VERSION 5.8 ; 
BUSBITCHARS "[]" ; 
DIVIDERCHAR "/" ; 
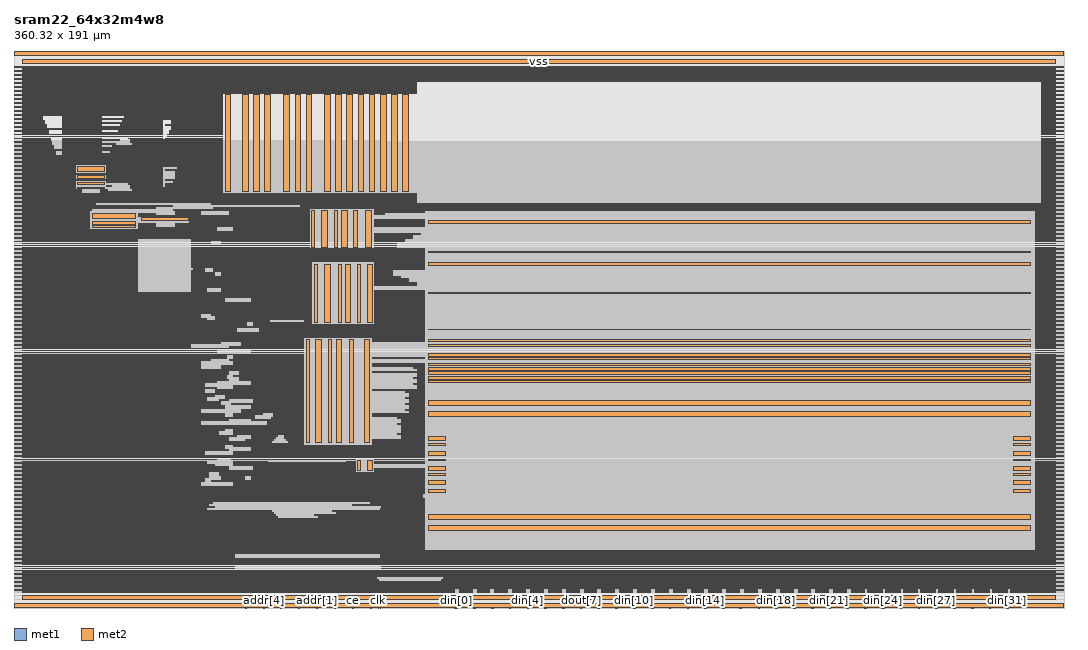
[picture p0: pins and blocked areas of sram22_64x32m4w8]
MACRO sram22_64x32m4w8
    CLASS BLOCK  ;
    FOREIGN sram22_64x32m4w8   ;
    SIZE 360.320 BY 191.000 ;
    SYMMETRY X Y R90 ;
    PIN dout[0] 
        DIRECTION OUTPUT ; 
        ANTENNADIFFAREA 0.448000 LAYER met2 ;
        ANTENNAPARTIALMETALAREA 0.950300 LAYER met1 ;
        ANTENNAPARTIALMETALAREA 7.107200 LAYER met2 ;
        PORT 
            LAYER met1 ;
                RECT 152.070 0.000 152.210 0.140 ;
        END 
    END dout[0] 
    PIN dout[1] 
        DIRECTION OUTPUT ; 
        ANTENNADIFFAREA 0.448000 LAYER met2 ;
        ANTENNAPARTIALMETALAREA 0.950300 LAYER met1 ;
        ANTENNAPARTIALMETALAREA 7.107200 LAYER met2 ;
        PORT 
            LAYER met1 ;
                RECT 158.170 0.000 158.310 0.140 ;
        END 
    END dout[1] 
    PIN dout[2] 
        DIRECTION OUTPUT ; 
        ANTENNADIFFAREA 0.448000 LAYER met2 ;
        ANTENNAPARTIALMETALAREA 0.950300 LAYER met1 ;
        ANTENNAPARTIALMETALAREA 7.107200 LAYER met2 ;
        PORT 
            LAYER met1 ;
                RECT 164.270 0.000 164.410 0.140 ;
        END 
    END dout[2] 
    PIN dout[3] 
        DIRECTION OUTPUT ; 
        ANTENNADIFFAREA 0.448000 LAYER met2 ;
        ANTENNAPARTIALMETALAREA 0.950300 LAYER met1 ;
        ANTENNAPARTIALMETALAREA 7.107200 LAYER met2 ;
        PORT 
            LAYER met1 ;
                RECT 170.370 0.000 170.510 0.140 ;
        END 
    END dout[3] 
    PIN dout[4] 
        DIRECTION OUTPUT ; 
        ANTENNADIFFAREA 0.448000 LAYER met2 ;
        ANTENNAPARTIALMETALAREA 0.950300 LAYER met1 ;
        ANTENNAPARTIALMETALAREA 7.107200 LAYER met2 ;
        PORT 
            LAYER met1 ;
                RECT 176.470 0.000 176.610 0.140 ;
        END 
    END dout[4] 
    PIN dout[5] 
        DIRECTION OUTPUT ; 
        ANTENNADIFFAREA 0.448000 LAYER met2 ;
        ANTENNAPARTIALMETALAREA 0.950300 LAYER met1 ;
        ANTENNAPARTIALMETALAREA 7.107200 LAYER met2 ;
        PORT 
            LAYER met1 ;
                RECT 182.570 0.000 182.710 0.140 ;
        END 
    END dout[5] 
    PIN dout[6] 
        DIRECTION OUTPUT ; 
        ANTENNADIFFAREA 0.448000 LAYER met2 ;
        ANTENNAPARTIALMETALAREA 0.950300 LAYER met1 ;
        ANTENNAPARTIALMETALAREA 7.107200 LAYER met2 ;
        PORT 
            LAYER met1 ;
                RECT 188.670 0.000 188.810 0.140 ;
        END 
    END dout[6] 
    PIN dout[7] 
        DIRECTION OUTPUT ; 
        ANTENNADIFFAREA 0.448000 LAYER met2 ;
        ANTENNAPARTIALMETALAREA 0.950300 LAYER met1 ;
        ANTENNAPARTIALMETALAREA 7.107200 LAYER met2 ;
        PORT 
            LAYER met1 ;
                RECT 194.770 0.000 194.910 0.140 ;
        END 
    END dout[7] 
    PIN dout[8] 
        DIRECTION OUTPUT ; 
        ANTENNADIFFAREA 0.448000 LAYER met2 ;
        ANTENNAPARTIALMETALAREA 0.950300 LAYER met1 ;
        ANTENNAPARTIALMETALAREA 7.107200 LAYER met2 ;
        PORT 
            LAYER met1 ;
                RECT 200.870 0.000 201.010 0.140 ;
        END 
    END dout[8] 
    PIN dout[9] 
        DIRECTION OUTPUT ; 
        ANTENNADIFFAREA 0.448000 LAYER met2 ;
        ANTENNAPARTIALMETALAREA 0.950300 LAYER met1 ;
        ANTENNAPARTIALMETALAREA 7.107200 LAYER met2 ;
        PORT 
            LAYER met1 ;
                RECT 206.970 0.000 207.110 0.140 ;
        END 
    END dout[9] 
    PIN dout[10] 
        DIRECTION OUTPUT ; 
        ANTENNADIFFAREA 0.448000 LAYER met2 ;
        ANTENNAPARTIALMETALAREA 0.950300 LAYER met1 ;
        ANTENNAPARTIALMETALAREA 7.107200 LAYER met2 ;
        PORT 
            LAYER met1 ;
                RECT 213.070 0.000 213.210 0.140 ;
        END 
    END dout[10] 
    PIN dout[11] 
        DIRECTION OUTPUT ; 
        ANTENNADIFFAREA 0.448000 LAYER met2 ;
        ANTENNAPARTIALMETALAREA 0.950300 LAYER met1 ;
        ANTENNAPARTIALMETALAREA 7.107200 LAYER met2 ;
        PORT 
            LAYER met1 ;
                RECT 219.170 0.000 219.310 0.140 ;
        END 
    END dout[11] 
    PIN dout[12] 
        DIRECTION OUTPUT ; 
        ANTENNADIFFAREA 0.448000 LAYER met2 ;
        ANTENNAPARTIALMETALAREA 0.950300 LAYER met1 ;
        ANTENNAPARTIALMETALAREA 7.107200 LAYER met2 ;
        PORT 
            LAYER met1 ;
                RECT 225.270 0.000 225.410 0.140 ;
        END 
    END dout[12] 
    PIN dout[13] 
        DIRECTION OUTPUT ; 
        ANTENNADIFFAREA 0.448000 LAYER met2 ;
        ANTENNAPARTIALMETALAREA 0.950300 LAYER met1 ;
        ANTENNAPARTIALMETALAREA 7.107200 LAYER met2 ;
        PORT 
            LAYER met1 ;
                RECT 231.370 0.000 231.510 0.140 ;
        END 
    END dout[13] 
    PIN dout[14] 
        DIRECTION OUTPUT ; 
        ANTENNADIFFAREA 0.448000 LAYER met2 ;
        ANTENNAPARTIALMETALAREA 0.950300 LAYER met1 ;
        ANTENNAPARTIALMETALAREA 7.107200 LAYER met2 ;
        PORT 
            LAYER met1 ;
                RECT 237.470 0.000 237.610 0.140 ;
        END 
    END dout[14] 
    PIN dout[15] 
        DIRECTION OUTPUT ; 
        ANTENNADIFFAREA 0.448000 LAYER met2 ;
        ANTENNAPARTIALMETALAREA 0.950300 LAYER met1 ;
        ANTENNAPARTIALMETALAREA 7.107200 LAYER met2 ;
        PORT 
            LAYER met1 ;
                RECT 243.570 0.000 243.710 0.140 ;
        END 
    END dout[15] 
    PIN dout[16] 
        DIRECTION OUTPUT ; 
        ANTENNADIFFAREA 0.448000 LAYER met2 ;
        ANTENNAPARTIALMETALAREA 0.950300 LAYER met1 ;
        ANTENNAPARTIALMETALAREA 7.107200 LAYER met2 ;
        PORT 
            LAYER met1 ;
                RECT 249.670 0.000 249.810 0.140 ;
        END 
    END dout[16] 
    PIN dout[17] 
        DIRECTION OUTPUT ; 
        ANTENNADIFFAREA 0.448000 LAYER met2 ;
        ANTENNAPARTIALMETALAREA 0.950300 LAYER met1 ;
        ANTENNAPARTIALMETALAREA 7.107200 LAYER met2 ;
        PORT 
            LAYER met1 ;
                RECT 255.770 0.000 255.910 0.140 ;
        END 
    END dout[17] 
    PIN dout[18] 
        DIRECTION OUTPUT ; 
        ANTENNADIFFAREA 0.448000 LAYER met2 ;
        ANTENNAPARTIALMETALAREA 0.950300 LAYER met1 ;
        ANTENNAPARTIALMETALAREA 7.107200 LAYER met2 ;
        PORT 
            LAYER met1 ;
                RECT 261.870 0.000 262.010 0.140 ;
        END 
    END dout[18] 
    PIN dout[19] 
        DIRECTION OUTPUT ; 
        ANTENNADIFFAREA 0.448000 LAYER met2 ;
        ANTENNAPARTIALMETALAREA 0.950300 LAYER met1 ;
        ANTENNAPARTIALMETALAREA 7.107200 LAYER met2 ;
        PORT 
            LAYER met1 ;
                RECT 267.970 0.000 268.110 0.140 ;
        END 
    END dout[19] 
    PIN dout[20] 
        DIRECTION OUTPUT ; 
        ANTENNADIFFAREA 0.448000 LAYER met2 ;
        ANTENNAPARTIALMETALAREA 0.950300 LAYER met1 ;
        ANTENNAPARTIALMETALAREA 7.107200 LAYER met2 ;
        PORT 
            LAYER met1 ;
                RECT 274.070 0.000 274.210 0.140 ;
        END 
    END dout[20] 
    PIN dout[21] 
        DIRECTION OUTPUT ; 
        ANTENNADIFFAREA 0.448000 LAYER met2 ;
        ANTENNAPARTIALMETALAREA 0.950300 LAYER met1 ;
        ANTENNAPARTIALMETALAREA 7.107200 LAYER met2 ;
        PORT 
            LAYER met1 ;
                RECT 280.170 0.000 280.310 0.140 ;
        END 
    END dout[21] 
    PIN dout[22] 
        DIRECTION OUTPUT ; 
        ANTENNADIFFAREA 0.448000 LAYER met2 ;
        ANTENNAPARTIALMETALAREA 0.950300 LAYER met1 ;
        ANTENNAPARTIALMETALAREA 7.107200 LAYER met2 ;
        PORT 
            LAYER met1 ;
                RECT 286.270 0.000 286.410 0.140 ;
        END 
    END dout[22] 
    PIN dout[23] 
        DIRECTION OUTPUT ; 
        ANTENNADIFFAREA 0.448000 LAYER met2 ;
        ANTENNAPARTIALMETALAREA 0.950300 LAYER met1 ;
        ANTENNAPARTIALMETALAREA 7.107200 LAYER met2 ;
        PORT 
            LAYER met1 ;
                RECT 292.370 0.000 292.510 0.140 ;
        END 
    END dout[23] 
    PIN dout[24] 
        DIRECTION OUTPUT ; 
        ANTENNADIFFAREA 0.448000 LAYER met2 ;
        ANTENNAPARTIALMETALAREA 0.950300 LAYER met1 ;
        ANTENNAPARTIALMETALAREA 7.107200 LAYER met2 ;
        PORT 
            LAYER met1 ;
                RECT 298.470 0.000 298.610 0.140 ;
        END 
    END dout[24] 
    PIN dout[25] 
        DIRECTION OUTPUT ; 
        ANTENNADIFFAREA 0.448000 LAYER met2 ;
        ANTENNAPARTIALMETALAREA 0.950300 LAYER met1 ;
        ANTENNAPARTIALMETALAREA 7.107200 LAYER met2 ;
        PORT 
            LAYER met1 ;
                RECT 304.570 0.000 304.710 0.140 ;
        END 
    END dout[25] 
    PIN dout[26] 
        DIRECTION OUTPUT ; 
        ANTENNADIFFAREA 0.448000 LAYER met2 ;
        ANTENNAPARTIALMETALAREA 0.950300 LAYER met1 ;
        ANTENNAPARTIALMETALAREA 7.107200 LAYER met2 ;
        PORT 
            LAYER met1 ;
                RECT 310.670 0.000 310.810 0.140 ;
        END 
    END dout[26] 
    PIN dout[27] 
        DIRECTION OUTPUT ; 
        ANTENNADIFFAREA 0.448000 LAYER met2 ;
        ANTENNAPARTIALMETALAREA 0.950300 LAYER met1 ;
        ANTENNAPARTIALMETALAREA 7.107200 LAYER met2 ;
        PORT 
            LAYER met1 ;
                RECT 316.770 0.000 316.910 0.140 ;
        END 
    END dout[27] 
    PIN dout[28] 
        DIRECTION OUTPUT ; 
        ANTENNADIFFAREA 0.448000 LAYER met2 ;
        ANTENNAPARTIALMETALAREA 0.950300 LAYER met1 ;
        ANTENNAPARTIALMETALAREA 7.107200 LAYER met2 ;
        PORT 
            LAYER met1 ;
                RECT 322.870 0.000 323.010 0.140 ;
        END 
    END dout[28] 
    PIN dout[29] 
        DIRECTION OUTPUT ; 
        ANTENNADIFFAREA 0.448000 LAYER met2 ;
        ANTENNAPARTIALMETALAREA 0.950300 LAYER met1 ;
        ANTENNAPARTIALMETALAREA 7.107200 LAYER met2 ;
        PORT 
            LAYER met1 ;
                RECT 328.970 0.000 329.110 0.140 ;
        END 
    END dout[29] 
    PIN dout[30] 
        DIRECTION OUTPUT ; 
        ANTENNADIFFAREA 0.448000 LAYER met2 ;
        ANTENNAPARTIALMETALAREA 0.950300 LAYER met1 ;
        ANTENNAPARTIALMETALAREA 7.107200 LAYER met2 ;
        PORT 
            LAYER met1 ;
                RECT 335.070 0.000 335.210 0.140 ;
        END 
    END dout[30] 
    PIN dout[31] 
        DIRECTION OUTPUT ; 
        ANTENNADIFFAREA 0.448000 LAYER met2 ;
        ANTENNAPARTIALMETALAREA 0.950300 LAYER met1 ;
        ANTENNAPARTIALMETALAREA 7.107200 LAYER met2 ;
        PORT 
            LAYER met1 ;
                RECT 341.170 0.000 341.310 0.140 ;
        END 
    END dout[31] 
    PIN din[0] 
        DIRECTION INPUT ; 
        ANTENNAGATEAREA 0.126000 LAYER met2 ;
        ANTENNAPARTIALMETALAREA 5.238500 LAYER met1 ;
        ANTENNAPARTIALMETALAREA 6.828800 LAYER met2 ;
        PORT 
            LAYER met1 ;
                RECT 151.650 0.000 151.790 0.140 ;
        END 
    END din[0] 
    PIN din[1] 
        DIRECTION INPUT ; 
        ANTENNAGATEAREA 0.126000 LAYER met2 ;
        ANTENNAPARTIALMETALAREA 5.238500 LAYER met1 ;
        ANTENNAPARTIALMETALAREA 6.828800 LAYER met2 ;
        PORT 
            LAYER met1 ;
                RECT 157.750 0.000 157.890 0.140 ;
        END 
    END din[1] 
    PIN din[2] 
        DIRECTION INPUT ; 
        ANTENNAGATEAREA 0.126000 LAYER met2 ;
        ANTENNAPARTIALMETALAREA 5.238500 LAYER met1 ;
        ANTENNAPARTIALMETALAREA 6.828800 LAYER met2 ;
        PORT 
            LAYER met1 ;
                RECT 163.850 0.000 163.990 0.140 ;
        END 
    END din[2] 
    PIN din[3] 
        DIRECTION INPUT ; 
        ANTENNAGATEAREA 0.126000 LAYER met2 ;
        ANTENNAPARTIALMETALAREA 5.238500 LAYER met1 ;
        ANTENNAPARTIALMETALAREA 6.828800 LAYER met2 ;
        PORT 
            LAYER met1 ;
                RECT 169.950 0.000 170.090 0.140 ;
        END 
    END din[3] 
    PIN din[4] 
        DIRECTION INPUT ; 
        ANTENNAGATEAREA 0.126000 LAYER met2 ;
        ANTENNAPARTIALMETALAREA 5.238500 LAYER met1 ;
        ANTENNAPARTIALMETALAREA 6.828800 LAYER met2 ;
        PORT 
            LAYER met1 ;
                RECT 176.050 0.000 176.190 0.140 ;
        END 
    END din[4] 
    PIN din[5] 
        DIRECTION INPUT ; 
        ANTENNAGATEAREA 0.126000 LAYER met2 ;
        ANTENNAPARTIALMETALAREA 5.238500 LAYER met1 ;
        ANTENNAPARTIALMETALAREA 6.828800 LAYER met2 ;
        PORT 
            LAYER met1 ;
                RECT 182.150 0.000 182.290 0.140 ;
        END 
    END din[5] 
    PIN din[6] 
        DIRECTION INPUT ; 
        ANTENNAGATEAREA 0.126000 LAYER met2 ;
        ANTENNAPARTIALMETALAREA 5.238500 LAYER met1 ;
        ANTENNAPARTIALMETALAREA 6.828800 LAYER met2 ;
        PORT 
            LAYER met1 ;
                RECT 188.250 0.000 188.390 0.140 ;
        END 
    END din[6] 
    PIN din[7] 
        DIRECTION INPUT ; 
        ANTENNAGATEAREA 0.126000 LAYER met2 ;
        ANTENNAPARTIALMETALAREA 5.238500 LAYER met1 ;
        ANTENNAPARTIALMETALAREA 6.828800 LAYER met2 ;
        PORT 
            LAYER met1 ;
                RECT 194.350 0.000 194.490 0.140 ;
        END 
    END din[7] 
    PIN din[8] 
        DIRECTION INPUT ; 
        ANTENNAGATEAREA 0.126000 LAYER met2 ;
        ANTENNAPARTIALMETALAREA 5.238500 LAYER met1 ;
        ANTENNAPARTIALMETALAREA 6.828800 LAYER met2 ;
        PORT 
            LAYER met1 ;
                RECT 200.450 0.000 200.590 0.140 ;
        END 
    END din[8] 
    PIN din[9] 
        DIRECTION INPUT ; 
        ANTENNAGATEAREA 0.126000 LAYER met2 ;
        ANTENNAPARTIALMETALAREA 5.238500 LAYER met1 ;
        ANTENNAPARTIALMETALAREA 6.828800 LAYER met2 ;
        PORT 
            LAYER met1 ;
                RECT 206.550 0.000 206.690 0.140 ;
        END 
    END din[9] 
    PIN din[10] 
        DIRECTION INPUT ; 
        ANTENNAGATEAREA 0.126000 LAYER met2 ;
        ANTENNAPARTIALMETALAREA 5.238500 LAYER met1 ;
        ANTENNAPARTIALMETALAREA 6.828800 LAYER met2 ;
        PORT 
            LAYER met1 ;
                RECT 212.650 0.000 212.790 0.140 ;
        END 
    END din[10] 
    PIN din[11] 
        DIRECTION INPUT ; 
        ANTENNAGATEAREA 0.126000 LAYER met2 ;
        ANTENNAPARTIALMETALAREA 5.238500 LAYER met1 ;
        ANTENNAPARTIALMETALAREA 6.828800 LAYER met2 ;
        PORT 
            LAYER met1 ;
                RECT 218.750 0.000 218.890 0.140 ;
        END 
    END din[11] 
    PIN din[12] 
        DIRECTION INPUT ; 
        ANTENNAGATEAREA 0.126000 LAYER met2 ;
        ANTENNAPARTIALMETALAREA 5.238500 LAYER met1 ;
        ANTENNAPARTIALMETALAREA 6.828800 LAYER met2 ;
        PORT 
            LAYER met1 ;
                RECT 224.850 0.000 224.990 0.140 ;
        END 
    END din[12] 
    PIN din[13] 
        DIRECTION INPUT ; 
        ANTENNAGATEAREA 0.126000 LAYER met2 ;
        ANTENNAPARTIALMETALAREA 5.238500 LAYER met1 ;
        ANTENNAPARTIALMETALAREA 6.828800 LAYER met2 ;
        PORT 
            LAYER met1 ;
                RECT 230.950 0.000 231.090 0.140 ;
        END 
    END din[13] 
    PIN din[14] 
        DIRECTION INPUT ; 
        ANTENNAGATEAREA 0.126000 LAYER met2 ;
        ANTENNAPARTIALMETALAREA 5.238500 LAYER met1 ;
        ANTENNAPARTIALMETALAREA 6.828800 LAYER met2 ;
        PORT 
            LAYER met1 ;
                RECT 237.050 0.000 237.190 0.140 ;
        END 
    END din[14] 
    PIN din[15] 
        DIRECTION INPUT ; 
        ANTENNAGATEAREA 0.126000 LAYER met2 ;
        ANTENNAPARTIALMETALAREA 5.238500 LAYER met1 ;
        ANTENNAPARTIALMETALAREA 6.828800 LAYER met2 ;
        PORT 
            LAYER met1 ;
                RECT 243.150 0.000 243.290 0.140 ;
        END 
    END din[15] 
    PIN din[16] 
        DIRECTION INPUT ; 
        ANTENNAGATEAREA 0.126000 LAYER met2 ;
        ANTENNAPARTIALMETALAREA 5.238500 LAYER met1 ;
        ANTENNAPARTIALMETALAREA 6.828800 LAYER met2 ;
        PORT 
            LAYER met1 ;
                RECT 249.250 0.000 249.390 0.140 ;
        END 
    END din[16] 
    PIN din[17] 
        DIRECTION INPUT ; 
        ANTENNAGATEAREA 0.126000 LAYER met2 ;
        ANTENNAPARTIALMETALAREA 5.238500 LAYER met1 ;
        ANTENNAPARTIALMETALAREA 6.828800 LAYER met2 ;
        PORT 
            LAYER met1 ;
                RECT 255.350 0.000 255.490 0.140 ;
        END 
    END din[17] 
    PIN din[18] 
        DIRECTION INPUT ; 
        ANTENNAGATEAREA 0.126000 LAYER met2 ;
        ANTENNAPARTIALMETALAREA 5.238500 LAYER met1 ;
        ANTENNAPARTIALMETALAREA 6.828800 LAYER met2 ;
        PORT 
            LAYER met1 ;
                RECT 261.450 0.000 261.590 0.140 ;
        END 
    END din[18] 
    PIN din[19] 
        DIRECTION INPUT ; 
        ANTENNAGATEAREA 0.126000 LAYER met2 ;
        ANTENNAPARTIALMETALAREA 5.238500 LAYER met1 ;
        ANTENNAPARTIALMETALAREA 6.828800 LAYER met2 ;
        PORT 
            LAYER met1 ;
                RECT 267.550 0.000 267.690 0.140 ;
        END 
    END din[19] 
    PIN din[20] 
        DIRECTION INPUT ; 
        ANTENNAGATEAREA 0.126000 LAYER met2 ;
        ANTENNAPARTIALMETALAREA 5.238500 LAYER met1 ;
        ANTENNAPARTIALMETALAREA 6.828800 LAYER met2 ;
        PORT 
            LAYER met1 ;
                RECT 273.650 0.000 273.790 0.140 ;
        END 
    END din[20] 
    PIN din[21] 
        DIRECTION INPUT ; 
        ANTENNAGATEAREA 0.126000 LAYER met2 ;
        ANTENNAPARTIALMETALAREA 5.238500 LAYER met1 ;
        ANTENNAPARTIALMETALAREA 6.828800 LAYER met2 ;
        PORT 
            LAYER met1 ;
                RECT 279.750 0.000 279.890 0.140 ;
        END 
    END din[21] 
    PIN din[22] 
        DIRECTION INPUT ; 
        ANTENNAGATEAREA 0.126000 LAYER met2 ;
        ANTENNAPARTIALMETALAREA 5.238500 LAYER met1 ;
        ANTENNAPARTIALMETALAREA 6.828800 LAYER met2 ;
        PORT 
            LAYER met1 ;
                RECT 285.850 0.000 285.990 0.140 ;
        END 
    END din[22] 
    PIN din[23] 
        DIRECTION INPUT ; 
        ANTENNAGATEAREA 0.126000 LAYER met2 ;
        ANTENNAPARTIALMETALAREA 5.238500 LAYER met1 ;
        ANTENNAPARTIALMETALAREA 6.828800 LAYER met2 ;
        PORT 
            LAYER met1 ;
                RECT 291.950 0.000 292.090 0.140 ;
        END 
    END din[23] 
    PIN din[24] 
        DIRECTION INPUT ; 
        ANTENNAGATEAREA 0.126000 LAYER met2 ;
        ANTENNAPARTIALMETALAREA 5.238500 LAYER met1 ;
        ANTENNAPARTIALMETALAREA 6.828800 LAYER met2 ;
        PORT 
            LAYER met1 ;
                RECT 298.050 0.000 298.190 0.140 ;
        END 
    END din[24] 
    PIN din[25] 
        DIRECTION INPUT ; 
        ANTENNAGATEAREA 0.126000 LAYER met2 ;
        ANTENNAPARTIALMETALAREA 5.238500 LAYER met1 ;
        ANTENNAPARTIALMETALAREA 6.828800 LAYER met2 ;
        PORT 
            LAYER met1 ;
                RECT 304.150 0.000 304.290 0.140 ;
        END 
    END din[25] 
    PIN din[26] 
        DIRECTION INPUT ; 
        ANTENNAGATEAREA 0.126000 LAYER met2 ;
        ANTENNAPARTIALMETALAREA 5.238500 LAYER met1 ;
        ANTENNAPARTIALMETALAREA 6.828800 LAYER met2 ;
        PORT 
            LAYER met1 ;
                RECT 310.250 0.000 310.390 0.140 ;
        END 
    END din[26] 
    PIN din[27] 
        DIRECTION INPUT ; 
        ANTENNAGATEAREA 0.126000 LAYER met2 ;
        ANTENNAPARTIALMETALAREA 5.238500 LAYER met1 ;
        ANTENNAPARTIALMETALAREA 6.828800 LAYER met2 ;
        PORT 
            LAYER met1 ;
                RECT 316.350 0.000 316.490 0.140 ;
        END 
    END din[27] 
    PIN din[28] 
        DIRECTION INPUT ; 
        ANTENNAGATEAREA 0.126000 LAYER met2 ;
        ANTENNAPARTIALMETALAREA 5.238500 LAYER met1 ;
        ANTENNAPARTIALMETALAREA 6.828800 LAYER met2 ;
        PORT 
            LAYER met1 ;
                RECT 322.450 0.000 322.590 0.140 ;
        END 
    END din[28] 
    PIN din[29] 
        DIRECTION INPUT ; 
        ANTENNAGATEAREA 0.126000 LAYER met2 ;
        ANTENNAPARTIALMETALAREA 5.238500 LAYER met1 ;
        ANTENNAPARTIALMETALAREA 6.828800 LAYER met2 ;
        PORT 
            LAYER met1 ;
                RECT 328.550 0.000 328.690 0.140 ;
        END 
    END din[29] 
    PIN din[30] 
        DIRECTION INPUT ; 
        ANTENNAGATEAREA 0.126000 LAYER met2 ;
        ANTENNAPARTIALMETALAREA 5.238500 LAYER met1 ;
        ANTENNAPARTIALMETALAREA 6.828800 LAYER met2 ;
        PORT 
            LAYER met1 ;
                RECT 334.650 0.000 334.790 0.140 ;
        END 
    END din[30] 
    PIN din[31] 
        DIRECTION INPUT ; 
        ANTENNAGATEAREA 0.126000 LAYER met2 ;
        ANTENNAPARTIALMETALAREA 5.238500 LAYER met1 ;
        ANTENNAPARTIALMETALAREA 6.828800 LAYER met2 ;
        PORT 
            LAYER met1 ;
                RECT 340.750 0.000 340.890 0.140 ;
        END 
    END din[31] 
    PIN wmask[0] 
        DIRECTION INPUT ; 
        ANTENNAGATEAREA 0.126000 LAYER met2 ;
        ANTENNAPARTIALMETALAREA 3.048900 LAYER met1 ;
        ANTENNAPARTIALMETALAREA 0.278400 LAYER met2 ;
        PORT 
            LAYER met1 ;
                RECT 151.300 0.000 151.440 0.140 ;
        END 
    END wmask[0] 
    PIN wmask[1] 
        DIRECTION INPUT ; 
        ANTENNAGATEAREA 0.126000 LAYER met2 ;
        ANTENNAPARTIALMETALAREA 3.048900 LAYER met1 ;
        ANTENNAPARTIALMETALAREA 0.278400 LAYER met2 ;
        PORT 
            LAYER met1 ;
                RECT 200.100 0.000 200.240 0.140 ;
        END 
    END wmask[1] 
    PIN wmask[2] 
        DIRECTION INPUT ; 
        ANTENNAGATEAREA 0.126000 LAYER met2 ;
        ANTENNAPARTIALMETALAREA 3.048900 LAYER met1 ;
        ANTENNAPARTIALMETALAREA 0.278400 LAYER met2 ;
        PORT 
            LAYER met1 ;
                RECT 248.900 0.000 249.040 0.140 ;
        END 
    END wmask[2] 
    PIN wmask[3] 
        DIRECTION INPUT ; 
        ANTENNAGATEAREA 0.126000 LAYER met2 ;
        ANTENNAPARTIALMETALAREA 3.048900 LAYER met1 ;
        ANTENNAPARTIALMETALAREA 0.278400 LAYER met2 ;
        PORT 
            LAYER met1 ;
                RECT 297.700 0.000 297.840 0.140 ;
        END 
    END wmask[3] 
    PIN addr[0] 
        DIRECTION INPUT ; 
        ANTENNAGATEAREA 0.126000 LAYER met1 ;
        ANTENNAPARTIALMETALAREA 3.880700 LAYER met1 ;
        PORT 
            LAYER met1 ;
                RECT 109.960 0.000 110.280 0.320 ;
        END 
    END addr[0] 
    PIN addr[1] 
        DIRECTION INPUT ; 
        ANTENNAGATEAREA 0.126000 LAYER met1 ;
        ANTENNAPARTIALMETALAREA 3.880700 LAYER met1 ;
        PORT 
            LAYER met1 ;
                RECT 103.840 0.000 104.160 0.320 ;
        END 
    END addr[1] 
    PIN addr[2] 
        DIRECTION INPUT ; 
        ANTENNAGATEAREA 0.126000 LAYER met1 ;
        ANTENNAPARTIALMETALAREA 3.880700 LAYER met1 ;
        PORT 
            LAYER met1 ;
                RECT 97.720 0.000 98.040 0.320 ;
        END 
    END addr[2] 
    PIN addr[3] 
        DIRECTION INPUT ; 
        ANTENNAGATEAREA 0.126000 LAYER met1 ;
        ANTENNAPARTIALMETALAREA 3.880700 LAYER met1 ;
        PORT 
            LAYER met1 ;
                RECT 91.600 0.000 91.920 0.320 ;
        END 
    END addr[3] 
    PIN addr[4] 
        DIRECTION INPUT ; 
        ANTENNAGATEAREA 0.126000 LAYER met1 ;
        ANTENNAPARTIALMETALAREA 3.880700 LAYER met1 ;
        PORT 
            LAYER met1 ;
                RECT 85.480 0.000 85.800 0.320 ;
        END 
    END addr[4] 
    PIN addr[5] 
        DIRECTION INPUT ; 
        ANTENNAGATEAREA 0.126000 LAYER met1 ;
        ANTENNAPARTIALMETALAREA 3.880700 LAYER met1 ;
        PORT 
            LAYER met1 ;
                RECT 79.360 0.000 79.680 0.320 ;
        END 
    END addr[5] 
    PIN we 
        DIRECTION INPUT ; 
        ANTENNAGATEAREA 0.126000 LAYER met1 ;
        ANTENNAPARTIALMETALAREA 3.880700 LAYER met1 ;
        PORT 
            LAYER met1 ;
                RECT 122.200 0.000 122.520 0.320 ;
        END 
    END we 
    PIN ce 
        DIRECTION INPUT ; 
        ANTENNAGATEAREA 0.126000 LAYER met1 ;
        ANTENNAPARTIALMETALAREA 3.880700 LAYER met1 ;
        PORT 
            LAYER met1 ;
                RECT 116.080 0.000 116.400 0.320 ;
        END 
    END ce 
    PIN clk 
        DIRECTION INPUT ; 
        ANTENNAGATEAREA 21.762000 LAYER met2 ;
        PORT 
            LAYER met1 ;
                RECT 124.920 0.000 125.240 0.320 ;
        END 
    END clk 
    PIN rstb 
        DIRECTION INPUT ; 
        ANTENNAGATEAREA 25.668000 LAYER met2 ;
        PORT 
            LAYER met1 ;
                RECT 125.600 0.000 125.920 0.320 ;
        END 
    END rstb 
    PIN vdd 
        DIRECTION INOUT ; 
        USE POWER ; 
        PORT 
            LAYER met2 ;
                RECT 0.160 5.920 151.080 6.240 ;
                RECT 152.800 5.920 157.200 6.240 ;
                RECT 158.920 5.920 163.320 6.240 ;
                RECT 165.040 5.920 169.440 6.240 ;
                RECT 171.160 5.920 175.560 6.240 ;
                RECT 177.280 5.920 181.680 6.240 ;
                RECT 183.400 5.920 187.800 6.240 ;
                RECT 189.520 5.920 193.920 6.240 ;
                RECT 195.640 5.920 200.040 6.240 ;
                RECT 201.760 5.920 206.160 6.240 ;
                RECT 207.880 5.920 212.280 6.240 ;
                RECT 214.000 5.920 218.400 6.240 ;
                RECT 220.120 5.920 224.520 6.240 ;
                RECT 226.240 5.920 230.640 6.240 ;
                RECT 232.360 5.920 236.760 6.240 ;
                RECT 238.480 5.920 242.880 6.240 ;
                RECT 244.600 5.920 249.000 6.240 ;
                RECT 250.720 5.920 255.120 6.240 ;
                RECT 256.840 5.920 261.240 6.240 ;
                RECT 262.960 5.920 267.360 6.240 ;
                RECT 269.080 5.920 273.480 6.240 ;
                RECT 275.200 5.920 279.600 6.240 ;
                RECT 281.320 5.920 285.720 6.240 ;
                RECT 287.440 5.920 291.840 6.240 ;
                RECT 292.880 5.920 297.960 6.240 ;
                RECT 299.000 5.920 304.080 6.240 ;
                RECT 305.120 5.920 310.200 6.240 ;
                RECT 311.240 5.920 316.320 6.240 ;
                RECT 317.360 5.920 322.440 6.240 ;
                RECT 323.480 5.920 328.560 6.240 ;
                RECT 329.600 5.920 334.680 6.240 ;
                RECT 335.720 5.920 340.800 6.240 ;
                RECT 341.840 5.920 360.160 6.240 ;
                RECT 0.160 7.280 360.160 7.600 ;
                RECT 0.160 8.640 360.160 8.960 ;
                RECT 0.160 10.000 124.560 10.320 ;
                RECT 147.360 10.000 360.160 10.320 ;
                RECT 0.160 11.360 360.160 11.680 ;
                RECT 0.160 12.720 360.160 13.040 ;
                RECT 0.160 14.080 75.600 14.400 ;
                RECT 126.280 14.080 360.160 14.400 ;
                RECT 0.160 15.440 360.160 15.760 ;
                RECT 0.160 16.800 360.160 17.120 ;
                RECT 0.160 18.160 75.600 18.480 ;
                RECT 125.600 18.160 360.160 18.480 ;
                RECT 0.160 19.520 360.160 19.840 ;
                RECT 0.160 20.880 140.880 21.200 ;
                RECT 350.680 20.880 360.160 21.200 ;
                RECT 0.160 22.240 140.880 22.560 ;
                RECT 350.680 22.240 360.160 22.560 ;
                RECT 0.160 23.600 140.880 23.920 ;
                RECT 350.680 23.600 360.160 23.920 ;
                RECT 0.160 24.960 140.880 25.280 ;
                RECT 350.680 24.960 360.160 25.280 ;
                RECT 0.160 26.320 140.880 26.640 ;
                RECT 350.680 26.320 360.160 26.640 ;
                RECT 0.160 27.680 140.880 28.000 ;
                RECT 350.680 27.680 360.160 28.000 ;
                RECT 0.160 29.040 140.880 29.360 ;
                RECT 350.680 29.040 360.160 29.360 ;
                RECT 0.160 30.400 140.880 30.720 ;
                RECT 350.680 30.400 360.160 30.720 ;
                RECT 0.160 31.760 89.880 32.080 ;
                RECT 103.160 31.760 140.880 32.080 ;
                RECT 350.680 31.760 360.160 32.080 ;
                RECT 0.160 33.120 88.520 33.440 ;
                RECT 109.280 33.120 140.880 33.440 ;
                RECT 350.680 33.120 360.160 33.440 ;
                RECT 0.160 34.480 68.800 34.800 ;
                RECT 126.280 34.480 140.880 34.800 ;
                RECT 350.680 34.480 360.160 34.800 ;
                RECT 0.160 35.840 68.120 36.160 ;
                RECT 122.200 35.840 140.880 36.160 ;
                RECT 350.680 35.840 360.160 36.160 ;
                RECT 0.160 37.200 140.880 37.520 ;
                RECT 350.680 37.200 360.160 37.520 ;
                RECT 0.160 38.560 140.200 38.880 ;
                RECT 350.680 38.560 360.160 38.880 ;
                RECT 0.160 39.920 140.880 40.240 ;
                RECT 350.680 39.920 360.160 40.240 ;
                RECT 0.160 41.280 140.880 41.600 ;
                RECT 350.680 41.280 360.160 41.600 ;
                RECT 0.160 42.640 64.040 42.960 ;
                RECT 75.280 42.640 140.880 42.960 ;
                RECT 350.680 42.640 360.160 42.960 ;
                RECT 0.160 44.000 65.400 44.320 ;
                RECT 71.200 44.000 79.000 44.320 ;
                RECT 81.400 44.000 140.880 44.320 ;
                RECT 350.680 44.000 360.160 44.320 ;
                RECT 0.160 45.360 66.760 45.680 ;
                RECT 70.520 45.360 140.880 45.680 ;
                RECT 350.680 45.360 360.160 45.680 ;
                RECT 0.160 46.720 117.080 47.040 ;
                RECT 123.560 46.720 140.880 47.040 ;
                RECT 350.680 46.720 360.160 47.040 ;
                RECT 0.160 48.080 73.560 48.400 ;
                RECT 82.080 48.080 117.080 48.400 ;
                RECT 350.680 48.080 360.160 48.400 ;
                RECT 0.160 49.440 66.080 49.760 ;
                RECT 75.280 49.440 117.080 49.760 ;
                RECT 123.560 49.440 140.880 49.760 ;
                RECT 350.680 49.440 360.160 49.760 ;
                RECT 0.160 50.800 69.480 51.120 ;
                RECT 74.600 50.800 117.080 51.120 ;
                RECT 123.560 50.800 140.880 51.120 ;
                RECT 350.680 50.800 360.160 51.120 ;
                RECT 0.160 52.160 140.880 52.480 ;
                RECT 350.680 52.160 360.160 52.480 ;
                RECT 0.160 53.520 65.400 53.840 ;
                RECT 75.280 53.520 140.880 53.840 ;
                RECT 350.680 53.520 360.160 53.840 ;
                RECT 0.160 54.880 72.200 55.200 ;
                RECT 81.400 54.880 140.880 55.200 ;
                RECT 350.680 54.880 360.160 55.200 ;
                RECT 0.160 56.240 99.400 56.560 ;
                RECT 122.880 56.240 140.880 56.560 ;
                RECT 350.680 56.240 360.160 56.560 ;
                RECT 0.160 57.600 73.560 57.920 ;
                RECT 79.360 57.600 89.200 57.920 ;
                RECT 93.640 57.600 99.400 57.920 ;
                RECT 122.880 57.600 140.880 57.920 ;
                RECT 350.680 57.600 360.160 57.920 ;
                RECT 0.160 58.960 76.280 59.280 ;
                RECT 81.400 58.960 90.560 59.280 ;
                RECT 92.960 58.960 99.400 59.280 ;
                RECT 133.080 58.960 140.880 59.280 ;
                RECT 350.680 58.960 360.160 59.280 ;
                RECT 0.160 60.320 70.160 60.640 ;
                RECT 75.280 60.320 99.400 60.640 ;
                RECT 133.080 60.320 140.880 60.640 ;
                RECT 350.680 60.320 360.160 60.640 ;
                RECT 0.160 61.680 99.400 62.000 ;
                RECT 133.080 61.680 140.880 62.000 ;
                RECT 350.680 61.680 360.160 62.000 ;
                RECT 0.160 63.040 64.040 63.360 ;
                RECT 86.840 63.040 99.400 63.360 ;
                RECT 131.720 63.040 140.880 63.360 ;
                RECT 350.680 63.040 360.160 63.360 ;
                RECT 0.160 64.400 73.560 64.720 ;
                RECT 81.400 64.400 99.400 64.720 ;
                RECT 133.080 64.400 140.880 64.720 ;
                RECT 350.680 64.400 360.160 64.720 ;
                RECT 0.160 65.760 72.200 66.080 ;
                RECT 75.280 65.760 82.400 66.080 ;
                RECT 88.880 65.760 99.400 66.080 ;
                RECT 122.880 65.760 140.880 66.080 ;
                RECT 350.680 65.760 360.160 66.080 ;
                RECT 0.160 67.120 64.040 67.440 ;
                RECT 78.000 67.120 99.400 67.440 ;
                RECT 135.800 67.120 140.880 67.440 ;
                RECT 350.680 67.120 360.160 67.440 ;
                RECT 0.160 68.480 72.200 68.800 ;
                RECT 81.400 68.480 99.400 68.800 ;
                RECT 135.800 68.480 140.880 68.800 ;
                RECT 350.680 68.480 360.160 68.800 ;
                RECT 0.160 69.840 70.840 70.160 ;
                RECT 74.600 69.840 99.400 70.160 ;
                RECT 134.440 69.840 140.880 70.160 ;
                RECT 350.680 69.840 360.160 70.160 ;
                RECT 0.160 71.200 66.080 71.520 ;
                RECT 70.520 71.200 73.560 71.520 ;
                RECT 82.080 71.200 99.400 71.520 ;
                RECT 135.800 71.200 140.880 71.520 ;
                RECT 350.680 71.200 360.160 71.520 ;
                RECT 0.160 72.560 68.800 72.880 ;
                RECT 72.560 72.560 99.400 72.880 ;
                RECT 135.800 72.560 140.880 72.880 ;
                RECT 350.680 72.560 360.160 72.880 ;
                RECT 0.160 73.920 65.400 74.240 ;
                RECT 69.160 73.920 99.400 74.240 ;
                RECT 134.440 73.920 140.880 74.240 ;
                RECT 350.680 73.920 360.160 74.240 ;
                RECT 0.160 75.280 69.480 75.600 ;
                RECT 75.280 75.280 99.400 75.600 ;
                RECT 138.520 75.280 140.880 75.600 ;
                RECT 350.680 75.280 360.160 75.600 ;
                RECT 0.160 76.640 65.400 76.960 ;
                RECT 81.400 76.640 99.400 76.960 ;
                RECT 137.160 76.640 140.880 76.960 ;
                RECT 350.680 76.640 360.160 76.960 ;
                RECT 0.160 78.000 73.560 78.320 ;
                RECT 77.320 78.000 99.400 78.320 ;
                RECT 138.520 78.000 140.880 78.320 ;
                RECT 350.680 78.000 360.160 78.320 ;
                RECT 0.160 79.360 72.880 79.680 ;
                RECT 75.280 79.360 99.400 79.680 ;
                RECT 138.520 79.360 140.880 79.680 ;
                RECT 350.680 79.360 360.160 79.680 ;
                RECT 0.160 80.720 73.560 81.040 ;
                RECT 77.320 80.720 99.400 81.040 ;
                RECT 122.880 80.720 140.880 81.040 ;
                RECT 350.680 80.720 360.160 81.040 ;
                RECT 0.160 82.080 64.040 82.400 ;
                RECT 71.200 82.080 99.400 82.400 ;
                RECT 137.160 82.080 140.880 82.400 ;
                RECT 350.680 82.080 360.160 82.400 ;
                RECT 0.160 83.440 64.040 83.760 ;
                RECT 75.280 83.440 99.400 83.760 ;
                RECT 122.880 83.440 140.880 83.760 ;
                RECT 350.680 83.440 360.160 83.760 ;
                RECT 0.160 84.800 67.440 85.120 ;
                RECT 73.920 84.800 99.400 85.120 ;
                RECT 350.680 84.800 360.160 85.120 ;
                RECT 0.160 86.160 72.880 86.480 ;
                RECT 75.280 86.160 99.400 86.480 ;
                RECT 350.680 86.160 360.160 86.480 ;
                RECT 0.160 87.520 69.480 87.840 ;
                RECT 81.400 87.520 99.400 87.840 ;
                RECT 350.680 87.520 360.160 87.840 ;
                RECT 0.160 88.880 99.400 89.200 ;
                RECT 350.680 88.880 360.160 89.200 ;
                RECT 0.160 90.240 60.640 90.560 ;
                RECT 78.000 90.240 99.400 90.560 ;
                RECT 350.680 90.240 360.160 90.560 ;
                RECT 0.160 91.600 99.400 91.920 ;
                RECT 122.880 91.600 140.880 91.920 ;
                RECT 350.680 91.600 360.160 91.920 ;
                RECT 0.160 92.960 140.880 93.280 ;
                RECT 350.680 92.960 360.160 93.280 ;
                RECT 0.160 94.320 140.880 94.640 ;
                RECT 350.680 94.320 360.160 94.640 ;
                RECT 0.160 95.680 76.280 96.000 ;
                RECT 84.120 95.680 140.880 96.000 ;
                RECT 350.680 95.680 360.160 96.000 ;
                RECT 0.160 97.040 79.680 97.360 ;
                RECT 82.080 97.040 140.880 97.360 ;
                RECT 350.680 97.040 360.160 97.360 ;
                RECT 0.160 98.400 87.840 98.720 ;
                RECT 99.760 98.400 102.120 98.720 ;
                RECT 123.560 98.400 140.880 98.720 ;
                RECT 350.680 98.400 360.160 98.720 ;
                RECT 0.160 99.760 64.040 100.080 ;
                RECT 69.160 99.760 102.120 100.080 ;
                RECT 123.560 99.760 140.880 100.080 ;
                RECT 350.680 99.760 360.160 100.080 ;
                RECT 0.160 101.120 102.120 101.440 ;
                RECT 123.560 101.120 140.880 101.440 ;
                RECT 350.680 101.120 360.160 101.440 ;
                RECT 0.160 102.480 102.120 102.800 ;
                RECT 123.560 102.480 140.880 102.800 ;
                RECT 350.680 102.480 360.160 102.800 ;
                RECT 0.160 103.840 102.120 104.160 ;
                RECT 123.560 103.840 140.880 104.160 ;
                RECT 350.680 103.840 360.160 104.160 ;
                RECT 0.160 105.200 72.200 105.520 ;
                RECT 81.400 105.200 102.120 105.520 ;
                RECT 123.560 105.200 140.880 105.520 ;
                RECT 350.680 105.200 360.160 105.520 ;
                RECT 0.160 106.560 102.120 106.880 ;
                RECT 123.560 106.560 140.880 106.880 ;
                RECT 350.680 106.560 360.160 106.880 ;
                RECT 0.160 107.920 102.120 108.240 ;
                RECT 123.560 107.920 140.880 108.240 ;
                RECT 350.680 107.920 360.160 108.240 ;
                RECT 0.160 109.280 42.280 109.600 ;
                RECT 61.000 109.280 66.080 109.600 ;
                RECT 71.200 109.280 102.120 109.600 ;
                RECT 350.680 109.280 360.160 109.600 ;
                RECT 0.160 110.640 42.280 110.960 ;
                RECT 61.000 110.640 102.120 110.960 ;
                RECT 123.560 110.640 138.160 110.960 ;
                RECT 350.680 110.640 360.160 110.960 ;
                RECT 0.160 112.000 42.280 112.320 ;
                RECT 61.000 112.000 102.120 112.320 ;
                RECT 123.560 112.000 135.440 112.320 ;
                RECT 350.680 112.000 360.160 112.320 ;
                RECT 0.160 113.360 42.280 113.680 ;
                RECT 61.000 113.360 102.120 113.680 ;
                RECT 123.560 113.360 132.720 113.680 ;
                RECT 350.680 113.360 360.160 113.680 ;
                RECT 0.160 114.720 42.280 115.040 ;
                RECT 61.000 114.720 68.800 115.040 ;
                RECT 71.200 114.720 102.120 115.040 ;
                RECT 123.560 114.720 130.000 115.040 ;
                RECT 350.680 114.720 360.160 115.040 ;
                RECT 0.160 116.080 42.280 116.400 ;
                RECT 61.680 116.080 65.400 116.400 ;
                RECT 68.480 116.080 102.120 116.400 ;
                RECT 123.560 116.080 140.880 116.400 ;
                RECT 350.680 116.080 360.160 116.400 ;
                RECT 0.160 117.440 42.280 117.760 ;
                RECT 61.000 117.440 102.120 117.760 ;
                RECT 123.560 117.440 140.880 117.760 ;
                RECT 350.680 117.440 360.160 117.760 ;
                RECT 0.160 118.800 42.280 119.120 ;
                RECT 61.000 118.800 140.880 119.120 ;
                RECT 350.680 118.800 360.160 119.120 ;
                RECT 0.160 120.160 42.280 120.480 ;
                RECT 61.000 120.160 140.880 120.480 ;
                RECT 350.680 120.160 360.160 120.480 ;
                RECT 0.160 121.520 42.280 121.840 ;
                RECT 61.000 121.520 140.880 121.840 ;
                RECT 350.680 121.520 360.160 121.840 ;
                RECT 0.160 122.880 42.280 123.200 ;
                RECT 61.000 122.880 140.880 123.200 ;
                RECT 350.680 122.880 360.160 123.200 ;
                RECT 0.160 124.240 42.280 124.560 ;
                RECT 61.000 124.240 101.440 124.560 ;
                RECT 123.560 124.240 131.360 124.560 ;
                RECT 350.680 124.240 360.160 124.560 ;
                RECT 0.160 125.600 42.280 125.920 ;
                RECT 61.000 125.600 67.440 125.920 ;
                RECT 71.200 125.600 101.440 125.920 ;
                RECT 123.560 125.600 134.080 125.920 ;
                RECT 350.680 125.600 360.160 125.920 ;
                RECT 0.160 126.960 101.440 127.280 ;
                RECT 123.560 126.960 136.800 127.280 ;
                RECT 350.680 126.960 360.160 127.280 ;
                RECT 0.160 128.320 101.440 128.640 ;
                RECT 123.560 128.320 139.520 128.640 ;
                RECT 350.680 128.320 360.160 128.640 ;
                RECT 0.160 129.680 69.480 130.000 ;
                RECT 75.280 129.680 101.440 130.000 ;
                RECT 350.680 129.680 360.160 130.000 ;
                RECT 0.160 131.040 25.960 131.360 ;
                RECT 42.640 131.040 48.400 131.360 ;
                RECT 55.560 131.040 101.440 131.360 ;
                RECT 123.560 131.040 140.880 131.360 ;
                RECT 350.680 131.040 360.160 131.360 ;
                RECT 0.160 132.400 25.960 132.720 ;
                RECT 60.320 132.400 101.440 132.720 ;
                RECT 123.560 132.400 140.880 132.720 ;
                RECT 350.680 132.400 360.160 132.720 ;
                RECT 0.160 133.760 25.960 134.080 ;
                RECT 60.320 133.760 101.440 134.080 ;
                RECT 350.680 133.760 360.160 134.080 ;
                RECT 0.160 135.120 25.960 135.440 ;
                RECT 42.640 135.120 48.400 135.440 ;
                RECT 55.560 135.120 64.040 135.440 ;
                RECT 73.920 135.120 101.440 135.440 ;
                RECT 123.560 135.120 127.280 135.440 ;
                RECT 350.680 135.120 360.160 135.440 ;
                RECT 0.160 136.480 26.640 136.800 ;
                RECT 54.880 136.480 101.440 136.800 ;
                RECT 123.560 136.480 360.160 136.800 ;
                RECT 0.160 137.840 54.520 138.160 ;
                RECT 98.400 137.840 360.160 138.160 ;
                RECT 0.160 139.200 138.160 139.520 ;
                RECT 352.720 139.200 360.160 139.520 ;
                RECT 0.160 140.560 138.160 140.880 ;
                RECT 352.720 140.560 360.160 140.880 ;
                RECT 0.160 141.920 138.160 142.240 ;
                RECT 352.720 141.920 360.160 142.240 ;
                RECT 0.160 143.280 23.240 143.600 ;
                RECT 29.720 143.280 32.080 143.600 ;
                RECT 40.600 143.280 71.520 143.600 ;
                RECT 352.720 143.280 360.160 143.600 ;
                RECT 0.160 144.640 21.200 144.960 ;
                RECT 31.760 144.640 33.440 144.960 ;
                RECT 39.920 144.640 51.120 144.960 ;
                RECT 52.160 144.640 71.520 144.960 ;
                RECT 352.720 144.640 360.160 144.960 ;
                RECT 0.160 146.000 21.200 146.320 ;
                RECT 31.760 146.000 51.120 146.320 ;
                RECT 54.880 146.000 71.520 146.320 ;
                RECT 352.720 146.000 360.160 146.320 ;
                RECT 0.160 147.360 21.200 147.680 ;
                RECT 31.760 147.360 51.120 147.680 ;
                RECT 55.560 147.360 71.520 147.680 ;
                RECT 352.720 147.360 360.160 147.680 ;
                RECT 0.160 148.720 51.120 149.040 ;
                RECT 55.560 148.720 71.520 149.040 ;
                RECT 352.720 148.720 360.160 149.040 ;
                RECT 0.160 150.080 21.200 150.400 ;
                RECT 31.760 150.080 51.120 150.400 ;
                RECT 52.160 150.080 71.520 150.400 ;
                RECT 352.720 150.080 360.160 150.400 ;
                RECT 0.160 151.440 21.200 151.760 ;
                RECT 31.760 151.440 71.520 151.760 ;
                RECT 352.720 151.440 360.160 151.760 ;
                RECT 0.160 152.800 71.520 153.120 ;
                RECT 352.720 152.800 360.160 153.120 ;
                RECT 0.160 154.160 71.520 154.480 ;
                RECT 352.720 154.160 360.160 154.480 ;
                RECT 0.160 155.520 14.400 155.840 ;
                RECT 16.800 155.520 71.520 155.840 ;
                RECT 352.720 155.520 360.160 155.840 ;
                RECT 0.160 156.880 71.520 157.200 ;
                RECT 352.720 156.880 360.160 157.200 ;
                RECT 0.160 158.240 13.720 158.560 ;
                RECT 16.800 158.240 30.040 158.560 ;
                RECT 33.800 158.240 71.520 158.560 ;
                RECT 352.720 158.240 360.160 158.560 ;
                RECT 0.160 159.600 13.040 159.920 ;
                RECT 16.800 159.600 30.040 159.920 ;
                RECT 39.920 159.600 71.520 159.920 ;
                RECT 352.720 159.600 360.160 159.920 ;
                RECT 0.160 160.960 12.360 161.280 ;
                RECT 16.800 160.960 30.040 161.280 ;
                RECT 39.240 160.960 51.120 161.280 ;
                RECT 52.160 160.960 71.520 161.280 ;
                RECT 352.720 160.960 360.160 161.280 ;
                RECT 0.160 162.320 51.120 162.640 ;
                RECT 52.840 162.320 71.520 162.640 ;
                RECT 352.720 162.320 360.160 162.640 ;
                RECT 0.160 163.680 11.680 164.000 ;
                RECT 16.800 163.680 30.040 164.000 ;
                RECT 35.840 163.680 51.120 164.000 ;
                RECT 53.520 163.680 71.520 164.000 ;
                RECT 352.720 163.680 360.160 164.000 ;
                RECT 0.160 165.040 11.000 165.360 ;
                RECT 16.800 165.040 51.120 165.360 ;
                RECT 54.200 165.040 71.520 165.360 ;
                RECT 352.720 165.040 360.160 165.360 ;
                RECT 0.160 166.400 10.320 166.720 ;
                RECT 16.800 166.400 51.120 166.720 ;
                RECT 54.200 166.400 71.520 166.720 ;
                RECT 352.720 166.400 360.160 166.720 ;
                RECT 0.160 167.760 9.640 168.080 ;
                RECT 16.800 167.760 71.520 168.080 ;
                RECT 352.720 167.760 360.160 168.080 ;
                RECT 0.160 169.120 71.520 169.440 ;
                RECT 352.720 169.120 360.160 169.440 ;
                RECT 0.160 170.480 71.520 170.800 ;
                RECT 352.720 170.480 360.160 170.800 ;
                RECT 0.160 171.840 71.520 172.160 ;
                RECT 352.720 171.840 360.160 172.160 ;
                RECT 0.160 173.200 71.520 173.520 ;
                RECT 352.720 173.200 360.160 173.520 ;
                RECT 0.160 174.560 71.520 174.880 ;
                RECT 352.720 174.560 360.160 174.880 ;
                RECT 0.160 175.920 71.520 176.240 ;
                RECT 352.720 175.920 360.160 176.240 ;
                RECT 0.160 177.280 138.160 177.600 ;
                RECT 352.720 177.280 360.160 177.600 ;
                RECT 0.160 178.640 138.160 178.960 ;
                RECT 352.720 178.640 360.160 178.960 ;
                RECT 0.160 180.000 138.160 180.320 ;
                RECT 352.720 180.000 360.160 180.320 ;
                RECT 0.160 181.360 360.160 181.680 ;
                RECT 0.160 182.720 360.160 183.040 ;
                RECT 0.160 184.080 360.160 184.400 ;
                RECT 0.160 185.440 360.160 185.760 ;
                RECT 0.160 0.160 360.160 1.520 ;
                RECT 0.160 189.480 360.160 190.840 ;
                RECT 142.300 42.275 148.100 43.645 ;
                RECT 343.000 42.275 348.800 43.645 ;
                RECT 142.300 47.315 148.100 48.685 ;
                RECT 343.000 47.315 348.800 48.685 ;
                RECT 142.300 52.415 148.100 53.835 ;
                RECT 343.000 52.415 348.800 53.835 ;
                RECT 142.300 57.585 148.100 59.005 ;
                RECT 343.000 57.585 348.800 59.005 ;
                RECT 142.300 132.025 348.800 132.825 ;
                RECT 142.300 65.770 348.800 67.570 ;
                RECT 142.300 117.700 348.800 118.570 ;
                RECT 142.300 95.445 348.800 95.735 ;
                RECT 142.300 77.240 348.800 78.040 ;
                RECT 142.300 80.250 348.800 81.050 ;
                RECT 142.300 85.140 348.800 85.940 ;
                RECT 142.300 91.365 348.800 92.165 ;
                RECT 142.300 26.520 348.800 28.320 ;
                RECT 78.435 142.995 80.355 176.175 ;
                RECT 82.275 142.995 84.195 176.175 ;
                RECT 86.115 142.995 88.035 176.175 ;
                RECT 106.555 142.995 108.475 176.175 ;
                RECT 110.395 142.995 112.315 176.175 ;
                RECT 114.235 142.995 116.155 176.175 ;
                RECT 118.075 142.995 119.995 176.175 ;
                RECT 121.915 142.995 123.835 176.175 ;
                RECT 125.755 142.995 127.675 176.175 ;
                RECT 129.595 142.995 131.515 176.175 ;
                RECT 133.435 142.995 135.355 176.175 ;
                RECT 103.580 56.680 105.500 92.080 ;
                RECT 110.555 56.680 112.475 92.080 ;
                RECT 120.110 56.680 122.030 92.080 ;
                RECT 105.495 123.880 107.415 136.360 ;
                RECT 112.555 123.880 114.305 136.360 ;
                RECT 120.735 123.880 122.655 136.360 ;
                RECT 106.570 98.080 108.490 117.880 ;
                RECT 113.845 98.080 115.595 117.880 ;
                RECT 121.165 98.080 123.085 117.880 ;
                RECT 121.185 47.100 123.105 50.680 ;
                RECT 21.950 145.265 31.110 146.015 ;
                RECT 21.950 149.890 31.110 151.640 ;
                RECT 43.680 133.050 59.720 133.850 ;
                RECT 26.880 133.760 41.720 135.450 ;
        END 
    END vdd 
    PIN vss 
        DIRECTION INOUT ; 
        USE GROUND ; 
        PORT 
            LAYER met2 ;
                RECT 2.880 5.240 151.080 5.560 ;
                RECT 152.800 5.240 157.200 5.560 ;
                RECT 158.920 5.240 163.320 5.560 ;
                RECT 165.040 5.240 169.440 5.560 ;
                RECT 171.160 5.240 175.560 5.560 ;
                RECT 177.280 5.240 181.680 5.560 ;
                RECT 183.400 5.240 187.800 5.560 ;
                RECT 189.520 5.240 193.920 5.560 ;
                RECT 195.640 5.240 200.040 5.560 ;
                RECT 201.760 5.240 206.160 5.560 ;
                RECT 207.880 5.240 212.280 5.560 ;
                RECT 214.000 5.240 218.400 5.560 ;
                RECT 220.120 5.240 224.520 5.560 ;
                RECT 226.240 5.240 230.640 5.560 ;
                RECT 232.360 5.240 236.760 5.560 ;
                RECT 238.480 5.240 242.880 5.560 ;
                RECT 244.600 5.240 249.000 5.560 ;
                RECT 250.720 5.240 255.120 5.560 ;
                RECT 256.840 5.240 261.240 5.560 ;
                RECT 262.960 5.240 267.360 5.560 ;
                RECT 269.080 5.240 273.480 5.560 ;
                RECT 275.200 5.240 279.600 5.560 ;
                RECT 281.320 5.240 285.720 5.560 ;
                RECT 287.440 5.240 291.840 5.560 ;
                RECT 292.880 5.240 297.960 5.560 ;
                RECT 299.000 5.240 304.080 5.560 ;
                RECT 305.120 5.240 310.200 5.560 ;
                RECT 311.240 5.240 316.320 5.560 ;
                RECT 317.360 5.240 322.440 5.560 ;
                RECT 323.480 5.240 328.560 5.560 ;
                RECT 329.600 5.240 334.680 5.560 ;
                RECT 335.720 5.240 340.800 5.560 ;
                RECT 341.840 5.240 357.440 5.560 ;
                RECT 2.880 6.600 357.440 6.920 ;
                RECT 2.880 7.960 357.440 8.280 ;
                RECT 2.880 9.320 125.240 9.640 ;
                RECT 146.680 9.320 357.440 9.640 ;
                RECT 2.880 10.680 357.440 11.000 ;
                RECT 2.880 12.040 357.440 12.360 ;
                RECT 2.880 13.400 75.600 13.720 ;
                RECT 126.280 13.400 357.440 13.720 ;
                RECT 2.880 14.760 357.440 15.080 ;
                RECT 2.880 16.120 357.440 16.440 ;
                RECT 2.880 17.480 75.600 17.800 ;
                RECT 125.600 17.480 357.440 17.800 ;
                RECT 2.880 18.840 357.440 19.160 ;
                RECT 2.880 20.200 140.880 20.520 ;
                RECT 350.680 20.200 357.440 20.520 ;
                RECT 2.880 21.560 140.880 21.880 ;
                RECT 350.680 21.560 357.440 21.880 ;
                RECT 2.880 22.920 140.880 23.240 ;
                RECT 350.680 22.920 357.440 23.240 ;
                RECT 2.880 24.280 140.880 24.600 ;
                RECT 350.680 24.280 357.440 24.600 ;
                RECT 2.880 25.640 140.880 25.960 ;
                RECT 350.680 25.640 357.440 25.960 ;
                RECT 2.880 27.000 140.880 27.320 ;
                RECT 350.680 27.000 357.440 27.320 ;
                RECT 2.880 28.360 140.880 28.680 ;
                RECT 350.680 28.360 357.440 28.680 ;
                RECT 2.880 29.720 140.880 30.040 ;
                RECT 350.680 29.720 357.440 30.040 ;
                RECT 2.880 31.080 90.560 31.400 ;
                RECT 104.520 31.080 140.880 31.400 ;
                RECT 350.680 31.080 357.440 31.400 ;
                RECT 2.880 32.440 89.200 32.760 ;
                RECT 110.640 32.440 140.880 32.760 ;
                RECT 350.680 32.440 357.440 32.760 ;
                RECT 2.880 33.800 66.080 34.120 ;
                RECT 125.600 33.800 140.880 34.120 ;
                RECT 350.680 33.800 357.440 34.120 ;
                RECT 2.880 35.160 66.760 35.480 ;
                RECT 116.080 35.160 140.880 35.480 ;
                RECT 350.680 35.160 357.440 35.480 ;
                RECT 2.880 36.520 140.880 36.840 ;
                RECT 350.680 36.520 357.440 36.840 ;
                RECT 2.880 37.880 140.200 38.200 ;
                RECT 350.680 37.880 357.440 38.200 ;
                RECT 2.880 39.240 140.880 39.560 ;
                RECT 350.680 39.240 357.440 39.560 ;
                RECT 2.880 40.600 140.880 40.920 ;
                RECT 350.680 40.600 357.440 40.920 ;
                RECT 2.880 41.960 64.040 42.280 ;
                RECT 75.280 41.960 140.880 42.280 ;
                RECT 350.680 41.960 357.440 42.280 ;
                RECT 2.880 43.320 65.400 43.640 ;
                RECT 67.800 43.320 140.880 43.640 ;
                RECT 350.680 43.320 357.440 43.640 ;
                RECT 2.880 44.680 66.760 45.000 ;
                RECT 71.200 44.680 79.000 45.000 ;
                RECT 81.400 44.680 140.880 45.000 ;
                RECT 350.680 44.680 357.440 45.000 ;
                RECT 2.880 46.040 66.760 46.360 ;
                RECT 70.520 46.040 140.880 46.360 ;
                RECT 350.680 46.040 357.440 46.360 ;
                RECT 2.880 47.400 73.560 47.720 ;
                RECT 82.080 47.400 117.080 47.720 ;
                RECT 123.560 47.400 140.880 47.720 ;
                RECT 350.680 47.400 357.440 47.720 ;
                RECT 2.880 48.760 68.800 49.080 ;
                RECT 75.280 48.760 117.080 49.080 ;
                RECT 350.680 48.760 357.440 49.080 ;
                RECT 2.880 50.120 66.080 50.440 ;
                RECT 75.280 50.120 87.160 50.440 ;
                RECT 114.040 50.120 117.080 50.440 ;
                RECT 123.560 50.120 140.880 50.440 ;
                RECT 350.680 50.120 357.440 50.440 ;
                RECT 2.880 51.480 140.880 51.800 ;
                RECT 350.680 51.480 357.440 51.800 ;
                RECT 2.880 52.840 65.400 53.160 ;
                RECT 75.280 52.840 140.880 53.160 ;
                RECT 350.680 52.840 357.440 53.160 ;
                RECT 2.880 54.200 73.560 54.520 ;
                RECT 81.400 54.200 140.880 54.520 ;
                RECT 350.680 54.200 357.440 54.520 ;
                RECT 2.880 55.560 72.200 55.880 ;
                RECT 75.280 55.560 140.880 55.880 ;
                RECT 350.680 55.560 357.440 55.880 ;
                RECT 2.880 56.920 88.520 57.240 ;
                RECT 94.320 56.920 99.400 57.240 ;
                RECT 122.880 56.920 140.880 57.240 ;
                RECT 350.680 56.920 357.440 57.240 ;
                RECT 2.880 58.280 73.560 58.600 ;
                RECT 81.400 58.280 89.880 58.600 ;
                RECT 92.960 58.280 99.400 58.600 ;
                RECT 133.080 58.280 140.880 58.600 ;
                RECT 350.680 58.280 357.440 58.600 ;
                RECT 2.880 59.640 70.160 59.960 ;
                RECT 75.280 59.640 99.400 59.960 ;
                RECT 131.720 59.640 140.880 59.960 ;
                RECT 350.680 59.640 357.440 59.960 ;
                RECT 2.880 61.000 72.200 61.320 ;
                RECT 75.280 61.000 99.400 61.320 ;
                RECT 133.080 61.000 140.880 61.320 ;
                RECT 350.680 61.000 357.440 61.320 ;
                RECT 2.880 62.360 99.400 62.680 ;
                RECT 133.080 62.360 140.880 62.680 ;
                RECT 350.680 62.360 357.440 62.680 ;
                RECT 2.880 63.720 64.040 64.040 ;
                RECT 86.840 63.720 99.400 64.040 ;
                RECT 133.080 63.720 140.880 64.040 ;
                RECT 350.680 63.720 357.440 64.040 ;
                RECT 2.880 65.080 82.400 65.400 ;
                RECT 88.200 65.080 99.400 65.400 ;
                RECT 131.720 65.080 140.880 65.400 ;
                RECT 350.680 65.080 357.440 65.400 ;
                RECT 2.880 66.440 72.200 66.760 ;
                RECT 75.280 66.440 85.120 66.760 ;
                RECT 88.880 66.440 99.400 66.760 ;
                RECT 122.880 66.440 140.880 66.760 ;
                RECT 350.680 66.440 357.440 66.760 ;
                RECT 2.880 67.800 64.040 68.120 ;
                RECT 78.000 67.800 99.400 68.120 ;
                RECT 134.440 67.800 140.880 68.120 ;
                RECT 350.680 67.800 357.440 68.120 ;
                RECT 2.880 69.160 72.200 69.480 ;
                RECT 81.400 69.160 99.400 69.480 ;
                RECT 135.800 69.160 140.880 69.480 ;
                RECT 350.680 69.160 357.440 69.480 ;
                RECT 2.880 70.520 70.840 70.840 ;
                RECT 82.080 70.520 99.400 70.840 ;
                RECT 135.800 70.520 140.880 70.840 ;
                RECT 350.680 70.520 357.440 70.840 ;
                RECT 2.880 71.880 66.080 72.200 ;
                RECT 72.560 71.880 99.400 72.200 ;
                RECT 134.440 71.880 140.880 72.200 ;
                RECT 350.680 71.880 357.440 72.200 ;
                RECT 2.880 73.240 99.400 73.560 ;
                RECT 135.800 73.240 140.880 73.560 ;
                RECT 350.680 73.240 357.440 73.560 ;
                RECT 2.880 74.600 65.400 74.920 ;
                RECT 69.160 74.600 99.400 74.920 ;
                RECT 122.880 74.600 140.880 74.920 ;
                RECT 350.680 74.600 357.440 74.920 ;
                RECT 2.880 75.960 65.400 76.280 ;
                RECT 75.280 75.960 99.400 76.280 ;
                RECT 138.520 75.960 140.880 76.280 ;
                RECT 350.680 75.960 357.440 76.280 ;
                RECT 2.880 77.320 69.480 77.640 ;
                RECT 81.400 77.320 99.400 77.640 ;
                RECT 138.520 77.320 140.880 77.640 ;
                RECT 350.680 77.320 357.440 77.640 ;
                RECT 2.880 78.680 72.880 79.000 ;
                RECT 77.320 78.680 99.400 79.000 ;
                RECT 137.160 78.680 140.880 79.000 ;
                RECT 350.680 78.680 357.440 79.000 ;
                RECT 2.880 80.040 73.560 80.360 ;
                RECT 77.320 80.040 99.400 80.360 ;
                RECT 138.520 80.040 140.880 80.360 ;
                RECT 350.680 80.040 357.440 80.360 ;
                RECT 2.880 81.400 99.400 81.720 ;
                RECT 138.520 81.400 140.880 81.720 ;
                RECT 350.680 81.400 357.440 81.720 ;
                RECT 2.880 82.760 64.040 83.080 ;
                RECT 71.200 82.760 99.400 83.080 ;
                RECT 122.880 82.760 140.880 83.080 ;
                RECT 350.680 82.760 357.440 83.080 ;
                RECT 2.880 84.120 64.040 84.440 ;
                RECT 75.280 84.120 99.400 84.440 ;
                RECT 350.680 84.120 357.440 84.440 ;
                RECT 2.880 85.480 72.880 85.800 ;
                RECT 75.280 85.480 99.400 85.800 ;
                RECT 122.880 85.480 140.880 85.800 ;
                RECT 350.680 85.480 357.440 85.800 ;
                RECT 2.880 86.840 99.400 87.160 ;
                RECT 350.680 86.840 357.440 87.160 ;
                RECT 2.880 88.200 69.480 88.520 ;
                RECT 81.400 88.200 99.400 88.520 ;
                RECT 350.680 88.200 357.440 88.520 ;
                RECT 2.880 89.560 60.640 89.880 ;
                RECT 73.920 89.560 99.400 89.880 ;
                RECT 350.680 89.560 357.440 89.880 ;
                RECT 2.880 90.920 70.840 91.240 ;
                RECT 78.000 90.920 99.400 91.240 ;
                RECT 350.680 90.920 357.440 91.240 ;
                RECT 2.880 92.280 99.400 92.600 ;
                RECT 122.880 92.280 140.880 92.600 ;
                RECT 350.680 92.280 357.440 92.600 ;
                RECT 2.880 93.640 140.880 93.960 ;
                RECT 350.680 93.640 357.440 93.960 ;
                RECT 2.880 95.000 76.280 95.320 ;
                RECT 84.120 95.000 140.880 95.320 ;
                RECT 350.680 95.000 357.440 95.320 ;
                RECT 2.880 96.360 140.880 96.680 ;
                RECT 350.680 96.360 357.440 96.680 ;
                RECT 2.880 97.720 79.680 98.040 ;
                RECT 82.080 97.720 102.120 98.040 ;
                RECT 123.560 97.720 140.880 98.040 ;
                RECT 350.680 97.720 357.440 98.040 ;
                RECT 2.880 99.080 66.080 99.400 ;
                RECT 69.160 99.080 102.120 99.400 ;
                RECT 123.560 99.080 140.880 99.400 ;
                RECT 350.680 99.080 357.440 99.400 ;
                RECT 2.880 100.440 64.040 100.760 ;
                RECT 67.800 100.440 102.120 100.760 ;
                RECT 123.560 100.440 140.880 100.760 ;
                RECT 350.680 100.440 357.440 100.760 ;
                RECT 2.880 101.800 102.120 102.120 ;
                RECT 123.560 101.800 140.880 102.120 ;
                RECT 350.680 101.800 357.440 102.120 ;
                RECT 2.880 103.160 102.120 103.480 ;
                RECT 123.560 103.160 140.880 103.480 ;
                RECT 350.680 103.160 357.440 103.480 ;
                RECT 2.880 104.520 102.120 104.840 ;
                RECT 123.560 104.520 140.880 104.840 ;
                RECT 350.680 104.520 357.440 104.840 ;
                RECT 2.880 105.880 72.200 106.200 ;
                RECT 81.400 105.880 102.120 106.200 ;
                RECT 123.560 105.880 140.880 106.200 ;
                RECT 350.680 105.880 357.440 106.200 ;
                RECT 2.880 107.240 102.120 107.560 ;
                RECT 123.560 107.240 140.880 107.560 ;
                RECT 350.680 107.240 357.440 107.560 ;
                RECT 2.880 108.600 42.280 108.920 ;
                RECT 61.000 108.600 66.080 108.920 ;
                RECT 71.200 108.600 102.120 108.920 ;
                RECT 123.560 108.600 140.880 108.920 ;
                RECT 350.680 108.600 357.440 108.920 ;
                RECT 2.880 109.960 42.280 110.280 ;
                RECT 61.000 109.960 102.120 110.280 ;
                RECT 350.680 109.960 357.440 110.280 ;
                RECT 2.880 111.320 42.280 111.640 ;
                RECT 61.000 111.320 102.120 111.640 ;
                RECT 123.560 111.320 138.160 111.640 ;
                RECT 350.680 111.320 357.440 111.640 ;
                RECT 2.880 112.680 42.280 113.000 ;
                RECT 61.000 112.680 102.120 113.000 ;
                RECT 123.560 112.680 135.440 113.000 ;
                RECT 350.680 112.680 357.440 113.000 ;
                RECT 2.880 114.040 42.280 114.360 ;
                RECT 61.000 114.040 68.800 114.360 ;
                RECT 71.200 114.040 102.120 114.360 ;
                RECT 123.560 114.040 130.000 114.360 ;
                RECT 350.680 114.040 357.440 114.360 ;
                RECT 2.880 115.400 42.280 115.720 ;
                RECT 61.000 115.400 65.400 115.720 ;
                RECT 68.480 115.400 102.120 115.720 ;
                RECT 123.560 115.400 130.000 115.720 ;
                RECT 350.680 115.400 357.440 115.720 ;
                RECT 2.880 116.760 42.280 117.080 ;
                RECT 61.000 116.760 102.120 117.080 ;
                RECT 123.560 116.760 140.880 117.080 ;
                RECT 350.680 116.760 357.440 117.080 ;
                RECT 2.880 118.120 42.280 118.440 ;
                RECT 61.000 118.120 102.120 118.440 ;
                RECT 123.560 118.120 140.880 118.440 ;
                RECT 350.680 118.120 357.440 118.440 ;
                RECT 2.880 119.480 42.280 119.800 ;
                RECT 61.000 119.480 140.880 119.800 ;
                RECT 350.680 119.480 357.440 119.800 ;
                RECT 2.880 120.840 42.280 121.160 ;
                RECT 61.000 120.840 140.880 121.160 ;
                RECT 350.680 120.840 357.440 121.160 ;
                RECT 2.880 122.200 42.280 122.520 ;
                RECT 61.000 122.200 140.880 122.520 ;
                RECT 350.680 122.200 357.440 122.520 ;
                RECT 2.880 123.560 42.280 123.880 ;
                RECT 61.000 123.560 101.440 123.880 ;
                RECT 123.560 123.560 131.360 123.880 ;
                RECT 350.680 123.560 357.440 123.880 ;
                RECT 2.880 124.920 42.280 125.240 ;
                RECT 61.000 124.920 67.440 125.240 ;
                RECT 71.200 124.920 101.440 125.240 ;
                RECT 123.560 124.920 131.360 125.240 ;
                RECT 350.680 124.920 357.440 125.240 ;
                RECT 2.880 126.280 42.280 126.600 ;
                RECT 61.000 126.280 101.440 126.600 ;
                RECT 123.560 126.280 134.080 126.600 ;
                RECT 350.680 126.280 357.440 126.600 ;
                RECT 2.880 127.640 101.440 127.960 ;
                RECT 123.560 127.640 136.800 127.960 ;
                RECT 350.680 127.640 357.440 127.960 ;
                RECT 2.880 129.000 101.440 129.320 ;
                RECT 350.680 129.000 357.440 129.320 ;
                RECT 2.880 130.360 25.960 130.680 ;
                RECT 42.640 130.360 69.480 130.680 ;
                RECT 75.280 130.360 101.440 130.680 ;
                RECT 350.680 130.360 357.440 130.680 ;
                RECT 2.880 131.720 25.960 132.040 ;
                RECT 42.640 131.720 48.400 132.040 ;
                RECT 55.560 131.720 101.440 132.040 ;
                RECT 123.560 131.720 140.880 132.040 ;
                RECT 350.680 131.720 357.440 132.040 ;
                RECT 2.880 133.080 25.960 133.400 ;
                RECT 60.320 133.080 101.440 133.400 ;
                RECT 123.560 133.080 140.880 133.400 ;
                RECT 350.680 133.080 357.440 133.400 ;
                RECT 2.880 134.440 25.960 134.760 ;
                RECT 42.640 134.440 101.440 134.760 ;
                RECT 350.680 134.440 357.440 134.760 ;
                RECT 2.880 135.800 25.960 136.120 ;
                RECT 55.560 135.800 64.040 136.120 ;
                RECT 73.920 135.800 101.440 136.120 ;
                RECT 123.560 135.800 140.880 136.120 ;
                RECT 350.680 135.800 357.440 136.120 ;
                RECT 2.880 137.160 48.400 137.480 ;
                RECT 68.480 137.160 357.440 137.480 ;
                RECT 2.880 138.520 28.000 138.840 ;
                RECT 67.800 138.520 357.440 138.840 ;
                RECT 2.880 139.880 138.160 140.200 ;
                RECT 352.720 139.880 357.440 140.200 ;
                RECT 2.880 141.240 138.160 141.560 ;
                RECT 352.720 141.240 357.440 141.560 ;
                RECT 2.880 142.600 23.240 142.920 ;
                RECT 29.720 142.600 71.520 142.920 ;
                RECT 352.720 142.600 357.440 142.920 ;
                RECT 2.880 143.960 21.200 144.280 ;
                RECT 39.920 143.960 71.520 144.280 ;
                RECT 352.720 143.960 357.440 144.280 ;
                RECT 2.880 145.320 21.200 145.640 ;
                RECT 39.240 145.320 51.120 145.640 ;
                RECT 52.160 145.320 71.520 145.640 ;
                RECT 352.720 145.320 357.440 145.640 ;
                RECT 2.880 146.680 51.120 147.000 ;
                RECT 52.160 146.680 71.520 147.000 ;
                RECT 352.720 146.680 357.440 147.000 ;
                RECT 2.880 148.040 21.200 148.360 ;
                RECT 31.760 148.040 51.120 148.360 ;
                RECT 55.560 148.040 71.520 148.360 ;
                RECT 352.720 148.040 357.440 148.360 ;
                RECT 2.880 149.400 21.200 149.720 ;
                RECT 31.760 149.400 51.120 149.720 ;
                RECT 55.560 149.400 71.520 149.720 ;
                RECT 352.720 149.400 357.440 149.720 ;
                RECT 2.880 150.760 21.200 151.080 ;
                RECT 31.760 150.760 51.120 151.080 ;
                RECT 56.240 150.760 71.520 151.080 ;
                RECT 352.720 150.760 357.440 151.080 ;
                RECT 2.880 152.120 71.520 152.440 ;
                RECT 352.720 152.120 357.440 152.440 ;
                RECT 2.880 153.480 71.520 153.800 ;
                RECT 352.720 153.480 357.440 153.800 ;
                RECT 2.880 154.840 71.520 155.160 ;
                RECT 352.720 154.840 357.440 155.160 ;
                RECT 2.880 156.200 14.400 156.520 ;
                RECT 16.800 156.200 30.040 156.520 ;
                RECT 33.120 156.200 71.520 156.520 ;
                RECT 352.720 156.200 357.440 156.520 ;
                RECT 2.880 157.560 13.720 157.880 ;
                RECT 16.800 157.560 71.520 157.880 ;
                RECT 352.720 157.560 357.440 157.880 ;
                RECT 2.880 158.920 13.040 159.240 ;
                RECT 16.800 158.920 34.800 159.240 ;
                RECT 40.600 158.920 71.520 159.240 ;
                RECT 352.720 158.920 357.440 159.240 ;
                RECT 2.880 160.280 12.360 160.600 ;
                RECT 16.800 160.280 36.160 160.600 ;
                RECT 39.920 160.280 71.520 160.600 ;
                RECT 352.720 160.280 357.440 160.600 ;
                RECT 2.880 161.640 51.120 161.960 ;
                RECT 52.840 161.640 71.520 161.960 ;
                RECT 352.720 161.640 357.440 161.960 ;
                RECT 2.880 163.000 11.680 163.320 ;
                RECT 16.800 163.000 51.120 163.320 ;
                RECT 53.520 163.000 71.520 163.320 ;
                RECT 352.720 163.000 357.440 163.320 ;
                RECT 2.880 164.360 51.120 164.680 ;
                RECT 54.200 164.360 71.520 164.680 ;
                RECT 352.720 164.360 357.440 164.680 ;
                RECT 2.880 165.720 11.000 166.040 ;
                RECT 16.800 165.720 30.040 166.040 ;
                RECT 36.520 165.720 51.120 166.040 ;
                RECT 52.160 165.720 71.520 166.040 ;
                RECT 352.720 165.720 357.440 166.040 ;
                RECT 2.880 167.080 10.320 167.400 ;
                RECT 16.800 167.080 30.040 167.400 ;
                RECT 37.200 167.080 51.120 167.400 ;
                RECT 54.200 167.080 71.520 167.400 ;
                RECT 352.720 167.080 357.440 167.400 ;
                RECT 2.880 168.440 9.640 168.760 ;
                RECT 16.800 168.440 30.040 168.760 ;
                RECT 37.880 168.440 71.520 168.760 ;
                RECT 352.720 168.440 357.440 168.760 ;
                RECT 2.880 169.800 71.520 170.120 ;
                RECT 352.720 169.800 357.440 170.120 ;
                RECT 2.880 171.160 71.520 171.480 ;
                RECT 352.720 171.160 357.440 171.480 ;
                RECT 2.880 172.520 71.520 172.840 ;
                RECT 352.720 172.520 357.440 172.840 ;
                RECT 2.880 173.880 71.520 174.200 ;
                RECT 352.720 173.880 357.440 174.200 ;
                RECT 2.880 175.240 71.520 175.560 ;
                RECT 352.720 175.240 357.440 175.560 ;
                RECT 2.880 176.600 138.160 176.920 ;
                RECT 352.720 176.600 357.440 176.920 ;
                RECT 2.880 177.960 138.160 178.280 ;
                RECT 352.720 177.960 357.440 178.280 ;
                RECT 2.880 179.320 138.160 179.640 ;
                RECT 352.720 179.320 357.440 179.640 ;
                RECT 2.880 180.680 357.440 181.000 ;
                RECT 2.880 182.040 357.440 182.360 ;
                RECT 2.880 183.400 357.440 183.720 ;
                RECT 2.880 184.760 357.440 185.080 ;
                RECT 2.880 2.880 357.440 4.240 ;
                RECT 2.880 186.760 357.440 188.120 ;
                RECT 142.300 39.630 148.100 40.750 ;
                RECT 343.000 39.630 348.800 40.750 ;
                RECT 142.300 45.420 148.100 46.040 ;
                RECT 343.000 45.420 348.800 46.040 ;
                RECT 142.300 50.470 148.100 51.110 ;
                RECT 343.000 50.470 348.800 51.110 ;
                RECT 142.300 55.640 148.100 56.280 ;
                RECT 343.000 55.640 348.800 56.280 ;
                RECT 142.300 121.980 348.800 122.225 ;
                RECT 142.300 78.560 348.800 79.360 ;
                RECT 142.300 69.510 348.800 71.310 ;
                RECT 142.300 86.460 348.800 87.260 ;
                RECT 142.300 89.645 348.800 90.445 ;
                RECT 142.300 83.250 348.800 84.050 ;
                RECT 142.300 108.005 348.800 108.295 ;
                RECT 142.300 81.570 348.800 82.370 ;
                RECT 142.300 30.260 348.800 32.060 ;
                RECT 72.470 142.995 74.390 176.175 ;
                RECT 92.590 142.995 94.510 176.175 ;
                RECT 96.430 142.995 98.350 176.175 ;
                RECT 100.270 142.995 102.190 176.175 ;
                RECT 100.415 56.680 101.525 92.080 ;
                RECT 107.930 56.680 108.820 92.080 ;
                RECT 115.010 56.680 116.550 92.080 ;
                RECT 102.115 123.880 103.225 136.360 ;
                RECT 110.060 123.880 110.950 136.360 ;
                RECT 116.605 123.880 117.925 136.360 ;
                RECT 102.975 98.080 104.085 117.880 ;
                RECT 111.350 98.080 112.240 117.880 ;
                RECT 117.785 98.080 118.895 117.880 ;
                RECT 117.805 47.100 118.915 50.680 ;
                RECT 21.950 144.060 31.110 144.430 ;
                RECT 21.950 147.395 31.110 148.285 ;
                RECT 26.880 130.420 41.720 131.090 ;
                RECT 26.880 131.720 41.720 132.730 ;
        END 
    END vss 
    OBS 
        LAYER met1 ;
            RECT 0.000 0.000 79.360 0.140 ;
            RECT 79.680 0.000 85.480 0.140 ;
            RECT 85.800 0.000 91.600 0.140 ;
            RECT 91.920 0.000 97.720 0.140 ;
            RECT 98.040 0.000 103.840 0.140 ;
            RECT 104.160 0.000 109.960 0.140 ;
            RECT 110.280 0.000 116.080 0.140 ;
            RECT 116.400 0.000 122.200 0.140 ;
            RECT 122.520 0.000 124.920 0.140 ;
            RECT 125.240 0.000 125.600 0.140 ;
            RECT 125.920 0.000 151.300 0.140 ;
            RECT 151.440 0.000 151.650 0.140 ;
            RECT 151.790 0.000 152.070 0.140 ;
            RECT 152.210 0.000 157.750 0.140 ;
            RECT 157.890 0.000 158.170 0.140 ;
            RECT 158.310 0.000 163.850 0.140 ;
            RECT 163.990 0.000 164.270 0.140 ;
            RECT 164.410 0.000 169.950 0.140 ;
            RECT 170.090 0.000 170.370 0.140 ;
            RECT 170.510 0.000 176.050 0.140 ;
            RECT 176.190 0.000 176.470 0.140 ;
            RECT 176.610 0.000 182.150 0.140 ;
            RECT 182.290 0.000 182.570 0.140 ;
            RECT 182.710 0.000 188.250 0.140 ;
            RECT 188.390 0.000 188.670 0.140 ;
            RECT 188.810 0.000 194.350 0.140 ;
            RECT 194.490 0.000 194.770 0.140 ;
            RECT 194.910 0.000 200.100 0.140 ;
            RECT 200.240 0.000 200.450 0.140 ;
            RECT 200.590 0.000 200.870 0.140 ;
            RECT 201.010 0.000 206.550 0.140 ;
            RECT 206.690 0.000 206.970 0.140 ;
            RECT 207.110 0.000 212.650 0.140 ;
            RECT 212.790 0.000 213.070 0.140 ;
            RECT 213.210 0.000 218.750 0.140 ;
            RECT 218.890 0.000 219.170 0.140 ;
            RECT 219.310 0.000 224.850 0.140 ;
            RECT 224.990 0.000 225.270 0.140 ;
            RECT 225.410 0.000 230.950 0.140 ;
            RECT 231.090 0.000 231.370 0.140 ;
            RECT 231.510 0.000 237.050 0.140 ;
            RECT 237.190 0.000 237.470 0.140 ;
            RECT 237.610 0.000 243.150 0.140 ;
            RECT 243.290 0.000 243.570 0.140 ;
            RECT 243.710 0.000 248.900 0.140 ;
            RECT 249.040 0.000 249.250 0.140 ;
            RECT 249.390 0.000 249.670 0.140 ;
            RECT 249.810 0.000 255.350 0.140 ;
            RECT 255.490 0.000 255.770 0.140 ;
            RECT 255.910 0.000 261.450 0.140 ;
            RECT 261.590 0.000 261.870 0.140 ;
            RECT 262.010 0.000 267.550 0.140 ;
            RECT 267.690 0.000 267.970 0.140 ;
            RECT 268.110 0.000 273.650 0.140 ;
            RECT 273.790 0.000 274.070 0.140 ;
            RECT 274.210 0.000 279.750 0.140 ;
            RECT 279.890 0.000 280.170 0.140 ;
            RECT 280.310 0.000 285.850 0.140 ;
            RECT 285.990 0.000 286.270 0.140 ;
            RECT 286.410 0.000 291.950 0.140 ;
            RECT 292.090 0.000 292.370 0.140 ;
            RECT 292.510 0.000 297.700 0.140 ;
            RECT 297.840 0.000 298.050 0.140 ;
            RECT 298.190 0.000 298.470 0.140 ;
            RECT 298.610 0.000 304.150 0.140 ;
            RECT 304.290 0.000 304.570 0.140 ;
            RECT 304.710 0.000 310.250 0.140 ;
            RECT 310.390 0.000 310.670 0.140 ;
            RECT 310.810 0.000 316.350 0.140 ;
            RECT 316.490 0.000 316.770 0.140 ;
            RECT 316.910 0.000 322.450 0.140 ;
            RECT 322.590 0.000 322.870 0.140 ;
            RECT 323.010 0.000 328.550 0.140 ;
            RECT 328.690 0.000 328.970 0.140 ;
            RECT 329.110 0.000 334.650 0.140 ;
            RECT 334.790 0.000 335.070 0.140 ;
            RECT 335.210 0.000 340.750 0.140 ;
            RECT 340.890 0.000 341.170 0.140 ;
            RECT 341.310 0.000 360.320 0.140 ;
            RECT 0.000 0.140 79.360 0.320 ;
            RECT 79.680 0.140 85.480 0.320 ;
            RECT 85.800 0.140 91.600 0.320 ;
            RECT 91.920 0.140 97.720 0.320 ;
            RECT 98.040 0.140 103.840 0.320 ;
            RECT 104.160 0.140 109.960 0.320 ;
            RECT 110.280 0.140 116.080 0.320 ;
            RECT 116.400 0.140 122.200 0.320 ;
            RECT 122.520 0.140 124.920 0.320 ;
            RECT 125.240 0.140 125.600 0.320 ;
            RECT 125.920 0.140 360.320 0.320 ;
            RECT 0.000 0.320 360.320 191.000 ;
        LAYER met2 ;
            RECT 0.000 0.000 360.320 0.160 ;
            RECT 0.000 0.160 0.160 1.520 ;
            RECT 360.160 0.160 360.320 1.520 ;
            RECT 0.000 1.520 360.320 2.880 ;
            RECT 0.000 2.880 2.880 4.240 ;
            RECT 357.440 2.880 360.320 4.240 ;
            RECT 0.000 4.240 360.320 5.240 ;
            RECT 0.000 5.240 2.880 5.560 ;
            RECT 151.080 5.240 152.800 5.560 ;
            RECT 157.200 5.240 158.920 5.560 ;
            RECT 163.320 5.240 165.040 5.560 ;
            RECT 169.440 5.240 171.160 5.560 ;
            RECT 175.560 5.240 177.280 5.560 ;
            RECT 181.680 5.240 183.400 5.560 ;
            RECT 187.800 5.240 189.520 5.560 ;
            RECT 193.920 5.240 195.640 5.560 ;
            RECT 200.040 5.240 201.760 5.560 ;
            RECT 206.160 5.240 207.880 5.560 ;
            RECT 212.280 5.240 214.000 5.560 ;
            RECT 218.400 5.240 220.120 5.560 ;
            RECT 224.520 5.240 226.240 5.560 ;
            RECT 230.640 5.240 232.360 5.560 ;
            RECT 236.760 5.240 238.480 5.560 ;
            RECT 242.880 5.240 244.600 5.560 ;
            RECT 249.000 5.240 250.720 5.560 ;
            RECT 255.120 5.240 256.840 5.560 ;
            RECT 261.240 5.240 262.960 5.560 ;
            RECT 267.360 5.240 269.080 5.560 ;
            RECT 273.480 5.240 275.200 5.560 ;
            RECT 279.600 5.240 281.320 5.560 ;
            RECT 285.720 5.240 287.440 5.560 ;
            RECT 291.840 5.240 292.880 5.560 ;
            RECT 297.960 5.240 299.000 5.560 ;
            RECT 304.080 5.240 305.120 5.560 ;
            RECT 310.200 5.240 311.240 5.560 ;
            RECT 316.320 5.240 317.360 5.560 ;
            RECT 322.440 5.240 323.480 5.560 ;
            RECT 328.560 5.240 329.600 5.560 ;
            RECT 334.680 5.240 335.720 5.560 ;
            RECT 340.800 5.240 341.840 5.560 ;
            RECT 357.440 5.240 360.320 5.560 ;
            RECT 0.000 5.560 360.320 5.920 ;
            RECT 0.000 5.920 0.160 6.240 ;
            RECT 151.080 5.920 152.800 6.240 ;
            RECT 157.200 5.920 158.920 6.240 ;
            RECT 163.320 5.920 165.040 6.240 ;
            RECT 169.440 5.920 171.160 6.240 ;
            RECT 175.560 5.920 177.280 6.240 ;
            RECT 181.680 5.920 183.400 6.240 ;
            RECT 187.800 5.920 189.520 6.240 ;
            RECT 193.920 5.920 195.640 6.240 ;
            RECT 200.040 5.920 201.760 6.240 ;
            RECT 206.160 5.920 207.880 6.240 ;
            RECT 212.280 5.920 214.000 6.240 ;
            RECT 218.400 5.920 220.120 6.240 ;
            RECT 224.520 5.920 226.240 6.240 ;
            RECT 230.640 5.920 232.360 6.240 ;
            RECT 236.760 5.920 238.480 6.240 ;
            RECT 242.880 5.920 244.600 6.240 ;
            RECT 249.000 5.920 250.720 6.240 ;
            RECT 255.120 5.920 256.840 6.240 ;
            RECT 261.240 5.920 262.960 6.240 ;
            RECT 267.360 5.920 269.080 6.240 ;
            RECT 273.480 5.920 275.200 6.240 ;
            RECT 279.600 5.920 281.320 6.240 ;
            RECT 285.720 5.920 287.440 6.240 ;
            RECT 291.840 5.920 292.880 6.240 ;
            RECT 297.960 5.920 299.000 6.240 ;
            RECT 304.080 5.920 305.120 6.240 ;
            RECT 310.200 5.920 311.240 6.240 ;
            RECT 316.320 5.920 317.360 6.240 ;
            RECT 322.440 5.920 323.480 6.240 ;
            RECT 328.560 5.920 329.600 6.240 ;
            RECT 334.680 5.920 335.720 6.240 ;
            RECT 340.800 5.920 341.840 6.240 ;
            RECT 360.160 5.920 360.320 6.240 ;
            RECT 0.000 6.240 360.320 6.600 ;
            RECT 0.000 6.600 2.880 6.920 ;
            RECT 357.440 6.600 360.320 6.920 ;
            RECT 0.000 6.920 360.320 7.280 ;
            RECT 0.000 7.280 0.160 7.600 ;
            RECT 360.160 7.280 360.320 7.600 ;
            RECT 0.000 7.600 360.320 7.960 ;
            RECT 0.000 7.960 2.880 8.280 ;
            RECT 357.440 7.960 360.320 8.280 ;
            RECT 0.000 8.280 360.320 8.640 ;
            RECT 0.000 8.640 0.160 8.960 ;
            RECT 360.160 8.640 360.320 8.960 ;
            RECT 0.000 8.960 360.320 9.320 ;
            RECT 0.000 9.320 2.880 9.640 ;
            RECT 125.240 9.320 146.680 9.640 ;
            RECT 357.440 9.320 360.320 9.640 ;
            RECT 0.000 9.640 360.320 10.000 ;
            RECT 0.000 10.000 0.160 10.320 ;
            RECT 124.560 10.000 147.360 10.320 ;
            RECT 360.160 10.000 360.320 10.320 ;
            RECT 0.000 10.320 360.320 10.680 ;
            RECT 0.000 10.680 2.880 11.000 ;
            RECT 357.440 10.680 360.320 11.000 ;
            RECT 0.000 11.000 360.320 11.360 ;
            RECT 0.000 11.360 0.160 11.680 ;
            RECT 360.160 11.360 360.320 11.680 ;
            RECT 0.000 11.680 360.320 12.040 ;
            RECT 0.000 12.040 2.880 12.360 ;
            RECT 357.440 12.040 360.320 12.360 ;
            RECT 0.000 12.360 360.320 12.720 ;
            RECT 0.000 12.720 0.160 13.040 ;
            RECT 360.160 12.720 360.320 13.040 ;
            RECT 0.000 13.040 360.320 13.400 ;
            RECT 0.000 13.400 2.880 13.720 ;
            RECT 75.600 13.400 126.280 13.720 ;
            RECT 357.440 13.400 360.320 13.720 ;
            RECT 0.000 13.720 360.320 14.080 ;
            RECT 0.000 14.080 0.160 14.400 ;
            RECT 75.600 14.080 126.280 14.400 ;
            RECT 360.160 14.080 360.320 14.400 ;
            RECT 0.000 14.400 360.320 14.760 ;
            RECT 0.000 14.760 2.880 15.080 ;
            RECT 357.440 14.760 360.320 15.080 ;
            RECT 0.000 15.080 360.320 15.440 ;
            RECT 0.000 15.440 0.160 15.760 ;
            RECT 360.160 15.440 360.320 15.760 ;
            RECT 0.000 15.760 360.320 16.120 ;
            RECT 0.000 16.120 2.880 16.440 ;
            RECT 357.440 16.120 360.320 16.440 ;
            RECT 0.000 16.440 360.320 16.800 ;
            RECT 0.000 16.800 0.160 17.120 ;
            RECT 360.160 16.800 360.320 17.120 ;
            RECT 0.000 17.120 360.320 17.480 ;
            RECT 0.000 17.480 2.880 17.800 ;
            RECT 75.600 17.480 125.600 17.800 ;
            RECT 357.440 17.480 360.320 17.800 ;
            RECT 0.000 17.800 360.320 18.160 ;
            RECT 0.000 18.160 0.160 18.480 ;
            RECT 75.600 18.160 125.600 18.480 ;
            RECT 360.160 18.160 360.320 18.480 ;
            RECT 0.000 18.480 360.320 18.840 ;
            RECT 0.000 18.840 2.880 19.160 ;
            RECT 357.440 18.840 360.320 19.160 ;
            RECT 0.000 19.160 360.320 19.520 ;
            RECT 0.000 19.520 0.160 19.840 ;
            RECT 360.160 19.520 360.320 19.840 ;
            RECT 0.000 19.840 360.320 20.200 ;
            RECT 0.000 20.200 2.880 20.520 ;
            RECT 140.880 20.200 350.680 20.520 ;
            RECT 357.440 20.200 360.320 20.520 ;
            RECT 0.000 20.520 360.320 20.880 ;
            RECT 0.000 20.880 0.160 21.200 ;
            RECT 140.880 20.880 350.680 21.200 ;
            RECT 360.160 20.880 360.320 21.200 ;
            RECT 0.000 21.200 360.320 21.560 ;
            RECT 0.000 21.560 2.880 21.880 ;
            RECT 140.880 21.560 350.680 21.880 ;
            RECT 357.440 21.560 360.320 21.880 ;
            RECT 0.000 21.880 360.320 22.240 ;
            RECT 0.000 22.240 0.160 22.560 ;
            RECT 140.880 22.240 350.680 22.560 ;
            RECT 360.160 22.240 360.320 22.560 ;
            RECT 0.000 22.560 360.320 22.920 ;
            RECT 0.000 22.920 2.880 23.240 ;
            RECT 140.880 22.920 350.680 23.240 ;
            RECT 357.440 22.920 360.320 23.240 ;
            RECT 0.000 23.240 360.320 23.600 ;
            RECT 0.000 23.600 0.160 23.920 ;
            RECT 140.880 23.600 350.680 23.920 ;
            RECT 360.160 23.600 360.320 23.920 ;
            RECT 0.000 23.920 360.320 24.280 ;
            RECT 0.000 24.280 2.880 24.600 ;
            RECT 140.880 24.280 350.680 24.600 ;
            RECT 357.440 24.280 360.320 24.600 ;
            RECT 0.000 24.600 360.320 24.960 ;
            RECT 0.000 24.960 0.160 25.280 ;
            RECT 140.880 24.960 350.680 25.280 ;
            RECT 360.160 24.960 360.320 25.280 ;
            RECT 0.000 25.280 360.320 25.640 ;
            RECT 0.000 25.640 2.880 25.960 ;
            RECT 140.880 25.640 350.680 25.960 ;
            RECT 357.440 25.640 360.320 25.960 ;
            RECT 0.000 25.960 360.320 26.320 ;
            RECT 0.000 26.320 0.160 26.520 ;
            RECT 140.880 26.320 350.680 26.520 ;
            RECT 360.160 26.320 360.320 26.520 ;
            RECT 0.000 26.520 0.160 26.640 ;
            RECT 140.880 26.520 142.300 26.640 ;
            RECT 348.800 26.520 350.680 26.640 ;
            RECT 360.160 26.520 360.320 26.640 ;
            RECT 0.000 26.640 142.300 27.000 ;
            RECT 348.800 26.640 360.320 27.000 ;
            RECT 0.000 27.000 2.880 27.320 ;
            RECT 140.880 27.000 142.300 27.320 ;
            RECT 348.800 27.000 350.680 27.320 ;
            RECT 357.440 27.000 360.320 27.320 ;
            RECT 0.000 27.320 142.300 27.680 ;
            RECT 348.800 27.320 360.320 27.680 ;
            RECT 0.000 27.680 0.160 28.000 ;
            RECT 140.880 27.680 142.300 28.000 ;
            RECT 348.800 27.680 350.680 28.000 ;
            RECT 360.160 27.680 360.320 28.000 ;
            RECT 0.000 28.000 142.300 28.320 ;
            RECT 348.800 28.000 360.320 28.320 ;
            RECT 0.000 28.320 360.320 28.360 ;
            RECT 0.000 28.360 2.880 28.680 ;
            RECT 140.880 28.360 350.680 28.680 ;
            RECT 357.440 28.360 360.320 28.680 ;
            RECT 0.000 28.680 360.320 29.040 ;
            RECT 0.000 29.040 0.160 29.360 ;
            RECT 140.880 29.040 350.680 29.360 ;
            RECT 360.160 29.040 360.320 29.360 ;
            RECT 0.000 29.360 360.320 29.720 ;
            RECT 0.000 29.720 2.880 30.040 ;
            RECT 140.880 29.720 350.680 30.040 ;
            RECT 357.440 29.720 360.320 30.040 ;
            RECT 0.000 30.040 360.320 30.260 ;
            RECT 0.000 30.260 142.300 30.400 ;
            RECT 348.800 30.260 360.320 30.400 ;
            RECT 0.000 30.400 0.160 30.720 ;
            RECT 140.880 30.400 142.300 30.720 ;
            RECT 348.800 30.400 350.680 30.720 ;
            RECT 360.160 30.400 360.320 30.720 ;
            RECT 0.000 30.720 142.300 31.080 ;
            RECT 348.800 30.720 360.320 31.080 ;
            RECT 0.000 31.080 2.880 31.400 ;
            RECT 90.560 31.080 104.520 31.400 ;
            RECT 140.880 31.080 142.300 31.400 ;
            RECT 348.800 31.080 350.680 31.400 ;
            RECT 357.440 31.080 360.320 31.400 ;
            RECT 0.000 31.400 142.300 31.760 ;
            RECT 348.800 31.400 360.320 31.760 ;
            RECT 0.000 31.760 0.160 32.060 ;
            RECT 89.880 31.760 103.160 32.060 ;
            RECT 140.880 31.760 142.300 32.060 ;
            RECT 348.800 31.760 350.680 32.060 ;
            RECT 360.160 31.760 360.320 32.060 ;
            RECT 0.000 32.060 0.160 32.080 ;
            RECT 89.880 32.060 103.160 32.080 ;
            RECT 140.880 32.060 350.680 32.080 ;
            RECT 360.160 32.060 360.320 32.080 ;
            RECT 0.000 32.080 360.320 32.440 ;
            RECT 0.000 32.440 2.880 32.760 ;
            RECT 89.200 32.440 110.640 32.760 ;
            RECT 140.880 32.440 350.680 32.760 ;
            RECT 357.440 32.440 360.320 32.760 ;
            RECT 0.000 32.760 360.320 33.120 ;
            RECT 0.000 33.120 0.160 33.440 ;
            RECT 88.520 33.120 109.280 33.440 ;
            RECT 140.880 33.120 350.680 33.440 ;
            RECT 360.160 33.120 360.320 33.440 ;
            RECT 0.000 33.440 360.320 33.800 ;
            RECT 0.000 33.800 2.880 34.120 ;
            RECT 66.080 33.800 125.600 34.120 ;
            RECT 140.880 33.800 350.680 34.120 ;
            RECT 357.440 33.800 360.320 34.120 ;
            RECT 0.000 34.120 360.320 34.480 ;
            RECT 0.000 34.480 0.160 34.800 ;
            RECT 68.800 34.480 126.280 34.800 ;
            RECT 140.880 34.480 350.680 34.800 ;
            RECT 360.160 34.480 360.320 34.800 ;
            RECT 0.000 34.800 360.320 35.160 ;
            RECT 0.000 35.160 2.880 35.480 ;
            RECT 66.760 35.160 116.080 35.480 ;
            RECT 140.880 35.160 350.680 35.480 ;
            RECT 357.440 35.160 360.320 35.480 ;
            RECT 0.000 35.480 360.320 35.840 ;
            RECT 0.000 35.840 0.160 36.160 ;
            RECT 68.120 35.840 122.200 36.160 ;
            RECT 140.880 35.840 350.680 36.160 ;
            RECT 360.160 35.840 360.320 36.160 ;
            RECT 0.000 36.160 360.320 36.520 ;
            RECT 0.000 36.520 2.880 36.840 ;
            RECT 140.880 36.520 350.680 36.840 ;
            RECT 357.440 36.520 360.320 36.840 ;
            RECT 0.000 36.840 360.320 37.200 ;
            RECT 0.000 37.200 0.160 37.520 ;
            RECT 140.880 37.200 350.680 37.520 ;
            RECT 360.160 37.200 360.320 37.520 ;
            RECT 0.000 37.520 360.320 37.880 ;
            RECT 0.000 37.880 2.880 38.200 ;
            RECT 140.200 37.880 350.680 38.200 ;
            RECT 357.440 37.880 360.320 38.200 ;
            RECT 0.000 38.200 360.320 38.560 ;
            RECT 0.000 38.560 0.160 38.880 ;
            RECT 140.200 38.560 350.680 38.880 ;
            RECT 360.160 38.560 360.320 38.880 ;
            RECT 0.000 38.880 360.320 39.240 ;
            RECT 0.000 39.240 2.880 39.560 ;
            RECT 140.880 39.240 350.680 39.560 ;
            RECT 357.440 39.240 360.320 39.560 ;
            RECT 0.000 39.560 360.320 39.630 ;
            RECT 0.000 39.630 142.300 39.920 ;
            RECT 148.100 39.630 343.000 39.920 ;
            RECT 348.800 39.630 360.320 39.920 ;
            RECT 0.000 39.920 0.160 40.240 ;
            RECT 140.880 39.920 142.300 40.240 ;
            RECT 148.100 39.920 343.000 40.240 ;
            RECT 348.800 39.920 350.680 40.240 ;
            RECT 360.160 39.920 360.320 40.240 ;
            RECT 0.000 40.240 142.300 40.600 ;
            RECT 148.100 40.240 343.000 40.600 ;
            RECT 348.800 40.240 360.320 40.600 ;
            RECT 0.000 40.600 2.880 40.750 ;
            RECT 140.880 40.600 142.300 40.750 ;
            RECT 148.100 40.600 343.000 40.750 ;
            RECT 348.800 40.600 350.680 40.750 ;
            RECT 357.440 40.600 360.320 40.750 ;
            RECT 0.000 40.750 2.880 40.920 ;
            RECT 140.880 40.750 350.680 40.920 ;
            RECT 357.440 40.750 360.320 40.920 ;
            RECT 0.000 40.920 360.320 41.280 ;
            RECT 0.000 41.280 0.160 41.600 ;
            RECT 140.880 41.280 350.680 41.600 ;
            RECT 360.160 41.280 360.320 41.600 ;
            RECT 0.000 41.600 360.320 41.960 ;
            RECT 0.000 41.960 2.880 42.275 ;
            RECT 64.040 41.960 75.280 42.275 ;
            RECT 140.880 41.960 350.680 42.275 ;
            RECT 357.440 41.960 360.320 42.275 ;
            RECT 0.000 42.275 2.880 42.280 ;
            RECT 64.040 42.275 75.280 42.280 ;
            RECT 140.880 42.275 142.300 42.280 ;
            RECT 148.100 42.275 343.000 42.280 ;
            RECT 348.800 42.275 350.680 42.280 ;
            RECT 357.440 42.275 360.320 42.280 ;
            RECT 0.000 42.280 142.300 42.640 ;
            RECT 148.100 42.280 343.000 42.640 ;
            RECT 348.800 42.280 360.320 42.640 ;
            RECT 0.000 42.640 0.160 42.960 ;
            RECT 64.040 42.640 75.280 42.960 ;
            RECT 140.880 42.640 142.300 42.960 ;
            RECT 148.100 42.640 343.000 42.960 ;
            RECT 348.800 42.640 350.680 42.960 ;
            RECT 360.160 42.640 360.320 42.960 ;
            RECT 0.000 42.960 142.300 43.320 ;
            RECT 148.100 42.960 343.000 43.320 ;
            RECT 348.800 42.960 360.320 43.320 ;
            RECT 0.000 43.320 2.880 43.640 ;
            RECT 65.400 43.320 67.800 43.640 ;
            RECT 140.880 43.320 142.300 43.640 ;
            RECT 148.100 43.320 343.000 43.640 ;
            RECT 348.800 43.320 350.680 43.640 ;
            RECT 357.440 43.320 360.320 43.640 ;
            RECT 0.000 43.640 142.300 43.645 ;
            RECT 148.100 43.640 343.000 43.645 ;
            RECT 348.800 43.640 360.320 43.645 ;
            RECT 0.000 43.645 360.320 44.000 ;
            RECT 0.000 44.000 0.160 44.320 ;
            RECT 65.400 44.000 71.200 44.320 ;
            RECT 79.000 44.000 81.400 44.320 ;
            RECT 140.880 44.000 350.680 44.320 ;
            RECT 360.160 44.000 360.320 44.320 ;
            RECT 0.000 44.320 360.320 44.680 ;
            RECT 0.000 44.680 2.880 45.000 ;
            RECT 66.760 44.680 71.200 45.000 ;
            RECT 79.000 44.680 81.400 45.000 ;
            RECT 140.880 44.680 350.680 45.000 ;
            RECT 357.440 44.680 360.320 45.000 ;
            RECT 0.000 45.000 360.320 45.360 ;
            RECT 0.000 45.360 0.160 45.420 ;
            RECT 66.760 45.360 70.520 45.420 ;
            RECT 140.880 45.360 350.680 45.420 ;
            RECT 360.160 45.360 360.320 45.420 ;
            RECT 0.000 45.420 0.160 45.680 ;
            RECT 66.760 45.420 70.520 45.680 ;
            RECT 140.880 45.420 142.300 45.680 ;
            RECT 148.100 45.420 343.000 45.680 ;
            RECT 348.800 45.420 350.680 45.680 ;
            RECT 360.160 45.420 360.320 45.680 ;
            RECT 0.000 45.680 142.300 46.040 ;
            RECT 148.100 45.680 343.000 46.040 ;
            RECT 348.800 45.680 360.320 46.040 ;
            RECT 0.000 46.040 2.880 46.360 ;
            RECT 66.760 46.040 70.520 46.360 ;
            RECT 140.880 46.040 350.680 46.360 ;
            RECT 357.440 46.040 360.320 46.360 ;
            RECT 0.000 46.360 360.320 46.720 ;
            RECT 0.000 46.720 0.160 47.040 ;
            RECT 117.080 46.720 123.560 47.040 ;
            RECT 140.880 46.720 350.680 47.040 ;
            RECT 360.160 46.720 360.320 47.040 ;
            RECT 0.000 47.040 360.320 47.100 ;
            RECT 0.000 47.100 117.805 47.315 ;
            RECT 118.915 47.100 121.185 47.315 ;
            RECT 123.105 47.100 360.320 47.315 ;
            RECT 0.000 47.315 117.805 47.400 ;
            RECT 118.915 47.315 121.185 47.400 ;
            RECT 123.105 47.315 142.300 47.400 ;
            RECT 148.100 47.315 343.000 47.400 ;
            RECT 348.800 47.315 360.320 47.400 ;
            RECT 0.000 47.400 2.880 47.720 ;
            RECT 73.560 47.400 82.080 47.720 ;
            RECT 117.080 47.400 117.805 47.720 ;
            RECT 118.915 47.400 121.185 47.720 ;
            RECT 123.105 47.400 123.560 47.720 ;
            RECT 140.880 47.400 142.300 47.720 ;
            RECT 148.100 47.400 343.000 47.720 ;
            RECT 348.800 47.400 350.680 47.720 ;
            RECT 357.440 47.400 360.320 47.720 ;
            RECT 0.000 47.720 117.805 48.080 ;
            RECT 118.915 47.720 121.185 48.080 ;
            RECT 123.105 47.720 142.300 48.080 ;
            RECT 148.100 47.720 343.000 48.080 ;
            RECT 348.800 47.720 360.320 48.080 ;
            RECT 0.000 48.080 0.160 48.400 ;
            RECT 73.560 48.080 82.080 48.400 ;
            RECT 117.080 48.080 117.805 48.400 ;
            RECT 118.915 48.080 121.185 48.400 ;
            RECT 123.105 48.080 142.300 48.400 ;
            RECT 148.100 48.080 343.000 48.400 ;
            RECT 348.800 48.080 350.680 48.400 ;
            RECT 360.160 48.080 360.320 48.400 ;
            RECT 0.000 48.400 117.805 48.685 ;
            RECT 118.915 48.400 121.185 48.685 ;
            RECT 123.105 48.400 142.300 48.685 ;
            RECT 148.100 48.400 343.000 48.685 ;
            RECT 348.800 48.400 360.320 48.685 ;
            RECT 0.000 48.685 117.805 48.760 ;
            RECT 118.915 48.685 121.185 48.760 ;
            RECT 123.105 48.685 360.320 48.760 ;
            RECT 0.000 48.760 2.880 49.080 ;
            RECT 68.800 48.760 75.280 49.080 ;
            RECT 117.080 48.760 117.805 49.080 ;
            RECT 118.915 48.760 121.185 49.080 ;
            RECT 123.105 48.760 350.680 49.080 ;
            RECT 357.440 48.760 360.320 49.080 ;
            RECT 0.000 49.080 117.805 49.440 ;
            RECT 118.915 49.080 121.185 49.440 ;
            RECT 123.105 49.080 360.320 49.440 ;
            RECT 0.000 49.440 0.160 49.760 ;
            RECT 66.080 49.440 75.280 49.760 ;
            RECT 117.080 49.440 117.805 49.760 ;
            RECT 118.915 49.440 121.185 49.760 ;
            RECT 123.105 49.440 123.560 49.760 ;
            RECT 140.880 49.440 350.680 49.760 ;
            RECT 360.160 49.440 360.320 49.760 ;
            RECT 0.000 49.760 117.805 50.120 ;
            RECT 118.915 49.760 121.185 50.120 ;
            RECT 123.105 49.760 360.320 50.120 ;
            RECT 0.000 50.120 2.880 50.440 ;
            RECT 66.080 50.120 75.280 50.440 ;
            RECT 87.160 50.120 114.040 50.440 ;
            RECT 117.080 50.120 117.805 50.440 ;
            RECT 118.915 50.120 121.185 50.440 ;
            RECT 123.105 50.120 123.560 50.440 ;
            RECT 140.880 50.120 350.680 50.440 ;
            RECT 357.440 50.120 360.320 50.440 ;
            RECT 0.000 50.440 117.805 50.470 ;
            RECT 118.915 50.440 121.185 50.470 ;
            RECT 123.105 50.440 360.320 50.470 ;
            RECT 0.000 50.470 117.805 50.680 ;
            RECT 118.915 50.470 121.185 50.680 ;
            RECT 123.105 50.470 142.300 50.680 ;
            RECT 148.100 50.470 343.000 50.680 ;
            RECT 348.800 50.470 360.320 50.680 ;
            RECT 0.000 50.680 142.300 50.800 ;
            RECT 148.100 50.680 343.000 50.800 ;
            RECT 348.800 50.680 360.320 50.800 ;
            RECT 0.000 50.800 0.160 51.110 ;
            RECT 69.480 50.800 74.600 51.110 ;
            RECT 117.080 50.800 123.560 51.110 ;
            RECT 140.880 50.800 142.300 51.110 ;
            RECT 148.100 50.800 343.000 51.110 ;
            RECT 348.800 50.800 350.680 51.110 ;
            RECT 360.160 50.800 360.320 51.110 ;
            RECT 0.000 51.110 0.160 51.120 ;
            RECT 69.480 51.110 74.600 51.120 ;
            RECT 117.080 51.110 123.560 51.120 ;
            RECT 140.880 51.110 350.680 51.120 ;
            RECT 360.160 51.110 360.320 51.120 ;
            RECT 0.000 51.120 360.320 51.480 ;
            RECT 0.000 51.480 2.880 51.800 ;
            RECT 140.880 51.480 350.680 51.800 ;
            RECT 357.440 51.480 360.320 51.800 ;
            RECT 0.000 51.800 360.320 52.160 ;
            RECT 0.000 52.160 0.160 52.415 ;
            RECT 140.880 52.160 350.680 52.415 ;
            RECT 360.160 52.160 360.320 52.415 ;
            RECT 0.000 52.415 0.160 52.480 ;
            RECT 140.880 52.415 142.300 52.480 ;
            RECT 148.100 52.415 343.000 52.480 ;
            RECT 348.800 52.415 350.680 52.480 ;
            RECT 360.160 52.415 360.320 52.480 ;
            RECT 0.000 52.480 142.300 52.840 ;
            RECT 148.100 52.480 343.000 52.840 ;
            RECT 348.800 52.480 360.320 52.840 ;
            RECT 0.000 52.840 2.880 53.160 ;
            RECT 65.400 52.840 75.280 53.160 ;
            RECT 140.880 52.840 142.300 53.160 ;
            RECT 148.100 52.840 343.000 53.160 ;
            RECT 348.800 52.840 350.680 53.160 ;
            RECT 357.440 52.840 360.320 53.160 ;
            RECT 0.000 53.160 142.300 53.520 ;
            RECT 148.100 53.160 343.000 53.520 ;
            RECT 348.800 53.160 360.320 53.520 ;
            RECT 0.000 53.520 0.160 53.835 ;
            RECT 65.400 53.520 75.280 53.835 ;
            RECT 140.880 53.520 142.300 53.835 ;
            RECT 148.100 53.520 343.000 53.835 ;
            RECT 348.800 53.520 350.680 53.835 ;
            RECT 360.160 53.520 360.320 53.835 ;
            RECT 0.000 53.835 0.160 53.840 ;
            RECT 65.400 53.835 75.280 53.840 ;
            RECT 140.880 53.835 350.680 53.840 ;
            RECT 360.160 53.835 360.320 53.840 ;
            RECT 0.000 53.840 360.320 54.200 ;
            RECT 0.000 54.200 2.880 54.520 ;
            RECT 73.560 54.200 81.400 54.520 ;
            RECT 140.880 54.200 350.680 54.520 ;
            RECT 357.440 54.200 360.320 54.520 ;
            RECT 0.000 54.520 360.320 54.880 ;
            RECT 0.000 54.880 0.160 55.200 ;
            RECT 72.200 54.880 81.400 55.200 ;
            RECT 140.880 54.880 350.680 55.200 ;
            RECT 360.160 54.880 360.320 55.200 ;
            RECT 0.000 55.200 360.320 55.560 ;
            RECT 0.000 55.560 2.880 55.640 ;
            RECT 72.200 55.560 75.280 55.640 ;
            RECT 140.880 55.560 350.680 55.640 ;
            RECT 357.440 55.560 360.320 55.640 ;
            RECT 0.000 55.640 2.880 55.880 ;
            RECT 72.200 55.640 75.280 55.880 ;
            RECT 140.880 55.640 142.300 55.880 ;
            RECT 148.100 55.640 343.000 55.880 ;
            RECT 348.800 55.640 350.680 55.880 ;
            RECT 357.440 55.640 360.320 55.880 ;
            RECT 0.000 55.880 142.300 56.240 ;
            RECT 148.100 55.880 343.000 56.240 ;
            RECT 348.800 55.880 360.320 56.240 ;
            RECT 0.000 56.240 0.160 56.280 ;
            RECT 99.400 56.240 122.880 56.280 ;
            RECT 140.880 56.240 142.300 56.280 ;
            RECT 148.100 56.240 343.000 56.280 ;
            RECT 348.800 56.240 350.680 56.280 ;
            RECT 360.160 56.240 360.320 56.280 ;
            RECT 0.000 56.280 0.160 56.560 ;
            RECT 99.400 56.280 122.880 56.560 ;
            RECT 140.880 56.280 350.680 56.560 ;
            RECT 360.160 56.280 360.320 56.560 ;
            RECT 0.000 56.560 360.320 56.680 ;
            RECT 0.000 56.680 100.415 56.920 ;
            RECT 101.525 56.680 103.580 56.920 ;
            RECT 105.500 56.680 107.930 56.920 ;
            RECT 108.820 56.680 110.555 56.920 ;
            RECT 112.475 56.680 115.010 56.920 ;
            RECT 116.550 56.680 120.110 56.920 ;
            RECT 122.030 56.680 360.320 56.920 ;
            RECT 0.000 56.920 2.880 57.240 ;
            RECT 88.520 56.920 94.320 57.240 ;
            RECT 99.400 56.920 100.415 57.240 ;
            RECT 101.525 56.920 103.580 57.240 ;
            RECT 105.500 56.920 107.930 57.240 ;
            RECT 108.820 56.920 110.555 57.240 ;
            RECT 112.475 56.920 115.010 57.240 ;
            RECT 116.550 56.920 120.110 57.240 ;
            RECT 122.030 56.920 122.880 57.240 ;
            RECT 140.880 56.920 350.680 57.240 ;
            RECT 357.440 56.920 360.320 57.240 ;
            RECT 0.000 57.240 100.415 57.585 ;
            RECT 101.525 57.240 103.580 57.585 ;
            RECT 105.500 57.240 107.930 57.585 ;
            RECT 108.820 57.240 110.555 57.585 ;
            RECT 112.475 57.240 115.010 57.585 ;
            RECT 116.550 57.240 120.110 57.585 ;
            RECT 122.030 57.240 360.320 57.585 ;
            RECT 0.000 57.585 100.415 57.600 ;
            RECT 101.525 57.585 103.580 57.600 ;
            RECT 105.500 57.585 107.930 57.600 ;
            RECT 108.820 57.585 110.555 57.600 ;
            RECT 112.475 57.585 115.010 57.600 ;
            RECT 116.550 57.585 120.110 57.600 ;
            RECT 122.030 57.585 142.300 57.600 ;
            RECT 148.100 57.585 343.000 57.600 ;
            RECT 348.800 57.585 360.320 57.600 ;
            RECT 0.000 57.600 0.160 57.920 ;
            RECT 73.560 57.600 79.360 57.920 ;
            RECT 89.200 57.600 93.640 57.920 ;
            RECT 99.400 57.600 100.415 57.920 ;
            RECT 101.525 57.600 103.580 57.920 ;
            RECT 105.500 57.600 107.930 57.920 ;
            RECT 108.820 57.600 110.555 57.920 ;
            RECT 112.475 57.600 115.010 57.920 ;
            RECT 116.550 57.600 120.110 57.920 ;
            RECT 122.030 57.600 122.880 57.920 ;
            RECT 140.880 57.600 142.300 57.920 ;
            RECT 148.100 57.600 343.000 57.920 ;
            RECT 348.800 57.600 350.680 57.920 ;
            RECT 360.160 57.600 360.320 57.920 ;
            RECT 0.000 57.920 100.415 58.280 ;
            RECT 101.525 57.920 103.580 58.280 ;
            RECT 105.500 57.920 107.930 58.280 ;
            RECT 108.820 57.920 110.555 58.280 ;
            RECT 112.475 57.920 115.010 58.280 ;
            RECT 116.550 57.920 120.110 58.280 ;
            RECT 122.030 57.920 142.300 58.280 ;
            RECT 148.100 57.920 343.000 58.280 ;
            RECT 348.800 57.920 360.320 58.280 ;
            RECT 0.000 58.280 2.880 58.600 ;
            RECT 73.560 58.280 81.400 58.600 ;
            RECT 89.880 58.280 92.960 58.600 ;
            RECT 99.400 58.280 100.415 58.600 ;
            RECT 101.525 58.280 103.580 58.600 ;
            RECT 105.500 58.280 107.930 58.600 ;
            RECT 108.820 58.280 110.555 58.600 ;
            RECT 112.475 58.280 115.010 58.600 ;
            RECT 116.550 58.280 120.110 58.600 ;
            RECT 122.030 58.280 133.080 58.600 ;
            RECT 140.880 58.280 142.300 58.600 ;
            RECT 148.100 58.280 343.000 58.600 ;
            RECT 348.800 58.280 350.680 58.600 ;
            RECT 357.440 58.280 360.320 58.600 ;
            RECT 0.000 58.600 100.415 58.960 ;
            RECT 101.525 58.600 103.580 58.960 ;
            RECT 105.500 58.600 107.930 58.960 ;
            RECT 108.820 58.600 110.555 58.960 ;
            RECT 112.475 58.600 115.010 58.960 ;
            RECT 116.550 58.600 120.110 58.960 ;
            RECT 122.030 58.600 142.300 58.960 ;
            RECT 148.100 58.600 343.000 58.960 ;
            RECT 348.800 58.600 360.320 58.960 ;
            RECT 0.000 58.960 0.160 59.005 ;
            RECT 76.280 58.960 81.400 59.005 ;
            RECT 90.560 58.960 92.960 59.005 ;
            RECT 99.400 58.960 100.415 59.005 ;
            RECT 101.525 58.960 103.580 59.005 ;
            RECT 105.500 58.960 107.930 59.005 ;
            RECT 108.820 58.960 110.555 59.005 ;
            RECT 112.475 58.960 115.010 59.005 ;
            RECT 116.550 58.960 120.110 59.005 ;
            RECT 122.030 58.960 133.080 59.005 ;
            RECT 140.880 58.960 142.300 59.005 ;
            RECT 148.100 58.960 343.000 59.005 ;
            RECT 348.800 58.960 350.680 59.005 ;
            RECT 360.160 58.960 360.320 59.005 ;
            RECT 0.000 59.005 0.160 59.280 ;
            RECT 76.280 59.005 81.400 59.280 ;
            RECT 90.560 59.005 92.960 59.280 ;
            RECT 99.400 59.005 100.415 59.280 ;
            RECT 101.525 59.005 103.580 59.280 ;
            RECT 105.500 59.005 107.930 59.280 ;
            RECT 108.820 59.005 110.555 59.280 ;
            RECT 112.475 59.005 115.010 59.280 ;
            RECT 116.550 59.005 120.110 59.280 ;
            RECT 122.030 59.005 133.080 59.280 ;
            RECT 140.880 59.005 350.680 59.280 ;
            RECT 360.160 59.005 360.320 59.280 ;
            RECT 0.000 59.280 100.415 59.640 ;
            RECT 101.525 59.280 103.580 59.640 ;
            RECT 105.500 59.280 107.930 59.640 ;
            RECT 108.820 59.280 110.555 59.640 ;
            RECT 112.475 59.280 115.010 59.640 ;
            RECT 116.550 59.280 120.110 59.640 ;
            RECT 122.030 59.280 360.320 59.640 ;
            RECT 0.000 59.640 2.880 59.960 ;
            RECT 70.160 59.640 75.280 59.960 ;
            RECT 99.400 59.640 100.415 59.960 ;
            RECT 101.525 59.640 103.580 59.960 ;
            RECT 105.500 59.640 107.930 59.960 ;
            RECT 108.820 59.640 110.555 59.960 ;
            RECT 112.475 59.640 115.010 59.960 ;
            RECT 116.550 59.640 120.110 59.960 ;
            RECT 122.030 59.640 131.720 59.960 ;
            RECT 140.880 59.640 350.680 59.960 ;
            RECT 357.440 59.640 360.320 59.960 ;
            RECT 0.000 59.960 100.415 60.320 ;
            RECT 101.525 59.960 103.580 60.320 ;
            RECT 105.500 59.960 107.930 60.320 ;
            RECT 108.820 59.960 110.555 60.320 ;
            RECT 112.475 59.960 115.010 60.320 ;
            RECT 116.550 59.960 120.110 60.320 ;
            RECT 122.030 59.960 360.320 60.320 ;
            RECT 0.000 60.320 0.160 60.640 ;
            RECT 70.160 60.320 75.280 60.640 ;
            RECT 99.400 60.320 100.415 60.640 ;
            RECT 101.525 60.320 103.580 60.640 ;
            RECT 105.500 60.320 107.930 60.640 ;
            RECT 108.820 60.320 110.555 60.640 ;
            RECT 112.475 60.320 115.010 60.640 ;
            RECT 116.550 60.320 120.110 60.640 ;
            RECT 122.030 60.320 133.080 60.640 ;
            RECT 140.880 60.320 350.680 60.640 ;
            RECT 360.160 60.320 360.320 60.640 ;
            RECT 0.000 60.640 100.415 61.000 ;
            RECT 101.525 60.640 103.580 61.000 ;
            RECT 105.500 60.640 107.930 61.000 ;
            RECT 108.820 60.640 110.555 61.000 ;
            RECT 112.475 60.640 115.010 61.000 ;
            RECT 116.550 60.640 120.110 61.000 ;
            RECT 122.030 60.640 360.320 61.000 ;
            RECT 0.000 61.000 2.880 61.320 ;
            RECT 72.200 61.000 75.280 61.320 ;
            RECT 99.400 61.000 100.415 61.320 ;
            RECT 101.525 61.000 103.580 61.320 ;
            RECT 105.500 61.000 107.930 61.320 ;
            RECT 108.820 61.000 110.555 61.320 ;
            RECT 112.475 61.000 115.010 61.320 ;
            RECT 116.550 61.000 120.110 61.320 ;
            RECT 122.030 61.000 133.080 61.320 ;
            RECT 140.880 61.000 350.680 61.320 ;
            RECT 357.440 61.000 360.320 61.320 ;
            RECT 0.000 61.320 100.415 61.680 ;
            RECT 101.525 61.320 103.580 61.680 ;
            RECT 105.500 61.320 107.930 61.680 ;
            RECT 108.820 61.320 110.555 61.680 ;
            RECT 112.475 61.320 115.010 61.680 ;
            RECT 116.550 61.320 120.110 61.680 ;
            RECT 122.030 61.320 360.320 61.680 ;
            RECT 0.000 61.680 0.160 62.000 ;
            RECT 99.400 61.680 100.415 62.000 ;
            RECT 101.525 61.680 103.580 62.000 ;
            RECT 105.500 61.680 107.930 62.000 ;
            RECT 108.820 61.680 110.555 62.000 ;
            RECT 112.475 61.680 115.010 62.000 ;
            RECT 116.550 61.680 120.110 62.000 ;
            RECT 122.030 61.680 133.080 62.000 ;
            RECT 140.880 61.680 350.680 62.000 ;
            RECT 360.160 61.680 360.320 62.000 ;
            RECT 0.000 62.000 100.415 62.360 ;
            RECT 101.525 62.000 103.580 62.360 ;
            RECT 105.500 62.000 107.930 62.360 ;
            RECT 108.820 62.000 110.555 62.360 ;
            RECT 112.475 62.000 115.010 62.360 ;
            RECT 116.550 62.000 120.110 62.360 ;
            RECT 122.030 62.000 360.320 62.360 ;
            RECT 0.000 62.360 2.880 62.680 ;
            RECT 99.400 62.360 100.415 62.680 ;
            RECT 101.525 62.360 103.580 62.680 ;
            RECT 105.500 62.360 107.930 62.680 ;
            RECT 108.820 62.360 110.555 62.680 ;
            RECT 112.475 62.360 115.010 62.680 ;
            RECT 116.550 62.360 120.110 62.680 ;
            RECT 122.030 62.360 133.080 62.680 ;
            RECT 140.880 62.360 350.680 62.680 ;
            RECT 357.440 62.360 360.320 62.680 ;
            RECT 0.000 62.680 100.415 63.040 ;
            RECT 101.525 62.680 103.580 63.040 ;
            RECT 105.500 62.680 107.930 63.040 ;
            RECT 108.820 62.680 110.555 63.040 ;
            RECT 112.475 62.680 115.010 63.040 ;
            RECT 116.550 62.680 120.110 63.040 ;
            RECT 122.030 62.680 360.320 63.040 ;
            RECT 0.000 63.040 0.160 63.360 ;
            RECT 64.040 63.040 86.840 63.360 ;
            RECT 99.400 63.040 100.415 63.360 ;
            RECT 101.525 63.040 103.580 63.360 ;
            RECT 105.500 63.040 107.930 63.360 ;
            RECT 108.820 63.040 110.555 63.360 ;
            RECT 112.475 63.040 115.010 63.360 ;
            RECT 116.550 63.040 120.110 63.360 ;
            RECT 122.030 63.040 131.720 63.360 ;
            RECT 140.880 63.040 350.680 63.360 ;
            RECT 360.160 63.040 360.320 63.360 ;
            RECT 0.000 63.360 100.415 63.720 ;
            RECT 101.525 63.360 103.580 63.720 ;
            RECT 105.500 63.360 107.930 63.720 ;
            RECT 108.820 63.360 110.555 63.720 ;
            RECT 112.475 63.360 115.010 63.720 ;
            RECT 116.550 63.360 120.110 63.720 ;
            RECT 122.030 63.360 360.320 63.720 ;
            RECT 0.000 63.720 2.880 64.040 ;
            RECT 64.040 63.720 86.840 64.040 ;
            RECT 99.400 63.720 100.415 64.040 ;
            RECT 101.525 63.720 103.580 64.040 ;
            RECT 105.500 63.720 107.930 64.040 ;
            RECT 108.820 63.720 110.555 64.040 ;
            RECT 112.475 63.720 115.010 64.040 ;
            RECT 116.550 63.720 120.110 64.040 ;
            RECT 122.030 63.720 133.080 64.040 ;
            RECT 140.880 63.720 350.680 64.040 ;
            RECT 357.440 63.720 360.320 64.040 ;
            RECT 0.000 64.040 100.415 64.400 ;
            RECT 101.525 64.040 103.580 64.400 ;
            RECT 105.500 64.040 107.930 64.400 ;
            RECT 108.820 64.040 110.555 64.400 ;
            RECT 112.475 64.040 115.010 64.400 ;
            RECT 116.550 64.040 120.110 64.400 ;
            RECT 122.030 64.040 360.320 64.400 ;
            RECT 0.000 64.400 0.160 64.720 ;
            RECT 73.560 64.400 81.400 64.720 ;
            RECT 99.400 64.400 100.415 64.720 ;
            RECT 101.525 64.400 103.580 64.720 ;
            RECT 105.500 64.400 107.930 64.720 ;
            RECT 108.820 64.400 110.555 64.720 ;
            RECT 112.475 64.400 115.010 64.720 ;
            RECT 116.550 64.400 120.110 64.720 ;
            RECT 122.030 64.400 133.080 64.720 ;
            RECT 140.880 64.400 350.680 64.720 ;
            RECT 360.160 64.400 360.320 64.720 ;
            RECT 0.000 64.720 100.415 65.080 ;
            RECT 101.525 64.720 103.580 65.080 ;
            RECT 105.500 64.720 107.930 65.080 ;
            RECT 108.820 64.720 110.555 65.080 ;
            RECT 112.475 64.720 115.010 65.080 ;
            RECT 116.550 64.720 120.110 65.080 ;
            RECT 122.030 64.720 360.320 65.080 ;
            RECT 0.000 65.080 2.880 65.400 ;
            RECT 82.400 65.080 88.200 65.400 ;
            RECT 99.400 65.080 100.415 65.400 ;
            RECT 101.525 65.080 103.580 65.400 ;
            RECT 105.500 65.080 107.930 65.400 ;
            RECT 108.820 65.080 110.555 65.400 ;
            RECT 112.475 65.080 115.010 65.400 ;
            RECT 116.550 65.080 120.110 65.400 ;
            RECT 122.030 65.080 131.720 65.400 ;
            RECT 140.880 65.080 350.680 65.400 ;
            RECT 357.440 65.080 360.320 65.400 ;
            RECT 0.000 65.400 100.415 65.760 ;
            RECT 101.525 65.400 103.580 65.760 ;
            RECT 105.500 65.400 107.930 65.760 ;
            RECT 108.820 65.400 110.555 65.760 ;
            RECT 112.475 65.400 115.010 65.760 ;
            RECT 116.550 65.400 120.110 65.760 ;
            RECT 122.030 65.400 360.320 65.760 ;
            RECT 0.000 65.760 0.160 65.770 ;
            RECT 72.200 65.760 75.280 65.770 ;
            RECT 82.400 65.760 88.880 65.770 ;
            RECT 99.400 65.760 100.415 65.770 ;
            RECT 101.525 65.760 103.580 65.770 ;
            RECT 105.500 65.760 107.930 65.770 ;
            RECT 108.820 65.760 110.555 65.770 ;
            RECT 112.475 65.760 115.010 65.770 ;
            RECT 116.550 65.760 120.110 65.770 ;
            RECT 122.030 65.760 122.880 65.770 ;
            RECT 140.880 65.760 350.680 65.770 ;
            RECT 360.160 65.760 360.320 65.770 ;
            RECT 0.000 65.770 0.160 66.080 ;
            RECT 72.200 65.770 75.280 66.080 ;
            RECT 82.400 65.770 88.880 66.080 ;
            RECT 99.400 65.770 100.415 66.080 ;
            RECT 101.525 65.770 103.580 66.080 ;
            RECT 105.500 65.770 107.930 66.080 ;
            RECT 108.820 65.770 110.555 66.080 ;
            RECT 112.475 65.770 115.010 66.080 ;
            RECT 116.550 65.770 120.110 66.080 ;
            RECT 122.030 65.770 122.880 66.080 ;
            RECT 140.880 65.770 142.300 66.080 ;
            RECT 348.800 65.770 350.680 66.080 ;
            RECT 360.160 65.770 360.320 66.080 ;
            RECT 0.000 66.080 100.415 66.440 ;
            RECT 101.525 66.080 103.580 66.440 ;
            RECT 105.500 66.080 107.930 66.440 ;
            RECT 108.820 66.080 110.555 66.440 ;
            RECT 112.475 66.080 115.010 66.440 ;
            RECT 116.550 66.080 120.110 66.440 ;
            RECT 122.030 66.080 142.300 66.440 ;
            RECT 348.800 66.080 360.320 66.440 ;
            RECT 0.000 66.440 2.880 66.760 ;
            RECT 72.200 66.440 75.280 66.760 ;
            RECT 85.120 66.440 88.880 66.760 ;
            RECT 99.400 66.440 100.415 66.760 ;
            RECT 101.525 66.440 103.580 66.760 ;
            RECT 105.500 66.440 107.930 66.760 ;
            RECT 108.820 66.440 110.555 66.760 ;
            RECT 112.475 66.440 115.010 66.760 ;
            RECT 116.550 66.440 120.110 66.760 ;
            RECT 122.030 66.440 122.880 66.760 ;
            RECT 140.880 66.440 142.300 66.760 ;
            RECT 348.800 66.440 350.680 66.760 ;
            RECT 357.440 66.440 360.320 66.760 ;
            RECT 0.000 66.760 100.415 67.120 ;
            RECT 101.525 66.760 103.580 67.120 ;
            RECT 105.500 66.760 107.930 67.120 ;
            RECT 108.820 66.760 110.555 67.120 ;
            RECT 112.475 66.760 115.010 67.120 ;
            RECT 116.550 66.760 120.110 67.120 ;
            RECT 122.030 66.760 142.300 67.120 ;
            RECT 348.800 66.760 360.320 67.120 ;
            RECT 0.000 67.120 0.160 67.440 ;
            RECT 64.040 67.120 78.000 67.440 ;
            RECT 99.400 67.120 100.415 67.440 ;
            RECT 101.525 67.120 103.580 67.440 ;
            RECT 105.500 67.120 107.930 67.440 ;
            RECT 108.820 67.120 110.555 67.440 ;
            RECT 112.475 67.120 115.010 67.440 ;
            RECT 116.550 67.120 120.110 67.440 ;
            RECT 122.030 67.120 135.800 67.440 ;
            RECT 140.880 67.120 142.300 67.440 ;
            RECT 348.800 67.120 350.680 67.440 ;
            RECT 360.160 67.120 360.320 67.440 ;
            RECT 0.000 67.440 100.415 67.570 ;
            RECT 101.525 67.440 103.580 67.570 ;
            RECT 105.500 67.440 107.930 67.570 ;
            RECT 108.820 67.440 110.555 67.570 ;
            RECT 112.475 67.440 115.010 67.570 ;
            RECT 116.550 67.440 120.110 67.570 ;
            RECT 122.030 67.440 142.300 67.570 ;
            RECT 348.800 67.440 360.320 67.570 ;
            RECT 0.000 67.570 100.415 67.800 ;
            RECT 101.525 67.570 103.580 67.800 ;
            RECT 105.500 67.570 107.930 67.800 ;
            RECT 108.820 67.570 110.555 67.800 ;
            RECT 112.475 67.570 115.010 67.800 ;
            RECT 116.550 67.570 120.110 67.800 ;
            RECT 122.030 67.570 360.320 67.800 ;
            RECT 0.000 67.800 2.880 68.120 ;
            RECT 64.040 67.800 78.000 68.120 ;
            RECT 99.400 67.800 100.415 68.120 ;
            RECT 101.525 67.800 103.580 68.120 ;
            RECT 105.500 67.800 107.930 68.120 ;
            RECT 108.820 67.800 110.555 68.120 ;
            RECT 112.475 67.800 115.010 68.120 ;
            RECT 116.550 67.800 120.110 68.120 ;
            RECT 122.030 67.800 134.440 68.120 ;
            RECT 140.880 67.800 350.680 68.120 ;
            RECT 357.440 67.800 360.320 68.120 ;
            RECT 0.000 68.120 100.415 68.480 ;
            RECT 101.525 68.120 103.580 68.480 ;
            RECT 105.500 68.120 107.930 68.480 ;
            RECT 108.820 68.120 110.555 68.480 ;
            RECT 112.475 68.120 115.010 68.480 ;
            RECT 116.550 68.120 120.110 68.480 ;
            RECT 122.030 68.120 360.320 68.480 ;
            RECT 0.000 68.480 0.160 68.800 ;
            RECT 72.200 68.480 81.400 68.800 ;
            RECT 99.400 68.480 100.415 68.800 ;
            RECT 101.525 68.480 103.580 68.800 ;
            RECT 105.500 68.480 107.930 68.800 ;
            RECT 108.820 68.480 110.555 68.800 ;
            RECT 112.475 68.480 115.010 68.800 ;
            RECT 116.550 68.480 120.110 68.800 ;
            RECT 122.030 68.480 135.800 68.800 ;
            RECT 140.880 68.480 350.680 68.800 ;
            RECT 360.160 68.480 360.320 68.800 ;
            RECT 0.000 68.800 100.415 69.160 ;
            RECT 101.525 68.800 103.580 69.160 ;
            RECT 105.500 68.800 107.930 69.160 ;
            RECT 108.820 68.800 110.555 69.160 ;
            RECT 112.475 68.800 115.010 69.160 ;
            RECT 116.550 68.800 120.110 69.160 ;
            RECT 122.030 68.800 360.320 69.160 ;
            RECT 0.000 69.160 2.880 69.480 ;
            RECT 72.200 69.160 81.400 69.480 ;
            RECT 99.400 69.160 100.415 69.480 ;
            RECT 101.525 69.160 103.580 69.480 ;
            RECT 105.500 69.160 107.930 69.480 ;
            RECT 108.820 69.160 110.555 69.480 ;
            RECT 112.475 69.160 115.010 69.480 ;
            RECT 116.550 69.160 120.110 69.480 ;
            RECT 122.030 69.160 135.800 69.480 ;
            RECT 140.880 69.160 350.680 69.480 ;
            RECT 357.440 69.160 360.320 69.480 ;
            RECT 0.000 69.480 100.415 69.510 ;
            RECT 101.525 69.480 103.580 69.510 ;
            RECT 105.500 69.480 107.930 69.510 ;
            RECT 108.820 69.480 110.555 69.510 ;
            RECT 112.475 69.480 115.010 69.510 ;
            RECT 116.550 69.480 120.110 69.510 ;
            RECT 122.030 69.480 360.320 69.510 ;
            RECT 0.000 69.510 100.415 69.840 ;
            RECT 101.525 69.510 103.580 69.840 ;
            RECT 105.500 69.510 107.930 69.840 ;
            RECT 108.820 69.510 110.555 69.840 ;
            RECT 112.475 69.510 115.010 69.840 ;
            RECT 116.550 69.510 120.110 69.840 ;
            RECT 122.030 69.510 142.300 69.840 ;
            RECT 348.800 69.510 360.320 69.840 ;
            RECT 0.000 69.840 0.160 70.160 ;
            RECT 70.840 69.840 74.600 70.160 ;
            RECT 99.400 69.840 100.415 70.160 ;
            RECT 101.525 69.840 103.580 70.160 ;
            RECT 105.500 69.840 107.930 70.160 ;
            RECT 108.820 69.840 110.555 70.160 ;
            RECT 112.475 69.840 115.010 70.160 ;
            RECT 116.550 69.840 120.110 70.160 ;
            RECT 122.030 69.840 134.440 70.160 ;
            RECT 140.880 69.840 142.300 70.160 ;
            RECT 348.800 69.840 350.680 70.160 ;
            RECT 360.160 69.840 360.320 70.160 ;
            RECT 0.000 70.160 100.415 70.520 ;
            RECT 101.525 70.160 103.580 70.520 ;
            RECT 105.500 70.160 107.930 70.520 ;
            RECT 108.820 70.160 110.555 70.520 ;
            RECT 112.475 70.160 115.010 70.520 ;
            RECT 116.550 70.160 120.110 70.520 ;
            RECT 122.030 70.160 142.300 70.520 ;
            RECT 348.800 70.160 360.320 70.520 ;
            RECT 0.000 70.520 2.880 70.840 ;
            RECT 70.840 70.520 82.080 70.840 ;
            RECT 99.400 70.520 100.415 70.840 ;
            RECT 101.525 70.520 103.580 70.840 ;
            RECT 105.500 70.520 107.930 70.840 ;
            RECT 108.820 70.520 110.555 70.840 ;
            RECT 112.475 70.520 115.010 70.840 ;
            RECT 116.550 70.520 120.110 70.840 ;
            RECT 122.030 70.520 135.800 70.840 ;
            RECT 140.880 70.520 142.300 70.840 ;
            RECT 348.800 70.520 350.680 70.840 ;
            RECT 357.440 70.520 360.320 70.840 ;
            RECT 0.000 70.840 100.415 71.200 ;
            RECT 101.525 70.840 103.580 71.200 ;
            RECT 105.500 70.840 107.930 71.200 ;
            RECT 108.820 70.840 110.555 71.200 ;
            RECT 112.475 70.840 115.010 71.200 ;
            RECT 116.550 70.840 120.110 71.200 ;
            RECT 122.030 70.840 142.300 71.200 ;
            RECT 348.800 70.840 360.320 71.200 ;
            RECT 0.000 71.200 0.160 71.310 ;
            RECT 66.080 71.200 70.520 71.310 ;
            RECT 73.560 71.200 82.080 71.310 ;
            RECT 99.400 71.200 100.415 71.310 ;
            RECT 101.525 71.200 103.580 71.310 ;
            RECT 105.500 71.200 107.930 71.310 ;
            RECT 108.820 71.200 110.555 71.310 ;
            RECT 112.475 71.200 115.010 71.310 ;
            RECT 116.550 71.200 120.110 71.310 ;
            RECT 122.030 71.200 135.800 71.310 ;
            RECT 140.880 71.200 142.300 71.310 ;
            RECT 348.800 71.200 350.680 71.310 ;
            RECT 360.160 71.200 360.320 71.310 ;
            RECT 0.000 71.310 0.160 71.520 ;
            RECT 66.080 71.310 70.520 71.520 ;
            RECT 73.560 71.310 82.080 71.520 ;
            RECT 99.400 71.310 100.415 71.520 ;
            RECT 101.525 71.310 103.580 71.520 ;
            RECT 105.500 71.310 107.930 71.520 ;
            RECT 108.820 71.310 110.555 71.520 ;
            RECT 112.475 71.310 115.010 71.520 ;
            RECT 116.550 71.310 120.110 71.520 ;
            RECT 122.030 71.310 135.800 71.520 ;
            RECT 140.880 71.310 350.680 71.520 ;
            RECT 360.160 71.310 360.320 71.520 ;
            RECT 0.000 71.520 100.415 71.880 ;
            RECT 101.525 71.520 103.580 71.880 ;
            RECT 105.500 71.520 107.930 71.880 ;
            RECT 108.820 71.520 110.555 71.880 ;
            RECT 112.475 71.520 115.010 71.880 ;
            RECT 116.550 71.520 120.110 71.880 ;
            RECT 122.030 71.520 360.320 71.880 ;
            RECT 0.000 71.880 2.880 72.200 ;
            RECT 66.080 71.880 72.560 72.200 ;
            RECT 99.400 71.880 100.415 72.200 ;
            RECT 101.525 71.880 103.580 72.200 ;
            RECT 105.500 71.880 107.930 72.200 ;
            RECT 108.820 71.880 110.555 72.200 ;
            RECT 112.475 71.880 115.010 72.200 ;
            RECT 116.550 71.880 120.110 72.200 ;
            RECT 122.030 71.880 134.440 72.200 ;
            RECT 140.880 71.880 350.680 72.200 ;
            RECT 357.440 71.880 360.320 72.200 ;
            RECT 0.000 72.200 100.415 72.560 ;
            RECT 101.525 72.200 103.580 72.560 ;
            RECT 105.500 72.200 107.930 72.560 ;
            RECT 108.820 72.200 110.555 72.560 ;
            RECT 112.475 72.200 115.010 72.560 ;
            RECT 116.550 72.200 120.110 72.560 ;
            RECT 122.030 72.200 360.320 72.560 ;
            RECT 0.000 72.560 0.160 72.880 ;
            RECT 68.800 72.560 72.560 72.880 ;
            RECT 99.400 72.560 100.415 72.880 ;
            RECT 101.525 72.560 103.580 72.880 ;
            RECT 105.500 72.560 107.930 72.880 ;
            RECT 108.820 72.560 110.555 72.880 ;
            RECT 112.475 72.560 115.010 72.880 ;
            RECT 116.550 72.560 120.110 72.880 ;
            RECT 122.030 72.560 135.800 72.880 ;
            RECT 140.880 72.560 350.680 72.880 ;
            RECT 360.160 72.560 360.320 72.880 ;
            RECT 0.000 72.880 100.415 73.240 ;
            RECT 101.525 72.880 103.580 73.240 ;
            RECT 105.500 72.880 107.930 73.240 ;
            RECT 108.820 72.880 110.555 73.240 ;
            RECT 112.475 72.880 115.010 73.240 ;
            RECT 116.550 72.880 120.110 73.240 ;
            RECT 122.030 72.880 360.320 73.240 ;
            RECT 0.000 73.240 2.880 73.560 ;
            RECT 99.400 73.240 100.415 73.560 ;
            RECT 101.525 73.240 103.580 73.560 ;
            RECT 105.500 73.240 107.930 73.560 ;
            RECT 108.820 73.240 110.555 73.560 ;
            RECT 112.475 73.240 115.010 73.560 ;
            RECT 116.550 73.240 120.110 73.560 ;
            RECT 122.030 73.240 135.800 73.560 ;
            RECT 140.880 73.240 350.680 73.560 ;
            RECT 357.440 73.240 360.320 73.560 ;
            RECT 0.000 73.560 100.415 73.920 ;
            RECT 101.525 73.560 103.580 73.920 ;
            RECT 105.500 73.560 107.930 73.920 ;
            RECT 108.820 73.560 110.555 73.920 ;
            RECT 112.475 73.560 115.010 73.920 ;
            RECT 116.550 73.560 120.110 73.920 ;
            RECT 122.030 73.560 360.320 73.920 ;
            RECT 0.000 73.920 0.160 74.240 ;
            RECT 65.400 73.920 69.160 74.240 ;
            RECT 99.400 73.920 100.415 74.240 ;
            RECT 101.525 73.920 103.580 74.240 ;
            RECT 105.500 73.920 107.930 74.240 ;
            RECT 108.820 73.920 110.555 74.240 ;
            RECT 112.475 73.920 115.010 74.240 ;
            RECT 116.550 73.920 120.110 74.240 ;
            RECT 122.030 73.920 134.440 74.240 ;
            RECT 140.880 73.920 350.680 74.240 ;
            RECT 360.160 73.920 360.320 74.240 ;
            RECT 0.000 74.240 100.415 74.600 ;
            RECT 101.525 74.240 103.580 74.600 ;
            RECT 105.500 74.240 107.930 74.600 ;
            RECT 108.820 74.240 110.555 74.600 ;
            RECT 112.475 74.240 115.010 74.600 ;
            RECT 116.550 74.240 120.110 74.600 ;
            RECT 122.030 74.240 360.320 74.600 ;
            RECT 0.000 74.600 2.880 74.920 ;
            RECT 65.400 74.600 69.160 74.920 ;
            RECT 99.400 74.600 100.415 74.920 ;
            RECT 101.525 74.600 103.580 74.920 ;
            RECT 105.500 74.600 107.930 74.920 ;
            RECT 108.820 74.600 110.555 74.920 ;
            RECT 112.475 74.600 115.010 74.920 ;
            RECT 116.550 74.600 120.110 74.920 ;
            RECT 122.030 74.600 122.880 74.920 ;
            RECT 140.880 74.600 350.680 74.920 ;
            RECT 357.440 74.600 360.320 74.920 ;
            RECT 0.000 74.920 100.415 75.280 ;
            RECT 101.525 74.920 103.580 75.280 ;
            RECT 105.500 74.920 107.930 75.280 ;
            RECT 108.820 74.920 110.555 75.280 ;
            RECT 112.475 74.920 115.010 75.280 ;
            RECT 116.550 74.920 120.110 75.280 ;
            RECT 122.030 74.920 360.320 75.280 ;
            RECT 0.000 75.280 0.160 75.600 ;
            RECT 69.480 75.280 75.280 75.600 ;
            RECT 99.400 75.280 100.415 75.600 ;
            RECT 101.525 75.280 103.580 75.600 ;
            RECT 105.500 75.280 107.930 75.600 ;
            RECT 108.820 75.280 110.555 75.600 ;
            RECT 112.475 75.280 115.010 75.600 ;
            RECT 116.550 75.280 120.110 75.600 ;
            RECT 122.030 75.280 138.520 75.600 ;
            RECT 140.880 75.280 350.680 75.600 ;
            RECT 360.160 75.280 360.320 75.600 ;
            RECT 0.000 75.600 100.415 75.960 ;
            RECT 101.525 75.600 103.580 75.960 ;
            RECT 105.500 75.600 107.930 75.960 ;
            RECT 108.820 75.600 110.555 75.960 ;
            RECT 112.475 75.600 115.010 75.960 ;
            RECT 116.550 75.600 120.110 75.960 ;
            RECT 122.030 75.600 360.320 75.960 ;
            RECT 0.000 75.960 2.880 76.280 ;
            RECT 65.400 75.960 75.280 76.280 ;
            RECT 99.400 75.960 100.415 76.280 ;
            RECT 101.525 75.960 103.580 76.280 ;
            RECT 105.500 75.960 107.930 76.280 ;
            RECT 108.820 75.960 110.555 76.280 ;
            RECT 112.475 75.960 115.010 76.280 ;
            RECT 116.550 75.960 120.110 76.280 ;
            RECT 122.030 75.960 138.520 76.280 ;
            RECT 140.880 75.960 350.680 76.280 ;
            RECT 357.440 75.960 360.320 76.280 ;
            RECT 0.000 76.280 100.415 76.640 ;
            RECT 101.525 76.280 103.580 76.640 ;
            RECT 105.500 76.280 107.930 76.640 ;
            RECT 108.820 76.280 110.555 76.640 ;
            RECT 112.475 76.280 115.010 76.640 ;
            RECT 116.550 76.280 120.110 76.640 ;
            RECT 122.030 76.280 360.320 76.640 ;
            RECT 0.000 76.640 0.160 76.960 ;
            RECT 65.400 76.640 81.400 76.960 ;
            RECT 99.400 76.640 100.415 76.960 ;
            RECT 101.525 76.640 103.580 76.960 ;
            RECT 105.500 76.640 107.930 76.960 ;
            RECT 108.820 76.640 110.555 76.960 ;
            RECT 112.475 76.640 115.010 76.960 ;
            RECT 116.550 76.640 120.110 76.960 ;
            RECT 122.030 76.640 137.160 76.960 ;
            RECT 140.880 76.640 350.680 76.960 ;
            RECT 360.160 76.640 360.320 76.960 ;
            RECT 0.000 76.960 100.415 77.240 ;
            RECT 101.525 76.960 103.580 77.240 ;
            RECT 105.500 76.960 107.930 77.240 ;
            RECT 108.820 76.960 110.555 77.240 ;
            RECT 112.475 76.960 115.010 77.240 ;
            RECT 116.550 76.960 120.110 77.240 ;
            RECT 122.030 76.960 360.320 77.240 ;
            RECT 0.000 77.240 100.415 77.320 ;
            RECT 101.525 77.240 103.580 77.320 ;
            RECT 105.500 77.240 107.930 77.320 ;
            RECT 108.820 77.240 110.555 77.320 ;
            RECT 112.475 77.240 115.010 77.320 ;
            RECT 116.550 77.240 120.110 77.320 ;
            RECT 122.030 77.240 142.300 77.320 ;
            RECT 348.800 77.240 360.320 77.320 ;
            RECT 0.000 77.320 2.880 77.640 ;
            RECT 69.480 77.320 81.400 77.640 ;
            RECT 99.400 77.320 100.415 77.640 ;
            RECT 101.525 77.320 103.580 77.640 ;
            RECT 105.500 77.320 107.930 77.640 ;
            RECT 108.820 77.320 110.555 77.640 ;
            RECT 112.475 77.320 115.010 77.640 ;
            RECT 116.550 77.320 120.110 77.640 ;
            RECT 122.030 77.320 138.520 77.640 ;
            RECT 140.880 77.320 142.300 77.640 ;
            RECT 348.800 77.320 350.680 77.640 ;
            RECT 357.440 77.320 360.320 77.640 ;
            RECT 0.000 77.640 100.415 78.000 ;
            RECT 101.525 77.640 103.580 78.000 ;
            RECT 105.500 77.640 107.930 78.000 ;
            RECT 108.820 77.640 110.555 78.000 ;
            RECT 112.475 77.640 115.010 78.000 ;
            RECT 116.550 77.640 120.110 78.000 ;
            RECT 122.030 77.640 142.300 78.000 ;
            RECT 348.800 77.640 360.320 78.000 ;
            RECT 0.000 78.000 0.160 78.040 ;
            RECT 73.560 78.000 77.320 78.040 ;
            RECT 99.400 78.000 100.415 78.040 ;
            RECT 101.525 78.000 103.580 78.040 ;
            RECT 105.500 78.000 107.930 78.040 ;
            RECT 108.820 78.000 110.555 78.040 ;
            RECT 112.475 78.000 115.010 78.040 ;
            RECT 116.550 78.000 120.110 78.040 ;
            RECT 122.030 78.000 138.520 78.040 ;
            RECT 140.880 78.000 142.300 78.040 ;
            RECT 348.800 78.000 350.680 78.040 ;
            RECT 360.160 78.000 360.320 78.040 ;
            RECT 0.000 78.040 0.160 78.320 ;
            RECT 73.560 78.040 77.320 78.320 ;
            RECT 99.400 78.040 100.415 78.320 ;
            RECT 101.525 78.040 103.580 78.320 ;
            RECT 105.500 78.040 107.930 78.320 ;
            RECT 108.820 78.040 110.555 78.320 ;
            RECT 112.475 78.040 115.010 78.320 ;
            RECT 116.550 78.040 120.110 78.320 ;
            RECT 122.030 78.040 138.520 78.320 ;
            RECT 140.880 78.040 350.680 78.320 ;
            RECT 360.160 78.040 360.320 78.320 ;
            RECT 0.000 78.320 100.415 78.560 ;
            RECT 101.525 78.320 103.580 78.560 ;
            RECT 105.500 78.320 107.930 78.560 ;
            RECT 108.820 78.320 110.555 78.560 ;
            RECT 112.475 78.320 115.010 78.560 ;
            RECT 116.550 78.320 120.110 78.560 ;
            RECT 122.030 78.320 360.320 78.560 ;
            RECT 0.000 78.560 100.415 78.680 ;
            RECT 101.525 78.560 103.580 78.680 ;
            RECT 105.500 78.560 107.930 78.680 ;
            RECT 108.820 78.560 110.555 78.680 ;
            RECT 112.475 78.560 115.010 78.680 ;
            RECT 116.550 78.560 120.110 78.680 ;
            RECT 122.030 78.560 142.300 78.680 ;
            RECT 348.800 78.560 360.320 78.680 ;
            RECT 0.000 78.680 2.880 79.000 ;
            RECT 72.880 78.680 77.320 79.000 ;
            RECT 99.400 78.680 100.415 79.000 ;
            RECT 101.525 78.680 103.580 79.000 ;
            RECT 105.500 78.680 107.930 79.000 ;
            RECT 108.820 78.680 110.555 79.000 ;
            RECT 112.475 78.680 115.010 79.000 ;
            RECT 116.550 78.680 120.110 79.000 ;
            RECT 122.030 78.680 137.160 79.000 ;
            RECT 140.880 78.680 142.300 79.000 ;
            RECT 348.800 78.680 350.680 79.000 ;
            RECT 357.440 78.680 360.320 79.000 ;
            RECT 0.000 79.000 100.415 79.360 ;
            RECT 101.525 79.000 103.580 79.360 ;
            RECT 105.500 79.000 107.930 79.360 ;
            RECT 108.820 79.000 110.555 79.360 ;
            RECT 112.475 79.000 115.010 79.360 ;
            RECT 116.550 79.000 120.110 79.360 ;
            RECT 122.030 79.000 142.300 79.360 ;
            RECT 348.800 79.000 360.320 79.360 ;
            RECT 0.000 79.360 0.160 79.680 ;
            RECT 72.880 79.360 75.280 79.680 ;
            RECT 99.400 79.360 100.415 79.680 ;
            RECT 101.525 79.360 103.580 79.680 ;
            RECT 105.500 79.360 107.930 79.680 ;
            RECT 108.820 79.360 110.555 79.680 ;
            RECT 112.475 79.360 115.010 79.680 ;
            RECT 116.550 79.360 120.110 79.680 ;
            RECT 122.030 79.360 138.520 79.680 ;
            RECT 140.880 79.360 350.680 79.680 ;
            RECT 360.160 79.360 360.320 79.680 ;
            RECT 0.000 79.680 100.415 80.040 ;
            RECT 101.525 79.680 103.580 80.040 ;
            RECT 105.500 79.680 107.930 80.040 ;
            RECT 108.820 79.680 110.555 80.040 ;
            RECT 112.475 79.680 115.010 80.040 ;
            RECT 116.550 79.680 120.110 80.040 ;
            RECT 122.030 79.680 360.320 80.040 ;
            RECT 0.000 80.040 2.880 80.250 ;
            RECT 73.560 80.040 77.320 80.250 ;
            RECT 99.400 80.040 100.415 80.250 ;
            RECT 101.525 80.040 103.580 80.250 ;
            RECT 105.500 80.040 107.930 80.250 ;
            RECT 108.820 80.040 110.555 80.250 ;
            RECT 112.475 80.040 115.010 80.250 ;
            RECT 116.550 80.040 120.110 80.250 ;
            RECT 122.030 80.040 138.520 80.250 ;
            RECT 140.880 80.040 350.680 80.250 ;
            RECT 357.440 80.040 360.320 80.250 ;
            RECT 0.000 80.250 2.880 80.360 ;
            RECT 73.560 80.250 77.320 80.360 ;
            RECT 99.400 80.250 100.415 80.360 ;
            RECT 101.525 80.250 103.580 80.360 ;
            RECT 105.500 80.250 107.930 80.360 ;
            RECT 108.820 80.250 110.555 80.360 ;
            RECT 112.475 80.250 115.010 80.360 ;
            RECT 116.550 80.250 120.110 80.360 ;
            RECT 122.030 80.250 138.520 80.360 ;
            RECT 140.880 80.250 142.300 80.360 ;
            RECT 348.800 80.250 350.680 80.360 ;
            RECT 357.440 80.250 360.320 80.360 ;
            RECT 0.000 80.360 100.415 80.720 ;
            RECT 101.525 80.360 103.580 80.720 ;
            RECT 105.500 80.360 107.930 80.720 ;
            RECT 108.820 80.360 110.555 80.720 ;
            RECT 112.475 80.360 115.010 80.720 ;
            RECT 116.550 80.360 120.110 80.720 ;
            RECT 122.030 80.360 142.300 80.720 ;
            RECT 348.800 80.360 360.320 80.720 ;
            RECT 0.000 80.720 0.160 81.040 ;
            RECT 73.560 80.720 77.320 81.040 ;
            RECT 99.400 80.720 100.415 81.040 ;
            RECT 101.525 80.720 103.580 81.040 ;
            RECT 105.500 80.720 107.930 81.040 ;
            RECT 108.820 80.720 110.555 81.040 ;
            RECT 112.475 80.720 115.010 81.040 ;
            RECT 116.550 80.720 120.110 81.040 ;
            RECT 122.030 80.720 122.880 81.040 ;
            RECT 140.880 80.720 142.300 81.040 ;
            RECT 348.800 80.720 350.680 81.040 ;
            RECT 360.160 80.720 360.320 81.040 ;
            RECT 0.000 81.040 100.415 81.050 ;
            RECT 101.525 81.040 103.580 81.050 ;
            RECT 105.500 81.040 107.930 81.050 ;
            RECT 108.820 81.040 110.555 81.050 ;
            RECT 112.475 81.040 115.010 81.050 ;
            RECT 116.550 81.040 120.110 81.050 ;
            RECT 122.030 81.040 142.300 81.050 ;
            RECT 348.800 81.040 360.320 81.050 ;
            RECT 0.000 81.050 100.415 81.400 ;
            RECT 101.525 81.050 103.580 81.400 ;
            RECT 105.500 81.050 107.930 81.400 ;
            RECT 108.820 81.050 110.555 81.400 ;
            RECT 112.475 81.050 115.010 81.400 ;
            RECT 116.550 81.050 120.110 81.400 ;
            RECT 122.030 81.050 360.320 81.400 ;
            RECT 0.000 81.400 2.880 81.570 ;
            RECT 99.400 81.400 100.415 81.570 ;
            RECT 101.525 81.400 103.580 81.570 ;
            RECT 105.500 81.400 107.930 81.570 ;
            RECT 108.820 81.400 110.555 81.570 ;
            RECT 112.475 81.400 115.010 81.570 ;
            RECT 116.550 81.400 120.110 81.570 ;
            RECT 122.030 81.400 138.520 81.570 ;
            RECT 140.880 81.400 350.680 81.570 ;
            RECT 357.440 81.400 360.320 81.570 ;
            RECT 0.000 81.570 2.880 81.720 ;
            RECT 99.400 81.570 100.415 81.720 ;
            RECT 101.525 81.570 103.580 81.720 ;
            RECT 105.500 81.570 107.930 81.720 ;
            RECT 108.820 81.570 110.555 81.720 ;
            RECT 112.475 81.570 115.010 81.720 ;
            RECT 116.550 81.570 120.110 81.720 ;
            RECT 122.030 81.570 138.520 81.720 ;
            RECT 140.880 81.570 142.300 81.720 ;
            RECT 348.800 81.570 350.680 81.720 ;
            RECT 357.440 81.570 360.320 81.720 ;
            RECT 0.000 81.720 100.415 82.080 ;
            RECT 101.525 81.720 103.580 82.080 ;
            RECT 105.500 81.720 107.930 82.080 ;
            RECT 108.820 81.720 110.555 82.080 ;
            RECT 112.475 81.720 115.010 82.080 ;
            RECT 116.550 81.720 120.110 82.080 ;
            RECT 122.030 81.720 142.300 82.080 ;
            RECT 348.800 81.720 360.320 82.080 ;
            RECT 0.000 82.080 0.160 82.370 ;
            RECT 64.040 82.080 71.200 82.370 ;
            RECT 99.400 82.080 100.415 82.370 ;
            RECT 101.525 82.080 103.580 82.370 ;
            RECT 105.500 82.080 107.930 82.370 ;
            RECT 108.820 82.080 110.555 82.370 ;
            RECT 112.475 82.080 115.010 82.370 ;
            RECT 116.550 82.080 120.110 82.370 ;
            RECT 122.030 82.080 137.160 82.370 ;
            RECT 140.880 82.080 142.300 82.370 ;
            RECT 348.800 82.080 350.680 82.370 ;
            RECT 360.160 82.080 360.320 82.370 ;
            RECT 0.000 82.370 0.160 82.400 ;
            RECT 64.040 82.370 71.200 82.400 ;
            RECT 99.400 82.370 100.415 82.400 ;
            RECT 101.525 82.370 103.580 82.400 ;
            RECT 105.500 82.370 107.930 82.400 ;
            RECT 108.820 82.370 110.555 82.400 ;
            RECT 112.475 82.370 115.010 82.400 ;
            RECT 116.550 82.370 120.110 82.400 ;
            RECT 122.030 82.370 137.160 82.400 ;
            RECT 140.880 82.370 350.680 82.400 ;
            RECT 360.160 82.370 360.320 82.400 ;
            RECT 0.000 82.400 100.415 82.760 ;
            RECT 101.525 82.400 103.580 82.760 ;
            RECT 105.500 82.400 107.930 82.760 ;
            RECT 108.820 82.400 110.555 82.760 ;
            RECT 112.475 82.400 115.010 82.760 ;
            RECT 116.550 82.400 120.110 82.760 ;
            RECT 122.030 82.400 360.320 82.760 ;
            RECT 0.000 82.760 2.880 83.080 ;
            RECT 64.040 82.760 71.200 83.080 ;
            RECT 99.400 82.760 100.415 83.080 ;
            RECT 101.525 82.760 103.580 83.080 ;
            RECT 105.500 82.760 107.930 83.080 ;
            RECT 108.820 82.760 110.555 83.080 ;
            RECT 112.475 82.760 115.010 83.080 ;
            RECT 116.550 82.760 120.110 83.080 ;
            RECT 122.030 82.760 122.880 83.080 ;
            RECT 140.880 82.760 350.680 83.080 ;
            RECT 357.440 82.760 360.320 83.080 ;
            RECT 0.000 83.080 100.415 83.250 ;
            RECT 101.525 83.080 103.580 83.250 ;
            RECT 105.500 83.080 107.930 83.250 ;
            RECT 108.820 83.080 110.555 83.250 ;
            RECT 112.475 83.080 115.010 83.250 ;
            RECT 116.550 83.080 120.110 83.250 ;
            RECT 122.030 83.080 360.320 83.250 ;
            RECT 0.000 83.250 100.415 83.440 ;
            RECT 101.525 83.250 103.580 83.440 ;
            RECT 105.500 83.250 107.930 83.440 ;
            RECT 108.820 83.250 110.555 83.440 ;
            RECT 112.475 83.250 115.010 83.440 ;
            RECT 116.550 83.250 120.110 83.440 ;
            RECT 122.030 83.250 142.300 83.440 ;
            RECT 348.800 83.250 360.320 83.440 ;
            RECT 0.000 83.440 0.160 83.760 ;
            RECT 64.040 83.440 75.280 83.760 ;
            RECT 99.400 83.440 100.415 83.760 ;
            RECT 101.525 83.440 103.580 83.760 ;
            RECT 105.500 83.440 107.930 83.760 ;
            RECT 108.820 83.440 110.555 83.760 ;
            RECT 112.475 83.440 115.010 83.760 ;
            RECT 116.550 83.440 120.110 83.760 ;
            RECT 122.030 83.440 122.880 83.760 ;
            RECT 140.880 83.440 142.300 83.760 ;
            RECT 348.800 83.440 350.680 83.760 ;
            RECT 360.160 83.440 360.320 83.760 ;
            RECT 0.000 83.760 100.415 84.050 ;
            RECT 101.525 83.760 103.580 84.050 ;
            RECT 105.500 83.760 107.930 84.050 ;
            RECT 108.820 83.760 110.555 84.050 ;
            RECT 112.475 83.760 115.010 84.050 ;
            RECT 116.550 83.760 120.110 84.050 ;
            RECT 122.030 83.760 142.300 84.050 ;
            RECT 348.800 83.760 360.320 84.050 ;
            RECT 0.000 84.050 100.415 84.120 ;
            RECT 101.525 84.050 103.580 84.120 ;
            RECT 105.500 84.050 107.930 84.120 ;
            RECT 108.820 84.050 110.555 84.120 ;
            RECT 112.475 84.050 115.010 84.120 ;
            RECT 116.550 84.050 120.110 84.120 ;
            RECT 122.030 84.050 360.320 84.120 ;
            RECT 0.000 84.120 2.880 84.440 ;
            RECT 64.040 84.120 75.280 84.440 ;
            RECT 99.400 84.120 100.415 84.440 ;
            RECT 101.525 84.120 103.580 84.440 ;
            RECT 105.500 84.120 107.930 84.440 ;
            RECT 108.820 84.120 110.555 84.440 ;
            RECT 112.475 84.120 115.010 84.440 ;
            RECT 116.550 84.120 120.110 84.440 ;
            RECT 122.030 84.120 350.680 84.440 ;
            RECT 357.440 84.120 360.320 84.440 ;
            RECT 0.000 84.440 100.415 84.800 ;
            RECT 101.525 84.440 103.580 84.800 ;
            RECT 105.500 84.440 107.930 84.800 ;
            RECT 108.820 84.440 110.555 84.800 ;
            RECT 112.475 84.440 115.010 84.800 ;
            RECT 116.550 84.440 120.110 84.800 ;
            RECT 122.030 84.440 360.320 84.800 ;
            RECT 0.000 84.800 0.160 85.120 ;
            RECT 67.440 84.800 73.920 85.120 ;
            RECT 99.400 84.800 100.415 85.120 ;
            RECT 101.525 84.800 103.580 85.120 ;
            RECT 105.500 84.800 107.930 85.120 ;
            RECT 108.820 84.800 110.555 85.120 ;
            RECT 112.475 84.800 115.010 85.120 ;
            RECT 116.550 84.800 120.110 85.120 ;
            RECT 122.030 84.800 350.680 85.120 ;
            RECT 360.160 84.800 360.320 85.120 ;
            RECT 0.000 85.120 100.415 85.140 ;
            RECT 101.525 85.120 103.580 85.140 ;
            RECT 105.500 85.120 107.930 85.140 ;
            RECT 108.820 85.120 110.555 85.140 ;
            RECT 112.475 85.120 115.010 85.140 ;
            RECT 116.550 85.120 120.110 85.140 ;
            RECT 122.030 85.120 360.320 85.140 ;
            RECT 0.000 85.140 100.415 85.480 ;
            RECT 101.525 85.140 103.580 85.480 ;
            RECT 105.500 85.140 107.930 85.480 ;
            RECT 108.820 85.140 110.555 85.480 ;
            RECT 112.475 85.140 115.010 85.480 ;
            RECT 116.550 85.140 120.110 85.480 ;
            RECT 122.030 85.140 142.300 85.480 ;
            RECT 348.800 85.140 360.320 85.480 ;
            RECT 0.000 85.480 2.880 85.800 ;
            RECT 72.880 85.480 75.280 85.800 ;
            RECT 99.400 85.480 100.415 85.800 ;
            RECT 101.525 85.480 103.580 85.800 ;
            RECT 105.500 85.480 107.930 85.800 ;
            RECT 108.820 85.480 110.555 85.800 ;
            RECT 112.475 85.480 115.010 85.800 ;
            RECT 116.550 85.480 120.110 85.800 ;
            RECT 122.030 85.480 122.880 85.800 ;
            RECT 140.880 85.480 142.300 85.800 ;
            RECT 348.800 85.480 350.680 85.800 ;
            RECT 357.440 85.480 360.320 85.800 ;
            RECT 0.000 85.800 100.415 85.940 ;
            RECT 101.525 85.800 103.580 85.940 ;
            RECT 105.500 85.800 107.930 85.940 ;
            RECT 108.820 85.800 110.555 85.940 ;
            RECT 112.475 85.800 115.010 85.940 ;
            RECT 116.550 85.800 120.110 85.940 ;
            RECT 122.030 85.800 142.300 85.940 ;
            RECT 348.800 85.800 360.320 85.940 ;
            RECT 0.000 85.940 100.415 86.160 ;
            RECT 101.525 85.940 103.580 86.160 ;
            RECT 105.500 85.940 107.930 86.160 ;
            RECT 108.820 85.940 110.555 86.160 ;
            RECT 112.475 85.940 115.010 86.160 ;
            RECT 116.550 85.940 120.110 86.160 ;
            RECT 122.030 85.940 360.320 86.160 ;
            RECT 0.000 86.160 0.160 86.460 ;
            RECT 72.880 86.160 75.280 86.460 ;
            RECT 99.400 86.160 100.415 86.460 ;
            RECT 101.525 86.160 103.580 86.460 ;
            RECT 105.500 86.160 107.930 86.460 ;
            RECT 108.820 86.160 110.555 86.460 ;
            RECT 112.475 86.160 115.010 86.460 ;
            RECT 116.550 86.160 120.110 86.460 ;
            RECT 122.030 86.160 350.680 86.460 ;
            RECT 360.160 86.160 360.320 86.460 ;
            RECT 0.000 86.460 0.160 86.480 ;
            RECT 72.880 86.460 75.280 86.480 ;
            RECT 99.400 86.460 100.415 86.480 ;
            RECT 101.525 86.460 103.580 86.480 ;
            RECT 105.500 86.460 107.930 86.480 ;
            RECT 108.820 86.460 110.555 86.480 ;
            RECT 112.475 86.460 115.010 86.480 ;
            RECT 116.550 86.460 120.110 86.480 ;
            RECT 122.030 86.460 142.300 86.480 ;
            RECT 348.800 86.460 350.680 86.480 ;
            RECT 360.160 86.460 360.320 86.480 ;
            RECT 0.000 86.480 100.415 86.840 ;
            RECT 101.525 86.480 103.580 86.840 ;
            RECT 105.500 86.480 107.930 86.840 ;
            RECT 108.820 86.480 110.555 86.840 ;
            RECT 112.475 86.480 115.010 86.840 ;
            RECT 116.550 86.480 120.110 86.840 ;
            RECT 122.030 86.480 142.300 86.840 ;
            RECT 348.800 86.480 360.320 86.840 ;
            RECT 0.000 86.840 2.880 87.160 ;
            RECT 99.400 86.840 100.415 87.160 ;
            RECT 101.525 86.840 103.580 87.160 ;
            RECT 105.500 86.840 107.930 87.160 ;
            RECT 108.820 86.840 110.555 87.160 ;
            RECT 112.475 86.840 115.010 87.160 ;
            RECT 116.550 86.840 120.110 87.160 ;
            RECT 122.030 86.840 142.300 87.160 ;
            RECT 348.800 86.840 350.680 87.160 ;
            RECT 357.440 86.840 360.320 87.160 ;
            RECT 0.000 87.160 100.415 87.260 ;
            RECT 101.525 87.160 103.580 87.260 ;
            RECT 105.500 87.160 107.930 87.260 ;
            RECT 108.820 87.160 110.555 87.260 ;
            RECT 112.475 87.160 115.010 87.260 ;
            RECT 116.550 87.160 120.110 87.260 ;
            RECT 122.030 87.160 142.300 87.260 ;
            RECT 348.800 87.160 360.320 87.260 ;
            RECT 0.000 87.260 100.415 87.520 ;
            RECT 101.525 87.260 103.580 87.520 ;
            RECT 105.500 87.260 107.930 87.520 ;
            RECT 108.820 87.260 110.555 87.520 ;
            RECT 112.475 87.260 115.010 87.520 ;
            RECT 116.550 87.260 120.110 87.520 ;
            RECT 122.030 87.260 360.320 87.520 ;
            RECT 0.000 87.520 0.160 87.840 ;
            RECT 69.480 87.520 81.400 87.840 ;
            RECT 99.400 87.520 100.415 87.840 ;
            RECT 101.525 87.520 103.580 87.840 ;
            RECT 105.500 87.520 107.930 87.840 ;
            RECT 108.820 87.520 110.555 87.840 ;
            RECT 112.475 87.520 115.010 87.840 ;
            RECT 116.550 87.520 120.110 87.840 ;
            RECT 122.030 87.520 350.680 87.840 ;
            RECT 360.160 87.520 360.320 87.840 ;
            RECT 0.000 87.840 100.415 88.200 ;
            RECT 101.525 87.840 103.580 88.200 ;
            RECT 105.500 87.840 107.930 88.200 ;
            RECT 108.820 87.840 110.555 88.200 ;
            RECT 112.475 87.840 115.010 88.200 ;
            RECT 116.550 87.840 120.110 88.200 ;
            RECT 122.030 87.840 360.320 88.200 ;
            RECT 0.000 88.200 2.880 88.520 ;
            RECT 69.480 88.200 81.400 88.520 ;
            RECT 99.400 88.200 100.415 88.520 ;
            RECT 101.525 88.200 103.580 88.520 ;
            RECT 105.500 88.200 107.930 88.520 ;
            RECT 108.820 88.200 110.555 88.520 ;
            RECT 112.475 88.200 115.010 88.520 ;
            RECT 116.550 88.200 120.110 88.520 ;
            RECT 122.030 88.200 350.680 88.520 ;
            RECT 357.440 88.200 360.320 88.520 ;
            RECT 0.000 88.520 100.415 88.880 ;
            RECT 101.525 88.520 103.580 88.880 ;
            RECT 105.500 88.520 107.930 88.880 ;
            RECT 108.820 88.520 110.555 88.880 ;
            RECT 112.475 88.520 115.010 88.880 ;
            RECT 116.550 88.520 120.110 88.880 ;
            RECT 122.030 88.520 360.320 88.880 ;
            RECT 0.000 88.880 0.160 89.200 ;
            RECT 99.400 88.880 100.415 89.200 ;
            RECT 101.525 88.880 103.580 89.200 ;
            RECT 105.500 88.880 107.930 89.200 ;
            RECT 108.820 88.880 110.555 89.200 ;
            RECT 112.475 88.880 115.010 89.200 ;
            RECT 116.550 88.880 120.110 89.200 ;
            RECT 122.030 88.880 350.680 89.200 ;
            RECT 360.160 88.880 360.320 89.200 ;
            RECT 0.000 89.200 100.415 89.560 ;
            RECT 101.525 89.200 103.580 89.560 ;
            RECT 105.500 89.200 107.930 89.560 ;
            RECT 108.820 89.200 110.555 89.560 ;
            RECT 112.475 89.200 115.010 89.560 ;
            RECT 116.550 89.200 120.110 89.560 ;
            RECT 122.030 89.200 360.320 89.560 ;
            RECT 0.000 89.560 2.880 89.645 ;
            RECT 60.640 89.560 73.920 89.645 ;
            RECT 99.400 89.560 100.415 89.645 ;
            RECT 101.525 89.560 103.580 89.645 ;
            RECT 105.500 89.560 107.930 89.645 ;
            RECT 108.820 89.560 110.555 89.645 ;
            RECT 112.475 89.560 115.010 89.645 ;
            RECT 116.550 89.560 120.110 89.645 ;
            RECT 122.030 89.560 350.680 89.645 ;
            RECT 357.440 89.560 360.320 89.645 ;
            RECT 0.000 89.645 2.880 89.880 ;
            RECT 60.640 89.645 73.920 89.880 ;
            RECT 99.400 89.645 100.415 89.880 ;
            RECT 101.525 89.645 103.580 89.880 ;
            RECT 105.500 89.645 107.930 89.880 ;
            RECT 108.820 89.645 110.555 89.880 ;
            RECT 112.475 89.645 115.010 89.880 ;
            RECT 116.550 89.645 120.110 89.880 ;
            RECT 122.030 89.645 142.300 89.880 ;
            RECT 348.800 89.645 350.680 89.880 ;
            RECT 357.440 89.645 360.320 89.880 ;
            RECT 0.000 89.880 100.415 90.240 ;
            RECT 101.525 89.880 103.580 90.240 ;
            RECT 105.500 89.880 107.930 90.240 ;
            RECT 108.820 89.880 110.555 90.240 ;
            RECT 112.475 89.880 115.010 90.240 ;
            RECT 116.550 89.880 120.110 90.240 ;
            RECT 122.030 89.880 142.300 90.240 ;
            RECT 348.800 89.880 360.320 90.240 ;
            RECT 0.000 90.240 0.160 90.445 ;
            RECT 60.640 90.240 78.000 90.445 ;
            RECT 99.400 90.240 100.415 90.445 ;
            RECT 101.525 90.240 103.580 90.445 ;
            RECT 105.500 90.240 107.930 90.445 ;
            RECT 108.820 90.240 110.555 90.445 ;
            RECT 112.475 90.240 115.010 90.445 ;
            RECT 116.550 90.240 120.110 90.445 ;
            RECT 122.030 90.240 142.300 90.445 ;
            RECT 348.800 90.240 350.680 90.445 ;
            RECT 360.160 90.240 360.320 90.445 ;
            RECT 0.000 90.445 0.160 90.560 ;
            RECT 60.640 90.445 78.000 90.560 ;
            RECT 99.400 90.445 100.415 90.560 ;
            RECT 101.525 90.445 103.580 90.560 ;
            RECT 105.500 90.445 107.930 90.560 ;
            RECT 108.820 90.445 110.555 90.560 ;
            RECT 112.475 90.445 115.010 90.560 ;
            RECT 116.550 90.445 120.110 90.560 ;
            RECT 122.030 90.445 350.680 90.560 ;
            RECT 360.160 90.445 360.320 90.560 ;
            RECT 0.000 90.560 100.415 90.920 ;
            RECT 101.525 90.560 103.580 90.920 ;
            RECT 105.500 90.560 107.930 90.920 ;
            RECT 108.820 90.560 110.555 90.920 ;
            RECT 112.475 90.560 115.010 90.920 ;
            RECT 116.550 90.560 120.110 90.920 ;
            RECT 122.030 90.560 360.320 90.920 ;
            RECT 0.000 90.920 2.880 91.240 ;
            RECT 70.840 90.920 78.000 91.240 ;
            RECT 99.400 90.920 100.415 91.240 ;
            RECT 101.525 90.920 103.580 91.240 ;
            RECT 105.500 90.920 107.930 91.240 ;
            RECT 108.820 90.920 110.555 91.240 ;
            RECT 112.475 90.920 115.010 91.240 ;
            RECT 116.550 90.920 120.110 91.240 ;
            RECT 122.030 90.920 350.680 91.240 ;
            RECT 357.440 90.920 360.320 91.240 ;
            RECT 0.000 91.240 100.415 91.365 ;
            RECT 101.525 91.240 103.580 91.365 ;
            RECT 105.500 91.240 107.930 91.365 ;
            RECT 108.820 91.240 110.555 91.365 ;
            RECT 112.475 91.240 115.010 91.365 ;
            RECT 116.550 91.240 120.110 91.365 ;
            RECT 122.030 91.240 360.320 91.365 ;
            RECT 0.000 91.365 100.415 91.600 ;
            RECT 101.525 91.365 103.580 91.600 ;
            RECT 105.500 91.365 107.930 91.600 ;
            RECT 108.820 91.365 110.555 91.600 ;
            RECT 112.475 91.365 115.010 91.600 ;
            RECT 116.550 91.365 120.110 91.600 ;
            RECT 122.030 91.365 142.300 91.600 ;
            RECT 348.800 91.365 360.320 91.600 ;
            RECT 0.000 91.600 0.160 91.920 ;
            RECT 99.400 91.600 100.415 91.920 ;
            RECT 101.525 91.600 103.580 91.920 ;
            RECT 105.500 91.600 107.930 91.920 ;
            RECT 108.820 91.600 110.555 91.920 ;
            RECT 112.475 91.600 115.010 91.920 ;
            RECT 116.550 91.600 120.110 91.920 ;
            RECT 122.030 91.600 122.880 91.920 ;
            RECT 140.880 91.600 142.300 91.920 ;
            RECT 348.800 91.600 350.680 91.920 ;
            RECT 360.160 91.600 360.320 91.920 ;
            RECT 0.000 91.920 100.415 92.080 ;
            RECT 101.525 91.920 103.580 92.080 ;
            RECT 105.500 91.920 107.930 92.080 ;
            RECT 108.820 91.920 110.555 92.080 ;
            RECT 112.475 91.920 115.010 92.080 ;
            RECT 116.550 91.920 120.110 92.080 ;
            RECT 122.030 91.920 142.300 92.080 ;
            RECT 348.800 91.920 360.320 92.080 ;
            RECT 0.000 92.080 142.300 92.165 ;
            RECT 348.800 92.080 360.320 92.165 ;
            RECT 0.000 92.165 360.320 92.280 ;
            RECT 0.000 92.280 2.880 92.600 ;
            RECT 99.400 92.280 122.880 92.600 ;
            RECT 140.880 92.280 350.680 92.600 ;
            RECT 357.440 92.280 360.320 92.600 ;
            RECT 0.000 92.600 360.320 92.960 ;
            RECT 0.000 92.960 0.160 93.280 ;
            RECT 140.880 92.960 350.680 93.280 ;
            RECT 360.160 92.960 360.320 93.280 ;
            RECT 0.000 93.280 360.320 93.640 ;
            RECT 0.000 93.640 2.880 93.960 ;
            RECT 140.880 93.640 350.680 93.960 ;
            RECT 357.440 93.640 360.320 93.960 ;
            RECT 0.000 93.960 360.320 94.320 ;
            RECT 0.000 94.320 0.160 94.640 ;
            RECT 140.880 94.320 350.680 94.640 ;
            RECT 360.160 94.320 360.320 94.640 ;
            RECT 0.000 94.640 360.320 95.000 ;
            RECT 0.000 95.000 2.880 95.320 ;
            RECT 76.280 95.000 84.120 95.320 ;
            RECT 140.880 95.000 350.680 95.320 ;
            RECT 357.440 95.000 360.320 95.320 ;
            RECT 0.000 95.320 360.320 95.445 ;
            RECT 0.000 95.445 142.300 95.680 ;
            RECT 348.800 95.445 360.320 95.680 ;
            RECT 0.000 95.680 0.160 95.735 ;
            RECT 76.280 95.680 84.120 95.735 ;
            RECT 140.880 95.680 142.300 95.735 ;
            RECT 348.800 95.680 350.680 95.735 ;
            RECT 360.160 95.680 360.320 95.735 ;
            RECT 0.000 95.735 0.160 96.000 ;
            RECT 76.280 95.735 84.120 96.000 ;
            RECT 140.880 95.735 350.680 96.000 ;
            RECT 360.160 95.735 360.320 96.000 ;
            RECT 0.000 96.000 360.320 96.360 ;
            RECT 0.000 96.360 2.880 96.680 ;
            RECT 140.880 96.360 350.680 96.680 ;
            RECT 357.440 96.360 360.320 96.680 ;
            RECT 0.000 96.680 360.320 97.040 ;
            RECT 0.000 97.040 0.160 97.360 ;
            RECT 79.680 97.040 82.080 97.360 ;
            RECT 140.880 97.040 350.680 97.360 ;
            RECT 360.160 97.040 360.320 97.360 ;
            RECT 0.000 97.360 360.320 97.720 ;
            RECT 0.000 97.720 2.880 98.040 ;
            RECT 79.680 97.720 82.080 98.040 ;
            RECT 102.120 97.720 123.560 98.040 ;
            RECT 140.880 97.720 350.680 98.040 ;
            RECT 357.440 97.720 360.320 98.040 ;
            RECT 0.000 98.040 360.320 98.080 ;
            RECT 0.000 98.080 102.975 98.400 ;
            RECT 104.085 98.080 106.570 98.400 ;
            RECT 108.490 98.080 111.350 98.400 ;
            RECT 112.240 98.080 113.845 98.400 ;
            RECT 115.595 98.080 117.785 98.400 ;
            RECT 118.895 98.080 121.165 98.400 ;
            RECT 123.085 98.080 360.320 98.400 ;
            RECT 0.000 98.400 0.160 98.720 ;
            RECT 87.840 98.400 99.760 98.720 ;
            RECT 102.120 98.400 102.975 98.720 ;
            RECT 104.085 98.400 106.570 98.720 ;
            RECT 108.490 98.400 111.350 98.720 ;
            RECT 112.240 98.400 113.845 98.720 ;
            RECT 115.595 98.400 117.785 98.720 ;
            RECT 118.895 98.400 121.165 98.720 ;
            RECT 123.085 98.400 123.560 98.720 ;
            RECT 140.880 98.400 350.680 98.720 ;
            RECT 360.160 98.400 360.320 98.720 ;
            RECT 0.000 98.720 102.975 99.080 ;
            RECT 104.085 98.720 106.570 99.080 ;
            RECT 108.490 98.720 111.350 99.080 ;
            RECT 112.240 98.720 113.845 99.080 ;
            RECT 115.595 98.720 117.785 99.080 ;
            RECT 118.895 98.720 121.165 99.080 ;
            RECT 123.085 98.720 360.320 99.080 ;
            RECT 0.000 99.080 2.880 99.400 ;
            RECT 66.080 99.080 69.160 99.400 ;
            RECT 102.120 99.080 102.975 99.400 ;
            RECT 104.085 99.080 106.570 99.400 ;
            RECT 108.490 99.080 111.350 99.400 ;
            RECT 112.240 99.080 113.845 99.400 ;
            RECT 115.595 99.080 117.785 99.400 ;
            RECT 118.895 99.080 121.165 99.400 ;
            RECT 123.085 99.080 123.560 99.400 ;
            RECT 140.880 99.080 350.680 99.400 ;
            RECT 357.440 99.080 360.320 99.400 ;
            RECT 0.000 99.400 102.975 99.760 ;
            RECT 104.085 99.400 106.570 99.760 ;
            RECT 108.490 99.400 111.350 99.760 ;
            RECT 112.240 99.400 113.845 99.760 ;
            RECT 115.595 99.400 117.785 99.760 ;
            RECT 118.895 99.400 121.165 99.760 ;
            RECT 123.085 99.400 360.320 99.760 ;
            RECT 0.000 99.760 0.160 100.080 ;
            RECT 64.040 99.760 69.160 100.080 ;
            RECT 102.120 99.760 102.975 100.080 ;
            RECT 104.085 99.760 106.570 100.080 ;
            RECT 108.490 99.760 111.350 100.080 ;
            RECT 112.240 99.760 113.845 100.080 ;
            RECT 115.595 99.760 117.785 100.080 ;
            RECT 118.895 99.760 121.165 100.080 ;
            RECT 123.085 99.760 123.560 100.080 ;
            RECT 140.880 99.760 350.680 100.080 ;
            RECT 360.160 99.760 360.320 100.080 ;
            RECT 0.000 100.080 102.975 100.440 ;
            RECT 104.085 100.080 106.570 100.440 ;
            RECT 108.490 100.080 111.350 100.440 ;
            RECT 112.240 100.080 113.845 100.440 ;
            RECT 115.595 100.080 117.785 100.440 ;
            RECT 118.895 100.080 121.165 100.440 ;
            RECT 123.085 100.080 360.320 100.440 ;
            RECT 0.000 100.440 2.880 100.760 ;
            RECT 64.040 100.440 67.800 100.760 ;
            RECT 102.120 100.440 102.975 100.760 ;
            RECT 104.085 100.440 106.570 100.760 ;
            RECT 108.490 100.440 111.350 100.760 ;
            RECT 112.240 100.440 113.845 100.760 ;
            RECT 115.595 100.440 117.785 100.760 ;
            RECT 118.895 100.440 121.165 100.760 ;
            RECT 123.085 100.440 123.560 100.760 ;
            RECT 140.880 100.440 350.680 100.760 ;
            RECT 357.440 100.440 360.320 100.760 ;
            RECT 0.000 100.760 102.975 101.120 ;
            RECT 104.085 100.760 106.570 101.120 ;
            RECT 108.490 100.760 111.350 101.120 ;
            RECT 112.240 100.760 113.845 101.120 ;
            RECT 115.595 100.760 117.785 101.120 ;
            RECT 118.895 100.760 121.165 101.120 ;
            RECT 123.085 100.760 360.320 101.120 ;
            RECT 0.000 101.120 0.160 101.440 ;
            RECT 102.120 101.120 102.975 101.440 ;
            RECT 104.085 101.120 106.570 101.440 ;
            RECT 108.490 101.120 111.350 101.440 ;
            RECT 112.240 101.120 113.845 101.440 ;
            RECT 115.595 101.120 117.785 101.440 ;
            RECT 118.895 101.120 121.165 101.440 ;
            RECT 123.085 101.120 123.560 101.440 ;
            RECT 140.880 101.120 350.680 101.440 ;
            RECT 360.160 101.120 360.320 101.440 ;
            RECT 0.000 101.440 102.975 101.800 ;
            RECT 104.085 101.440 106.570 101.800 ;
            RECT 108.490 101.440 111.350 101.800 ;
            RECT 112.240 101.440 113.845 101.800 ;
            RECT 115.595 101.440 117.785 101.800 ;
            RECT 118.895 101.440 121.165 101.800 ;
            RECT 123.085 101.440 360.320 101.800 ;
            RECT 0.000 101.800 2.880 102.120 ;
            RECT 102.120 101.800 102.975 102.120 ;
            RECT 104.085 101.800 106.570 102.120 ;
            RECT 108.490 101.800 111.350 102.120 ;
            RECT 112.240 101.800 113.845 102.120 ;
            RECT 115.595 101.800 117.785 102.120 ;
            RECT 118.895 101.800 121.165 102.120 ;
            RECT 123.085 101.800 123.560 102.120 ;
            RECT 140.880 101.800 350.680 102.120 ;
            RECT 357.440 101.800 360.320 102.120 ;
            RECT 0.000 102.120 102.975 102.480 ;
            RECT 104.085 102.120 106.570 102.480 ;
            RECT 108.490 102.120 111.350 102.480 ;
            RECT 112.240 102.120 113.845 102.480 ;
            RECT 115.595 102.120 117.785 102.480 ;
            RECT 118.895 102.120 121.165 102.480 ;
            RECT 123.085 102.120 360.320 102.480 ;
            RECT 0.000 102.480 0.160 102.800 ;
            RECT 102.120 102.480 102.975 102.800 ;
            RECT 104.085 102.480 106.570 102.800 ;
            RECT 108.490 102.480 111.350 102.800 ;
            RECT 112.240 102.480 113.845 102.800 ;
            RECT 115.595 102.480 117.785 102.800 ;
            RECT 118.895 102.480 121.165 102.800 ;
            RECT 123.085 102.480 123.560 102.800 ;
            RECT 140.880 102.480 350.680 102.800 ;
            RECT 360.160 102.480 360.320 102.800 ;
            RECT 0.000 102.800 102.975 103.160 ;
            RECT 104.085 102.800 106.570 103.160 ;
            RECT 108.490 102.800 111.350 103.160 ;
            RECT 112.240 102.800 113.845 103.160 ;
            RECT 115.595 102.800 117.785 103.160 ;
            RECT 118.895 102.800 121.165 103.160 ;
            RECT 123.085 102.800 360.320 103.160 ;
            RECT 0.000 103.160 2.880 103.480 ;
            RECT 102.120 103.160 102.975 103.480 ;
            RECT 104.085 103.160 106.570 103.480 ;
            RECT 108.490 103.160 111.350 103.480 ;
            RECT 112.240 103.160 113.845 103.480 ;
            RECT 115.595 103.160 117.785 103.480 ;
            RECT 118.895 103.160 121.165 103.480 ;
            RECT 123.085 103.160 123.560 103.480 ;
            RECT 140.880 103.160 350.680 103.480 ;
            RECT 357.440 103.160 360.320 103.480 ;
            RECT 0.000 103.480 102.975 103.840 ;
            RECT 104.085 103.480 106.570 103.840 ;
            RECT 108.490 103.480 111.350 103.840 ;
            RECT 112.240 103.480 113.845 103.840 ;
            RECT 115.595 103.480 117.785 103.840 ;
            RECT 118.895 103.480 121.165 103.840 ;
            RECT 123.085 103.480 360.320 103.840 ;
            RECT 0.000 103.840 0.160 104.160 ;
            RECT 102.120 103.840 102.975 104.160 ;
            RECT 104.085 103.840 106.570 104.160 ;
            RECT 108.490 103.840 111.350 104.160 ;
            RECT 112.240 103.840 113.845 104.160 ;
            RECT 115.595 103.840 117.785 104.160 ;
            RECT 118.895 103.840 121.165 104.160 ;
            RECT 123.085 103.840 123.560 104.160 ;
            RECT 140.880 103.840 350.680 104.160 ;
            RECT 360.160 103.840 360.320 104.160 ;
            RECT 0.000 104.160 102.975 104.520 ;
            RECT 104.085 104.160 106.570 104.520 ;
            RECT 108.490 104.160 111.350 104.520 ;
            RECT 112.240 104.160 113.845 104.520 ;
            RECT 115.595 104.160 117.785 104.520 ;
            RECT 118.895 104.160 121.165 104.520 ;
            RECT 123.085 104.160 360.320 104.520 ;
            RECT 0.000 104.520 2.880 104.840 ;
            RECT 102.120 104.520 102.975 104.840 ;
            RECT 104.085 104.520 106.570 104.840 ;
            RECT 108.490 104.520 111.350 104.840 ;
            RECT 112.240 104.520 113.845 104.840 ;
            RECT 115.595 104.520 117.785 104.840 ;
            RECT 118.895 104.520 121.165 104.840 ;
            RECT 123.085 104.520 123.560 104.840 ;
            RECT 140.880 104.520 350.680 104.840 ;
            RECT 357.440 104.520 360.320 104.840 ;
            RECT 0.000 104.840 102.975 105.200 ;
            RECT 104.085 104.840 106.570 105.200 ;
            RECT 108.490 104.840 111.350 105.200 ;
            RECT 112.240 104.840 113.845 105.200 ;
            RECT 115.595 104.840 117.785 105.200 ;
            RECT 118.895 104.840 121.165 105.200 ;
            RECT 123.085 104.840 360.320 105.200 ;
            RECT 0.000 105.200 0.160 105.520 ;
            RECT 72.200 105.200 81.400 105.520 ;
            RECT 102.120 105.200 102.975 105.520 ;
            RECT 104.085 105.200 106.570 105.520 ;
            RECT 108.490 105.200 111.350 105.520 ;
            RECT 112.240 105.200 113.845 105.520 ;
            RECT 115.595 105.200 117.785 105.520 ;
            RECT 118.895 105.200 121.165 105.520 ;
            RECT 123.085 105.200 123.560 105.520 ;
            RECT 140.880 105.200 350.680 105.520 ;
            RECT 360.160 105.200 360.320 105.520 ;
            RECT 0.000 105.520 102.975 105.880 ;
            RECT 104.085 105.520 106.570 105.880 ;
            RECT 108.490 105.520 111.350 105.880 ;
            RECT 112.240 105.520 113.845 105.880 ;
            RECT 115.595 105.520 117.785 105.880 ;
            RECT 118.895 105.520 121.165 105.880 ;
            RECT 123.085 105.520 360.320 105.880 ;
            RECT 0.000 105.880 2.880 106.200 ;
            RECT 72.200 105.880 81.400 106.200 ;
            RECT 102.120 105.880 102.975 106.200 ;
            RECT 104.085 105.880 106.570 106.200 ;
            RECT 108.490 105.880 111.350 106.200 ;
            RECT 112.240 105.880 113.845 106.200 ;
            RECT 115.595 105.880 117.785 106.200 ;
            RECT 118.895 105.880 121.165 106.200 ;
            RECT 123.085 105.880 123.560 106.200 ;
            RECT 140.880 105.880 350.680 106.200 ;
            RECT 357.440 105.880 360.320 106.200 ;
            RECT 0.000 106.200 102.975 106.560 ;
            RECT 104.085 106.200 106.570 106.560 ;
            RECT 108.490 106.200 111.350 106.560 ;
            RECT 112.240 106.200 113.845 106.560 ;
            RECT 115.595 106.200 117.785 106.560 ;
            RECT 118.895 106.200 121.165 106.560 ;
            RECT 123.085 106.200 360.320 106.560 ;
            RECT 0.000 106.560 0.160 106.880 ;
            RECT 102.120 106.560 102.975 106.880 ;
            RECT 104.085 106.560 106.570 106.880 ;
            RECT 108.490 106.560 111.350 106.880 ;
            RECT 112.240 106.560 113.845 106.880 ;
            RECT 115.595 106.560 117.785 106.880 ;
            RECT 118.895 106.560 121.165 106.880 ;
            RECT 123.085 106.560 123.560 106.880 ;
            RECT 140.880 106.560 350.680 106.880 ;
            RECT 360.160 106.560 360.320 106.880 ;
            RECT 0.000 106.880 102.975 107.240 ;
            RECT 104.085 106.880 106.570 107.240 ;
            RECT 108.490 106.880 111.350 107.240 ;
            RECT 112.240 106.880 113.845 107.240 ;
            RECT 115.595 106.880 117.785 107.240 ;
            RECT 118.895 106.880 121.165 107.240 ;
            RECT 123.085 106.880 360.320 107.240 ;
            RECT 0.000 107.240 2.880 107.560 ;
            RECT 102.120 107.240 102.975 107.560 ;
            RECT 104.085 107.240 106.570 107.560 ;
            RECT 108.490 107.240 111.350 107.560 ;
            RECT 112.240 107.240 113.845 107.560 ;
            RECT 115.595 107.240 117.785 107.560 ;
            RECT 118.895 107.240 121.165 107.560 ;
            RECT 123.085 107.240 123.560 107.560 ;
            RECT 140.880 107.240 350.680 107.560 ;
            RECT 357.440 107.240 360.320 107.560 ;
            RECT 0.000 107.560 102.975 107.920 ;
            RECT 104.085 107.560 106.570 107.920 ;
            RECT 108.490 107.560 111.350 107.920 ;
            RECT 112.240 107.560 113.845 107.920 ;
            RECT 115.595 107.560 117.785 107.920 ;
            RECT 118.895 107.560 121.165 107.920 ;
            RECT 123.085 107.560 360.320 107.920 ;
            RECT 0.000 107.920 0.160 108.005 ;
            RECT 102.120 107.920 102.975 108.005 ;
            RECT 104.085 107.920 106.570 108.005 ;
            RECT 108.490 107.920 111.350 108.005 ;
            RECT 112.240 107.920 113.845 108.005 ;
            RECT 115.595 107.920 117.785 108.005 ;
            RECT 118.895 107.920 121.165 108.005 ;
            RECT 123.085 107.920 123.560 108.005 ;
            RECT 140.880 107.920 350.680 108.005 ;
            RECT 360.160 107.920 360.320 108.005 ;
            RECT 0.000 108.005 0.160 108.240 ;
            RECT 102.120 108.005 102.975 108.240 ;
            RECT 104.085 108.005 106.570 108.240 ;
            RECT 108.490 108.005 111.350 108.240 ;
            RECT 112.240 108.005 113.845 108.240 ;
            RECT 115.595 108.005 117.785 108.240 ;
            RECT 118.895 108.005 121.165 108.240 ;
            RECT 123.085 108.005 123.560 108.240 ;
            RECT 140.880 108.005 142.300 108.240 ;
            RECT 348.800 108.005 350.680 108.240 ;
            RECT 360.160 108.005 360.320 108.240 ;
            RECT 0.000 108.240 102.975 108.295 ;
            RECT 104.085 108.240 106.570 108.295 ;
            RECT 108.490 108.240 111.350 108.295 ;
            RECT 112.240 108.240 113.845 108.295 ;
            RECT 115.595 108.240 117.785 108.295 ;
            RECT 118.895 108.240 121.165 108.295 ;
            RECT 123.085 108.240 142.300 108.295 ;
            RECT 348.800 108.240 360.320 108.295 ;
            RECT 0.000 108.295 102.975 108.600 ;
            RECT 104.085 108.295 106.570 108.600 ;
            RECT 108.490 108.295 111.350 108.600 ;
            RECT 112.240 108.295 113.845 108.600 ;
            RECT 115.595 108.295 117.785 108.600 ;
            RECT 118.895 108.295 121.165 108.600 ;
            RECT 123.085 108.295 360.320 108.600 ;
            RECT 0.000 108.600 2.880 108.920 ;
            RECT 42.280 108.600 61.000 108.920 ;
            RECT 66.080 108.600 71.200 108.920 ;
            RECT 102.120 108.600 102.975 108.920 ;
            RECT 104.085 108.600 106.570 108.920 ;
            RECT 108.490 108.600 111.350 108.920 ;
            RECT 112.240 108.600 113.845 108.920 ;
            RECT 115.595 108.600 117.785 108.920 ;
            RECT 118.895 108.600 121.165 108.920 ;
            RECT 123.085 108.600 123.560 108.920 ;
            RECT 140.880 108.600 350.680 108.920 ;
            RECT 357.440 108.600 360.320 108.920 ;
            RECT 0.000 108.920 102.975 109.280 ;
            RECT 104.085 108.920 106.570 109.280 ;
            RECT 108.490 108.920 111.350 109.280 ;
            RECT 112.240 108.920 113.845 109.280 ;
            RECT 115.595 108.920 117.785 109.280 ;
            RECT 118.895 108.920 121.165 109.280 ;
            RECT 123.085 108.920 360.320 109.280 ;
            RECT 0.000 109.280 0.160 109.600 ;
            RECT 42.280 109.280 61.000 109.600 ;
            RECT 66.080 109.280 71.200 109.600 ;
            RECT 102.120 109.280 102.975 109.600 ;
            RECT 104.085 109.280 106.570 109.600 ;
            RECT 108.490 109.280 111.350 109.600 ;
            RECT 112.240 109.280 113.845 109.600 ;
            RECT 115.595 109.280 117.785 109.600 ;
            RECT 118.895 109.280 121.165 109.600 ;
            RECT 123.085 109.280 350.680 109.600 ;
            RECT 360.160 109.280 360.320 109.600 ;
            RECT 0.000 109.600 102.975 109.960 ;
            RECT 104.085 109.600 106.570 109.960 ;
            RECT 108.490 109.600 111.350 109.960 ;
            RECT 112.240 109.600 113.845 109.960 ;
            RECT 115.595 109.600 117.785 109.960 ;
            RECT 118.895 109.600 121.165 109.960 ;
            RECT 123.085 109.600 360.320 109.960 ;
            RECT 0.000 109.960 2.880 110.280 ;
            RECT 42.280 109.960 61.000 110.280 ;
            RECT 102.120 109.960 102.975 110.280 ;
            RECT 104.085 109.960 106.570 110.280 ;
            RECT 108.490 109.960 111.350 110.280 ;
            RECT 112.240 109.960 113.845 110.280 ;
            RECT 115.595 109.960 117.785 110.280 ;
            RECT 118.895 109.960 121.165 110.280 ;
            RECT 123.085 109.960 350.680 110.280 ;
            RECT 357.440 109.960 360.320 110.280 ;
            RECT 0.000 110.280 102.975 110.640 ;
            RECT 104.085 110.280 106.570 110.640 ;
            RECT 108.490 110.280 111.350 110.640 ;
            RECT 112.240 110.280 113.845 110.640 ;
            RECT 115.595 110.280 117.785 110.640 ;
            RECT 118.895 110.280 121.165 110.640 ;
            RECT 123.085 110.280 360.320 110.640 ;
            RECT 0.000 110.640 0.160 110.960 ;
            RECT 42.280 110.640 61.000 110.960 ;
            RECT 102.120 110.640 102.975 110.960 ;
            RECT 104.085 110.640 106.570 110.960 ;
            RECT 108.490 110.640 111.350 110.960 ;
            RECT 112.240 110.640 113.845 110.960 ;
            RECT 115.595 110.640 117.785 110.960 ;
            RECT 118.895 110.640 121.165 110.960 ;
            RECT 123.085 110.640 123.560 110.960 ;
            RECT 138.160 110.640 350.680 110.960 ;
            RECT 360.160 110.640 360.320 110.960 ;
            RECT 0.000 110.960 102.975 111.320 ;
            RECT 104.085 110.960 106.570 111.320 ;
            RECT 108.490 110.960 111.350 111.320 ;
            RECT 112.240 110.960 113.845 111.320 ;
            RECT 115.595 110.960 117.785 111.320 ;
            RECT 118.895 110.960 121.165 111.320 ;
            RECT 123.085 110.960 360.320 111.320 ;
            RECT 0.000 111.320 2.880 111.640 ;
            RECT 42.280 111.320 61.000 111.640 ;
            RECT 102.120 111.320 102.975 111.640 ;
            RECT 104.085 111.320 106.570 111.640 ;
            RECT 108.490 111.320 111.350 111.640 ;
            RECT 112.240 111.320 113.845 111.640 ;
            RECT 115.595 111.320 117.785 111.640 ;
            RECT 118.895 111.320 121.165 111.640 ;
            RECT 123.085 111.320 123.560 111.640 ;
            RECT 138.160 111.320 350.680 111.640 ;
            RECT 357.440 111.320 360.320 111.640 ;
            RECT 0.000 111.640 102.975 112.000 ;
            RECT 104.085 111.640 106.570 112.000 ;
            RECT 108.490 111.640 111.350 112.000 ;
            RECT 112.240 111.640 113.845 112.000 ;
            RECT 115.595 111.640 117.785 112.000 ;
            RECT 118.895 111.640 121.165 112.000 ;
            RECT 123.085 111.640 360.320 112.000 ;
            RECT 0.000 112.000 0.160 112.320 ;
            RECT 42.280 112.000 61.000 112.320 ;
            RECT 102.120 112.000 102.975 112.320 ;
            RECT 104.085 112.000 106.570 112.320 ;
            RECT 108.490 112.000 111.350 112.320 ;
            RECT 112.240 112.000 113.845 112.320 ;
            RECT 115.595 112.000 117.785 112.320 ;
            RECT 118.895 112.000 121.165 112.320 ;
            RECT 123.085 112.000 123.560 112.320 ;
            RECT 135.440 112.000 350.680 112.320 ;
            RECT 360.160 112.000 360.320 112.320 ;
            RECT 0.000 112.320 102.975 112.680 ;
            RECT 104.085 112.320 106.570 112.680 ;
            RECT 108.490 112.320 111.350 112.680 ;
            RECT 112.240 112.320 113.845 112.680 ;
            RECT 115.595 112.320 117.785 112.680 ;
            RECT 118.895 112.320 121.165 112.680 ;
            RECT 123.085 112.320 360.320 112.680 ;
            RECT 0.000 112.680 2.880 113.000 ;
            RECT 42.280 112.680 61.000 113.000 ;
            RECT 102.120 112.680 102.975 113.000 ;
            RECT 104.085 112.680 106.570 113.000 ;
            RECT 108.490 112.680 111.350 113.000 ;
            RECT 112.240 112.680 113.845 113.000 ;
            RECT 115.595 112.680 117.785 113.000 ;
            RECT 118.895 112.680 121.165 113.000 ;
            RECT 123.085 112.680 123.560 113.000 ;
            RECT 135.440 112.680 350.680 113.000 ;
            RECT 357.440 112.680 360.320 113.000 ;
            RECT 0.000 113.000 102.975 113.360 ;
            RECT 104.085 113.000 106.570 113.360 ;
            RECT 108.490 113.000 111.350 113.360 ;
            RECT 112.240 113.000 113.845 113.360 ;
            RECT 115.595 113.000 117.785 113.360 ;
            RECT 118.895 113.000 121.165 113.360 ;
            RECT 123.085 113.000 360.320 113.360 ;
            RECT 0.000 113.360 0.160 113.680 ;
            RECT 42.280 113.360 61.000 113.680 ;
            RECT 102.120 113.360 102.975 113.680 ;
            RECT 104.085 113.360 106.570 113.680 ;
            RECT 108.490 113.360 111.350 113.680 ;
            RECT 112.240 113.360 113.845 113.680 ;
            RECT 115.595 113.360 117.785 113.680 ;
            RECT 118.895 113.360 121.165 113.680 ;
            RECT 123.085 113.360 123.560 113.680 ;
            RECT 132.720 113.360 350.680 113.680 ;
            RECT 360.160 113.360 360.320 113.680 ;
            RECT 0.000 113.680 102.975 114.040 ;
            RECT 104.085 113.680 106.570 114.040 ;
            RECT 108.490 113.680 111.350 114.040 ;
            RECT 112.240 113.680 113.845 114.040 ;
            RECT 115.595 113.680 117.785 114.040 ;
            RECT 118.895 113.680 121.165 114.040 ;
            RECT 123.085 113.680 360.320 114.040 ;
            RECT 0.000 114.040 2.880 114.360 ;
            RECT 42.280 114.040 61.000 114.360 ;
            RECT 68.800 114.040 71.200 114.360 ;
            RECT 102.120 114.040 102.975 114.360 ;
            RECT 104.085 114.040 106.570 114.360 ;
            RECT 108.490 114.040 111.350 114.360 ;
            RECT 112.240 114.040 113.845 114.360 ;
            RECT 115.595 114.040 117.785 114.360 ;
            RECT 118.895 114.040 121.165 114.360 ;
            RECT 123.085 114.040 123.560 114.360 ;
            RECT 130.000 114.040 350.680 114.360 ;
            RECT 357.440 114.040 360.320 114.360 ;
            RECT 0.000 114.360 102.975 114.720 ;
            RECT 104.085 114.360 106.570 114.720 ;
            RECT 108.490 114.360 111.350 114.720 ;
            RECT 112.240 114.360 113.845 114.720 ;
            RECT 115.595 114.360 117.785 114.720 ;
            RECT 118.895 114.360 121.165 114.720 ;
            RECT 123.085 114.360 360.320 114.720 ;
            RECT 0.000 114.720 0.160 115.040 ;
            RECT 42.280 114.720 61.000 115.040 ;
            RECT 68.800 114.720 71.200 115.040 ;
            RECT 102.120 114.720 102.975 115.040 ;
            RECT 104.085 114.720 106.570 115.040 ;
            RECT 108.490 114.720 111.350 115.040 ;
            RECT 112.240 114.720 113.845 115.040 ;
            RECT 115.595 114.720 117.785 115.040 ;
            RECT 118.895 114.720 121.165 115.040 ;
            RECT 123.085 114.720 123.560 115.040 ;
            RECT 130.000 114.720 350.680 115.040 ;
            RECT 360.160 114.720 360.320 115.040 ;
            RECT 0.000 115.040 102.975 115.400 ;
            RECT 104.085 115.040 106.570 115.400 ;
            RECT 108.490 115.040 111.350 115.400 ;
            RECT 112.240 115.040 113.845 115.400 ;
            RECT 115.595 115.040 117.785 115.400 ;
            RECT 118.895 115.040 121.165 115.400 ;
            RECT 123.085 115.040 360.320 115.400 ;
            RECT 0.000 115.400 2.880 115.720 ;
            RECT 42.280 115.400 61.000 115.720 ;
            RECT 65.400 115.400 68.480 115.720 ;
            RECT 102.120 115.400 102.975 115.720 ;
            RECT 104.085 115.400 106.570 115.720 ;
            RECT 108.490 115.400 111.350 115.720 ;
            RECT 112.240 115.400 113.845 115.720 ;
            RECT 115.595 115.400 117.785 115.720 ;
            RECT 118.895 115.400 121.165 115.720 ;
            RECT 123.085 115.400 123.560 115.720 ;
            RECT 130.000 115.400 350.680 115.720 ;
            RECT 357.440 115.400 360.320 115.720 ;
            RECT 0.000 115.720 102.975 116.080 ;
            RECT 104.085 115.720 106.570 116.080 ;
            RECT 108.490 115.720 111.350 116.080 ;
            RECT 112.240 115.720 113.845 116.080 ;
            RECT 115.595 115.720 117.785 116.080 ;
            RECT 118.895 115.720 121.165 116.080 ;
            RECT 123.085 115.720 360.320 116.080 ;
            RECT 0.000 116.080 0.160 116.400 ;
            RECT 42.280 116.080 61.680 116.400 ;
            RECT 65.400 116.080 68.480 116.400 ;
            RECT 102.120 116.080 102.975 116.400 ;
            RECT 104.085 116.080 106.570 116.400 ;
            RECT 108.490 116.080 111.350 116.400 ;
            RECT 112.240 116.080 113.845 116.400 ;
            RECT 115.595 116.080 117.785 116.400 ;
            RECT 118.895 116.080 121.165 116.400 ;
            RECT 123.085 116.080 123.560 116.400 ;
            RECT 140.880 116.080 350.680 116.400 ;
            RECT 360.160 116.080 360.320 116.400 ;
            RECT 0.000 116.400 102.975 116.760 ;
            RECT 104.085 116.400 106.570 116.760 ;
            RECT 108.490 116.400 111.350 116.760 ;
            RECT 112.240 116.400 113.845 116.760 ;
            RECT 115.595 116.400 117.785 116.760 ;
            RECT 118.895 116.400 121.165 116.760 ;
            RECT 123.085 116.400 360.320 116.760 ;
            RECT 0.000 116.760 2.880 117.080 ;
            RECT 42.280 116.760 61.000 117.080 ;
            RECT 102.120 116.760 102.975 117.080 ;
            RECT 104.085 116.760 106.570 117.080 ;
            RECT 108.490 116.760 111.350 117.080 ;
            RECT 112.240 116.760 113.845 117.080 ;
            RECT 115.595 116.760 117.785 117.080 ;
            RECT 118.895 116.760 121.165 117.080 ;
            RECT 123.085 116.760 123.560 117.080 ;
            RECT 140.880 116.760 350.680 117.080 ;
            RECT 357.440 116.760 360.320 117.080 ;
            RECT 0.000 117.080 102.975 117.440 ;
            RECT 104.085 117.080 106.570 117.440 ;
            RECT 108.490 117.080 111.350 117.440 ;
            RECT 112.240 117.080 113.845 117.440 ;
            RECT 115.595 117.080 117.785 117.440 ;
            RECT 118.895 117.080 121.165 117.440 ;
            RECT 123.085 117.080 360.320 117.440 ;
            RECT 0.000 117.440 0.160 117.700 ;
            RECT 42.280 117.440 61.000 117.700 ;
            RECT 102.120 117.440 102.975 117.700 ;
            RECT 104.085 117.440 106.570 117.700 ;
            RECT 108.490 117.440 111.350 117.700 ;
            RECT 112.240 117.440 113.845 117.700 ;
            RECT 115.595 117.440 117.785 117.700 ;
            RECT 118.895 117.440 121.165 117.700 ;
            RECT 123.085 117.440 123.560 117.700 ;
            RECT 140.880 117.440 350.680 117.700 ;
            RECT 360.160 117.440 360.320 117.700 ;
            RECT 0.000 117.700 0.160 117.760 ;
            RECT 42.280 117.700 61.000 117.760 ;
            RECT 102.120 117.700 102.975 117.760 ;
            RECT 104.085 117.700 106.570 117.760 ;
            RECT 108.490 117.700 111.350 117.760 ;
            RECT 112.240 117.700 113.845 117.760 ;
            RECT 115.595 117.700 117.785 117.760 ;
            RECT 118.895 117.700 121.165 117.760 ;
            RECT 123.085 117.700 123.560 117.760 ;
            RECT 140.880 117.700 142.300 117.760 ;
            RECT 348.800 117.700 350.680 117.760 ;
            RECT 360.160 117.700 360.320 117.760 ;
            RECT 0.000 117.760 102.975 117.880 ;
            RECT 104.085 117.760 106.570 117.880 ;
            RECT 108.490 117.760 111.350 117.880 ;
            RECT 112.240 117.760 113.845 117.880 ;
            RECT 115.595 117.760 117.785 117.880 ;
            RECT 118.895 117.760 121.165 117.880 ;
            RECT 123.085 117.760 142.300 117.880 ;
            RECT 348.800 117.760 360.320 117.880 ;
            RECT 0.000 117.880 142.300 118.120 ;
            RECT 348.800 117.880 360.320 118.120 ;
            RECT 0.000 118.120 2.880 118.440 ;
            RECT 42.280 118.120 61.000 118.440 ;
            RECT 102.120 118.120 123.560 118.440 ;
            RECT 140.880 118.120 142.300 118.440 ;
            RECT 348.800 118.120 350.680 118.440 ;
            RECT 357.440 118.120 360.320 118.440 ;
            RECT 0.000 118.440 142.300 118.570 ;
            RECT 348.800 118.440 360.320 118.570 ;
            RECT 0.000 118.570 360.320 118.800 ;
            RECT 0.000 118.800 0.160 119.120 ;
            RECT 42.280 118.800 61.000 119.120 ;
            RECT 140.880 118.800 350.680 119.120 ;
            RECT 360.160 118.800 360.320 119.120 ;
            RECT 0.000 119.120 360.320 119.480 ;
            RECT 0.000 119.480 2.880 119.800 ;
            RECT 42.280 119.480 61.000 119.800 ;
            RECT 140.880 119.480 350.680 119.800 ;
            RECT 357.440 119.480 360.320 119.800 ;
            RECT 0.000 119.800 360.320 120.160 ;
            RECT 0.000 120.160 0.160 120.480 ;
            RECT 42.280 120.160 61.000 120.480 ;
            RECT 140.880 120.160 350.680 120.480 ;
            RECT 360.160 120.160 360.320 120.480 ;
            RECT 0.000 120.480 360.320 120.840 ;
            RECT 0.000 120.840 2.880 121.160 ;
            RECT 42.280 120.840 61.000 121.160 ;
            RECT 140.880 120.840 350.680 121.160 ;
            RECT 357.440 120.840 360.320 121.160 ;
            RECT 0.000 121.160 360.320 121.520 ;
            RECT 0.000 121.520 0.160 121.840 ;
            RECT 42.280 121.520 61.000 121.840 ;
            RECT 140.880 121.520 350.680 121.840 ;
            RECT 360.160 121.520 360.320 121.840 ;
            RECT 0.000 121.840 360.320 121.980 ;
            RECT 0.000 121.980 142.300 122.200 ;
            RECT 348.800 121.980 360.320 122.200 ;
            RECT 0.000 122.200 2.880 122.225 ;
            RECT 42.280 122.200 61.000 122.225 ;
            RECT 140.880 122.200 142.300 122.225 ;
            RECT 348.800 122.200 350.680 122.225 ;
            RECT 357.440 122.200 360.320 122.225 ;
            RECT 0.000 122.225 2.880 122.520 ;
            RECT 42.280 122.225 61.000 122.520 ;
            RECT 140.880 122.225 350.680 122.520 ;
            RECT 357.440 122.225 360.320 122.520 ;
            RECT 0.000 122.520 360.320 122.880 ;
            RECT 0.000 122.880 0.160 123.200 ;
            RECT 42.280 122.880 61.000 123.200 ;
            RECT 140.880 122.880 350.680 123.200 ;
            RECT 360.160 122.880 360.320 123.200 ;
            RECT 0.000 123.200 360.320 123.560 ;
            RECT 0.000 123.560 2.880 123.880 ;
            RECT 42.280 123.560 61.000 123.880 ;
            RECT 101.440 123.560 123.560 123.880 ;
            RECT 131.360 123.560 350.680 123.880 ;
            RECT 357.440 123.560 360.320 123.880 ;
            RECT 0.000 123.880 102.115 124.240 ;
            RECT 103.225 123.880 105.495 124.240 ;
            RECT 107.415 123.880 110.060 124.240 ;
            RECT 110.950 123.880 112.555 124.240 ;
            RECT 114.305 123.880 116.605 124.240 ;
            RECT 117.925 123.880 120.735 124.240 ;
            RECT 122.655 123.880 360.320 124.240 ;
            RECT 0.000 124.240 0.160 124.560 ;
            RECT 42.280 124.240 61.000 124.560 ;
            RECT 101.440 124.240 102.115 124.560 ;
            RECT 103.225 124.240 105.495 124.560 ;
            RECT 107.415 124.240 110.060 124.560 ;
            RECT 110.950 124.240 112.555 124.560 ;
            RECT 114.305 124.240 116.605 124.560 ;
            RECT 117.925 124.240 120.735 124.560 ;
            RECT 122.655 124.240 123.560 124.560 ;
            RECT 131.360 124.240 350.680 124.560 ;
            RECT 360.160 124.240 360.320 124.560 ;
            RECT 0.000 124.560 102.115 124.920 ;
            RECT 103.225 124.560 105.495 124.920 ;
            RECT 107.415 124.560 110.060 124.920 ;
            RECT 110.950 124.560 112.555 124.920 ;
            RECT 114.305 124.560 116.605 124.920 ;
            RECT 117.925 124.560 120.735 124.920 ;
            RECT 122.655 124.560 360.320 124.920 ;
            RECT 0.000 124.920 2.880 125.240 ;
            RECT 42.280 124.920 61.000 125.240 ;
            RECT 67.440 124.920 71.200 125.240 ;
            RECT 101.440 124.920 102.115 125.240 ;
            RECT 103.225 124.920 105.495 125.240 ;
            RECT 107.415 124.920 110.060 125.240 ;
            RECT 110.950 124.920 112.555 125.240 ;
            RECT 114.305 124.920 116.605 125.240 ;
            RECT 117.925 124.920 120.735 125.240 ;
            RECT 122.655 124.920 123.560 125.240 ;
            RECT 131.360 124.920 350.680 125.240 ;
            RECT 357.440 124.920 360.320 125.240 ;
            RECT 0.000 125.240 102.115 125.600 ;
            RECT 103.225 125.240 105.495 125.600 ;
            RECT 107.415 125.240 110.060 125.600 ;
            RECT 110.950 125.240 112.555 125.600 ;
            RECT 114.305 125.240 116.605 125.600 ;
            RECT 117.925 125.240 120.735 125.600 ;
            RECT 122.655 125.240 360.320 125.600 ;
            RECT 0.000 125.600 0.160 125.920 ;
            RECT 42.280 125.600 61.000 125.920 ;
            RECT 67.440 125.600 71.200 125.920 ;
            RECT 101.440 125.600 102.115 125.920 ;
            RECT 103.225 125.600 105.495 125.920 ;
            RECT 107.415 125.600 110.060 125.920 ;
            RECT 110.950 125.600 112.555 125.920 ;
            RECT 114.305 125.600 116.605 125.920 ;
            RECT 117.925 125.600 120.735 125.920 ;
            RECT 122.655 125.600 123.560 125.920 ;
            RECT 134.080 125.600 350.680 125.920 ;
            RECT 360.160 125.600 360.320 125.920 ;
            RECT 0.000 125.920 102.115 126.280 ;
            RECT 103.225 125.920 105.495 126.280 ;
            RECT 107.415 125.920 110.060 126.280 ;
            RECT 110.950 125.920 112.555 126.280 ;
            RECT 114.305 125.920 116.605 126.280 ;
            RECT 117.925 125.920 120.735 126.280 ;
            RECT 122.655 125.920 360.320 126.280 ;
            RECT 0.000 126.280 2.880 126.600 ;
            RECT 42.280 126.280 61.000 126.600 ;
            RECT 101.440 126.280 102.115 126.600 ;
            RECT 103.225 126.280 105.495 126.600 ;
            RECT 107.415 126.280 110.060 126.600 ;
            RECT 110.950 126.280 112.555 126.600 ;
            RECT 114.305 126.280 116.605 126.600 ;
            RECT 117.925 126.280 120.735 126.600 ;
            RECT 122.655 126.280 123.560 126.600 ;
            RECT 134.080 126.280 350.680 126.600 ;
            RECT 357.440 126.280 360.320 126.600 ;
            RECT 0.000 126.600 102.115 126.960 ;
            RECT 103.225 126.600 105.495 126.960 ;
            RECT 107.415 126.600 110.060 126.960 ;
            RECT 110.950 126.600 112.555 126.960 ;
            RECT 114.305 126.600 116.605 126.960 ;
            RECT 117.925 126.600 120.735 126.960 ;
            RECT 122.655 126.600 360.320 126.960 ;
            RECT 0.000 126.960 0.160 127.280 ;
            RECT 101.440 126.960 102.115 127.280 ;
            RECT 103.225 126.960 105.495 127.280 ;
            RECT 107.415 126.960 110.060 127.280 ;
            RECT 110.950 126.960 112.555 127.280 ;
            RECT 114.305 126.960 116.605 127.280 ;
            RECT 117.925 126.960 120.735 127.280 ;
            RECT 122.655 126.960 123.560 127.280 ;
            RECT 136.800 126.960 350.680 127.280 ;
            RECT 360.160 126.960 360.320 127.280 ;
            RECT 0.000 127.280 102.115 127.640 ;
            RECT 103.225 127.280 105.495 127.640 ;
            RECT 107.415 127.280 110.060 127.640 ;
            RECT 110.950 127.280 112.555 127.640 ;
            RECT 114.305 127.280 116.605 127.640 ;
            RECT 117.925 127.280 120.735 127.640 ;
            RECT 122.655 127.280 360.320 127.640 ;
            RECT 0.000 127.640 2.880 127.960 ;
            RECT 101.440 127.640 102.115 127.960 ;
            RECT 103.225 127.640 105.495 127.960 ;
            RECT 107.415 127.640 110.060 127.960 ;
            RECT 110.950 127.640 112.555 127.960 ;
            RECT 114.305 127.640 116.605 127.960 ;
            RECT 117.925 127.640 120.735 127.960 ;
            RECT 122.655 127.640 123.560 127.960 ;
            RECT 136.800 127.640 350.680 127.960 ;
            RECT 357.440 127.640 360.320 127.960 ;
            RECT 0.000 127.960 102.115 128.320 ;
            RECT 103.225 127.960 105.495 128.320 ;
            RECT 107.415 127.960 110.060 128.320 ;
            RECT 110.950 127.960 112.555 128.320 ;
            RECT 114.305 127.960 116.605 128.320 ;
            RECT 117.925 127.960 120.735 128.320 ;
            RECT 122.655 127.960 360.320 128.320 ;
            RECT 0.000 128.320 0.160 128.640 ;
            RECT 101.440 128.320 102.115 128.640 ;
            RECT 103.225 128.320 105.495 128.640 ;
            RECT 107.415 128.320 110.060 128.640 ;
            RECT 110.950 128.320 112.555 128.640 ;
            RECT 114.305 128.320 116.605 128.640 ;
            RECT 117.925 128.320 120.735 128.640 ;
            RECT 122.655 128.320 123.560 128.640 ;
            RECT 139.520 128.320 350.680 128.640 ;
            RECT 360.160 128.320 360.320 128.640 ;
            RECT 0.000 128.640 102.115 129.000 ;
            RECT 103.225 128.640 105.495 129.000 ;
            RECT 107.415 128.640 110.060 129.000 ;
            RECT 110.950 128.640 112.555 129.000 ;
            RECT 114.305 128.640 116.605 129.000 ;
            RECT 117.925 128.640 120.735 129.000 ;
            RECT 122.655 128.640 360.320 129.000 ;
            RECT 0.000 129.000 2.880 129.320 ;
            RECT 101.440 129.000 102.115 129.320 ;
            RECT 103.225 129.000 105.495 129.320 ;
            RECT 107.415 129.000 110.060 129.320 ;
            RECT 110.950 129.000 112.555 129.320 ;
            RECT 114.305 129.000 116.605 129.320 ;
            RECT 117.925 129.000 120.735 129.320 ;
            RECT 122.655 129.000 350.680 129.320 ;
            RECT 357.440 129.000 360.320 129.320 ;
            RECT 0.000 129.320 102.115 129.680 ;
            RECT 103.225 129.320 105.495 129.680 ;
            RECT 107.415 129.320 110.060 129.680 ;
            RECT 110.950 129.320 112.555 129.680 ;
            RECT 114.305 129.320 116.605 129.680 ;
            RECT 117.925 129.320 120.735 129.680 ;
            RECT 122.655 129.320 360.320 129.680 ;
            RECT 0.000 129.680 0.160 130.000 ;
            RECT 69.480 129.680 75.280 130.000 ;
            RECT 101.440 129.680 102.115 130.000 ;
            RECT 103.225 129.680 105.495 130.000 ;
            RECT 107.415 129.680 110.060 130.000 ;
            RECT 110.950 129.680 112.555 130.000 ;
            RECT 114.305 129.680 116.605 130.000 ;
            RECT 117.925 129.680 120.735 130.000 ;
            RECT 122.655 129.680 350.680 130.000 ;
            RECT 360.160 129.680 360.320 130.000 ;
            RECT 0.000 130.000 102.115 130.360 ;
            RECT 103.225 130.000 105.495 130.360 ;
            RECT 107.415 130.000 110.060 130.360 ;
            RECT 110.950 130.000 112.555 130.360 ;
            RECT 114.305 130.000 116.605 130.360 ;
            RECT 117.925 130.000 120.735 130.360 ;
            RECT 122.655 130.000 360.320 130.360 ;
            RECT 0.000 130.360 2.880 130.420 ;
            RECT 25.960 130.360 42.640 130.420 ;
            RECT 69.480 130.360 75.280 130.420 ;
            RECT 101.440 130.360 102.115 130.420 ;
            RECT 103.225 130.360 105.495 130.420 ;
            RECT 107.415 130.360 110.060 130.420 ;
            RECT 110.950 130.360 112.555 130.420 ;
            RECT 114.305 130.360 116.605 130.420 ;
            RECT 117.925 130.360 120.735 130.420 ;
            RECT 122.655 130.360 350.680 130.420 ;
            RECT 357.440 130.360 360.320 130.420 ;
            RECT 0.000 130.420 2.880 130.680 ;
            RECT 25.960 130.420 26.880 130.680 ;
            RECT 41.720 130.420 42.640 130.680 ;
            RECT 69.480 130.420 75.280 130.680 ;
            RECT 101.440 130.420 102.115 130.680 ;
            RECT 103.225 130.420 105.495 130.680 ;
            RECT 107.415 130.420 110.060 130.680 ;
            RECT 110.950 130.420 112.555 130.680 ;
            RECT 114.305 130.420 116.605 130.680 ;
            RECT 117.925 130.420 120.735 130.680 ;
            RECT 122.655 130.420 350.680 130.680 ;
            RECT 357.440 130.420 360.320 130.680 ;
            RECT 0.000 130.680 26.880 131.040 ;
            RECT 41.720 130.680 102.115 131.040 ;
            RECT 103.225 130.680 105.495 131.040 ;
            RECT 107.415 130.680 110.060 131.040 ;
            RECT 110.950 130.680 112.555 131.040 ;
            RECT 114.305 130.680 116.605 131.040 ;
            RECT 117.925 130.680 120.735 131.040 ;
            RECT 122.655 130.680 360.320 131.040 ;
            RECT 0.000 131.040 0.160 131.090 ;
            RECT 25.960 131.040 26.880 131.090 ;
            RECT 41.720 131.040 42.640 131.090 ;
            RECT 48.400 131.040 55.560 131.090 ;
            RECT 101.440 131.040 102.115 131.090 ;
            RECT 103.225 131.040 105.495 131.090 ;
            RECT 107.415 131.040 110.060 131.090 ;
            RECT 110.950 131.040 112.555 131.090 ;
            RECT 114.305 131.040 116.605 131.090 ;
            RECT 117.925 131.040 120.735 131.090 ;
            RECT 122.655 131.040 123.560 131.090 ;
            RECT 140.880 131.040 350.680 131.090 ;
            RECT 360.160 131.040 360.320 131.090 ;
            RECT 0.000 131.090 0.160 131.360 ;
            RECT 25.960 131.090 42.640 131.360 ;
            RECT 48.400 131.090 55.560 131.360 ;
            RECT 101.440 131.090 102.115 131.360 ;
            RECT 103.225 131.090 105.495 131.360 ;
            RECT 107.415 131.090 110.060 131.360 ;
            RECT 110.950 131.090 112.555 131.360 ;
            RECT 114.305 131.090 116.605 131.360 ;
            RECT 117.925 131.090 120.735 131.360 ;
            RECT 122.655 131.090 123.560 131.360 ;
            RECT 140.880 131.090 350.680 131.360 ;
            RECT 360.160 131.090 360.320 131.360 ;
            RECT 0.000 131.360 102.115 131.720 ;
            RECT 103.225 131.360 105.495 131.720 ;
            RECT 107.415 131.360 110.060 131.720 ;
            RECT 110.950 131.360 112.555 131.720 ;
            RECT 114.305 131.360 116.605 131.720 ;
            RECT 117.925 131.360 120.735 131.720 ;
            RECT 122.655 131.360 360.320 131.720 ;
            RECT 0.000 131.720 2.880 132.025 ;
            RECT 25.960 131.720 26.880 132.025 ;
            RECT 41.720 131.720 42.640 132.025 ;
            RECT 48.400 131.720 55.560 132.025 ;
            RECT 101.440 131.720 102.115 132.025 ;
            RECT 103.225 131.720 105.495 132.025 ;
            RECT 107.415 131.720 110.060 132.025 ;
            RECT 110.950 131.720 112.555 132.025 ;
            RECT 114.305 131.720 116.605 132.025 ;
            RECT 117.925 131.720 120.735 132.025 ;
            RECT 122.655 131.720 123.560 132.025 ;
            RECT 140.880 131.720 350.680 132.025 ;
            RECT 357.440 131.720 360.320 132.025 ;
            RECT 0.000 132.025 2.880 132.040 ;
            RECT 25.960 132.025 26.880 132.040 ;
            RECT 41.720 132.025 42.640 132.040 ;
            RECT 48.400 132.025 55.560 132.040 ;
            RECT 101.440 132.025 102.115 132.040 ;
            RECT 103.225 132.025 105.495 132.040 ;
            RECT 107.415 132.025 110.060 132.040 ;
            RECT 110.950 132.025 112.555 132.040 ;
            RECT 114.305 132.025 116.605 132.040 ;
            RECT 117.925 132.025 120.735 132.040 ;
            RECT 122.655 132.025 123.560 132.040 ;
            RECT 140.880 132.025 142.300 132.040 ;
            RECT 348.800 132.025 350.680 132.040 ;
            RECT 357.440 132.025 360.320 132.040 ;
            RECT 0.000 132.040 26.880 132.400 ;
            RECT 41.720 132.040 102.115 132.400 ;
            RECT 103.225 132.040 105.495 132.400 ;
            RECT 107.415 132.040 110.060 132.400 ;
            RECT 110.950 132.040 112.555 132.400 ;
            RECT 114.305 132.040 116.605 132.400 ;
            RECT 117.925 132.040 120.735 132.400 ;
            RECT 122.655 132.040 142.300 132.400 ;
            RECT 348.800 132.040 360.320 132.400 ;
            RECT 0.000 132.400 0.160 132.720 ;
            RECT 25.960 132.400 26.880 132.720 ;
            RECT 41.720 132.400 60.320 132.720 ;
            RECT 101.440 132.400 102.115 132.720 ;
            RECT 103.225 132.400 105.495 132.720 ;
            RECT 107.415 132.400 110.060 132.720 ;
            RECT 110.950 132.400 112.555 132.720 ;
            RECT 114.305 132.400 116.605 132.720 ;
            RECT 117.925 132.400 120.735 132.720 ;
            RECT 122.655 132.400 123.560 132.720 ;
            RECT 140.880 132.400 142.300 132.720 ;
            RECT 348.800 132.400 350.680 132.720 ;
            RECT 360.160 132.400 360.320 132.720 ;
            RECT 0.000 132.720 26.880 132.730 ;
            RECT 41.720 132.720 102.115 132.730 ;
            RECT 103.225 132.720 105.495 132.730 ;
            RECT 107.415 132.720 110.060 132.730 ;
            RECT 110.950 132.720 112.555 132.730 ;
            RECT 114.305 132.720 116.605 132.730 ;
            RECT 117.925 132.720 120.735 132.730 ;
            RECT 122.655 132.720 142.300 132.730 ;
            RECT 348.800 132.720 360.320 132.730 ;
            RECT 0.000 132.730 102.115 132.825 ;
            RECT 103.225 132.730 105.495 132.825 ;
            RECT 107.415 132.730 110.060 132.825 ;
            RECT 110.950 132.730 112.555 132.825 ;
            RECT 114.305 132.730 116.605 132.825 ;
            RECT 117.925 132.730 120.735 132.825 ;
            RECT 122.655 132.730 142.300 132.825 ;
            RECT 348.800 132.730 360.320 132.825 ;
            RECT 0.000 132.825 102.115 133.050 ;
            RECT 103.225 132.825 105.495 133.050 ;
            RECT 107.415 132.825 110.060 133.050 ;
            RECT 110.950 132.825 112.555 133.050 ;
            RECT 114.305 132.825 116.605 133.050 ;
            RECT 117.925 132.825 120.735 133.050 ;
            RECT 122.655 132.825 360.320 133.050 ;
            RECT 0.000 133.050 43.680 133.080 ;
            RECT 59.720 133.050 102.115 133.080 ;
            RECT 103.225 133.050 105.495 133.080 ;
            RECT 107.415 133.050 110.060 133.080 ;
            RECT 110.950 133.050 112.555 133.080 ;
            RECT 114.305 133.050 116.605 133.080 ;
            RECT 117.925 133.050 120.735 133.080 ;
            RECT 122.655 133.050 360.320 133.080 ;
            RECT 0.000 133.080 2.880 133.400 ;
            RECT 25.960 133.080 43.680 133.400 ;
            RECT 59.720 133.080 60.320 133.400 ;
            RECT 101.440 133.080 102.115 133.400 ;
            RECT 103.225 133.080 105.495 133.400 ;
            RECT 107.415 133.080 110.060 133.400 ;
            RECT 110.950 133.080 112.555 133.400 ;
            RECT 114.305 133.080 116.605 133.400 ;
            RECT 117.925 133.080 120.735 133.400 ;
            RECT 122.655 133.080 123.560 133.400 ;
            RECT 140.880 133.080 350.680 133.400 ;
            RECT 357.440 133.080 360.320 133.400 ;
            RECT 0.000 133.400 43.680 133.760 ;
            RECT 59.720 133.400 102.115 133.760 ;
            RECT 103.225 133.400 105.495 133.760 ;
            RECT 107.415 133.400 110.060 133.760 ;
            RECT 110.950 133.400 112.555 133.760 ;
            RECT 114.305 133.400 116.605 133.760 ;
            RECT 117.925 133.400 120.735 133.760 ;
            RECT 122.655 133.400 360.320 133.760 ;
            RECT 0.000 133.760 0.160 133.850 ;
            RECT 25.960 133.760 26.880 133.850 ;
            RECT 41.720 133.760 43.680 133.850 ;
            RECT 59.720 133.760 60.320 133.850 ;
            RECT 101.440 133.760 102.115 133.850 ;
            RECT 103.225 133.760 105.495 133.850 ;
            RECT 107.415 133.760 110.060 133.850 ;
            RECT 110.950 133.760 112.555 133.850 ;
            RECT 114.305 133.760 116.605 133.850 ;
            RECT 117.925 133.760 120.735 133.850 ;
            RECT 122.655 133.760 350.680 133.850 ;
            RECT 360.160 133.760 360.320 133.850 ;
            RECT 0.000 133.850 0.160 134.080 ;
            RECT 25.960 133.850 26.880 134.080 ;
            RECT 41.720 133.850 60.320 134.080 ;
            RECT 101.440 133.850 102.115 134.080 ;
            RECT 103.225 133.850 105.495 134.080 ;
            RECT 107.415 133.850 110.060 134.080 ;
            RECT 110.950 133.850 112.555 134.080 ;
            RECT 114.305 133.850 116.605 134.080 ;
            RECT 117.925 133.850 120.735 134.080 ;
            RECT 122.655 133.850 350.680 134.080 ;
            RECT 360.160 133.850 360.320 134.080 ;
            RECT 0.000 134.080 26.880 134.440 ;
            RECT 41.720 134.080 102.115 134.440 ;
            RECT 103.225 134.080 105.495 134.440 ;
            RECT 107.415 134.080 110.060 134.440 ;
            RECT 110.950 134.080 112.555 134.440 ;
            RECT 114.305 134.080 116.605 134.440 ;
            RECT 117.925 134.080 120.735 134.440 ;
            RECT 122.655 134.080 360.320 134.440 ;
            RECT 0.000 134.440 2.880 134.760 ;
            RECT 25.960 134.440 26.880 134.760 ;
            RECT 41.720 134.440 42.640 134.760 ;
            RECT 101.440 134.440 102.115 134.760 ;
            RECT 103.225 134.440 105.495 134.760 ;
            RECT 107.415 134.440 110.060 134.760 ;
            RECT 110.950 134.440 112.555 134.760 ;
            RECT 114.305 134.440 116.605 134.760 ;
            RECT 117.925 134.440 120.735 134.760 ;
            RECT 122.655 134.440 350.680 134.760 ;
            RECT 357.440 134.440 360.320 134.760 ;
            RECT 0.000 134.760 26.880 135.120 ;
            RECT 41.720 134.760 102.115 135.120 ;
            RECT 103.225 134.760 105.495 135.120 ;
            RECT 107.415 134.760 110.060 135.120 ;
            RECT 110.950 134.760 112.555 135.120 ;
            RECT 114.305 134.760 116.605 135.120 ;
            RECT 117.925 134.760 120.735 135.120 ;
            RECT 122.655 134.760 360.320 135.120 ;
            RECT 0.000 135.120 0.160 135.440 ;
            RECT 25.960 135.120 26.880 135.440 ;
            RECT 41.720 135.120 42.640 135.440 ;
            RECT 48.400 135.120 55.560 135.440 ;
            RECT 64.040 135.120 73.920 135.440 ;
            RECT 101.440 135.120 102.115 135.440 ;
            RECT 103.225 135.120 105.495 135.440 ;
            RECT 107.415 135.120 110.060 135.440 ;
            RECT 110.950 135.120 112.555 135.440 ;
            RECT 114.305 135.120 116.605 135.440 ;
            RECT 117.925 135.120 120.735 135.440 ;
            RECT 122.655 135.120 123.560 135.440 ;
            RECT 127.280 135.120 350.680 135.440 ;
            RECT 360.160 135.120 360.320 135.440 ;
            RECT 0.000 135.440 26.880 135.450 ;
            RECT 41.720 135.440 102.115 135.450 ;
            RECT 103.225 135.440 105.495 135.450 ;
            RECT 107.415 135.440 110.060 135.450 ;
            RECT 110.950 135.440 112.555 135.450 ;
            RECT 114.305 135.440 116.605 135.450 ;
            RECT 117.925 135.440 120.735 135.450 ;
            RECT 122.655 135.440 360.320 135.450 ;
            RECT 0.000 135.450 102.115 135.800 ;
            RECT 103.225 135.450 105.495 135.800 ;
            RECT 107.415 135.450 110.060 135.800 ;
            RECT 110.950 135.450 112.555 135.800 ;
            RECT 114.305 135.450 116.605 135.800 ;
            RECT 117.925 135.450 120.735 135.800 ;
            RECT 122.655 135.450 360.320 135.800 ;
            RECT 0.000 135.800 2.880 136.120 ;
            RECT 25.960 135.800 55.560 136.120 ;
            RECT 64.040 135.800 73.920 136.120 ;
            RECT 101.440 135.800 102.115 136.120 ;
            RECT 103.225 135.800 105.495 136.120 ;
            RECT 107.415 135.800 110.060 136.120 ;
            RECT 110.950 135.800 112.555 136.120 ;
            RECT 114.305 135.800 116.605 136.120 ;
            RECT 117.925 135.800 120.735 136.120 ;
            RECT 122.655 135.800 123.560 136.120 ;
            RECT 140.880 135.800 350.680 136.120 ;
            RECT 357.440 135.800 360.320 136.120 ;
            RECT 0.000 136.120 102.115 136.360 ;
            RECT 103.225 136.120 105.495 136.360 ;
            RECT 107.415 136.120 110.060 136.360 ;
            RECT 110.950 136.120 112.555 136.360 ;
            RECT 114.305 136.120 116.605 136.360 ;
            RECT 117.925 136.120 120.735 136.360 ;
            RECT 122.655 136.120 360.320 136.360 ;
            RECT 0.000 136.360 360.320 136.480 ;
            RECT 0.000 136.480 0.160 136.800 ;
            RECT 26.640 136.480 54.880 136.800 ;
            RECT 101.440 136.480 123.560 136.800 ;
            RECT 360.160 136.480 360.320 136.800 ;
            RECT 0.000 136.800 360.320 137.160 ;
            RECT 0.000 137.160 2.880 137.480 ;
            RECT 48.400 137.160 68.480 137.480 ;
            RECT 357.440 137.160 360.320 137.480 ;
            RECT 0.000 137.480 360.320 137.840 ;
            RECT 0.000 137.840 0.160 138.160 ;
            RECT 54.520 137.840 98.400 138.160 ;
            RECT 360.160 137.840 360.320 138.160 ;
            RECT 0.000 138.160 360.320 138.520 ;
            RECT 0.000 138.520 2.880 138.840 ;
            RECT 28.000 138.520 67.800 138.840 ;
            RECT 357.440 138.520 360.320 138.840 ;
            RECT 0.000 138.840 360.320 139.200 ;
            RECT 0.000 139.200 0.160 139.520 ;
            RECT 138.160 139.200 352.720 139.520 ;
            RECT 360.160 139.200 360.320 139.520 ;
            RECT 0.000 139.520 360.320 139.880 ;
            RECT 0.000 139.880 2.880 140.200 ;
            RECT 138.160 139.880 352.720 140.200 ;
            RECT 357.440 139.880 360.320 140.200 ;
            RECT 0.000 140.200 360.320 140.560 ;
            RECT 0.000 140.560 0.160 140.880 ;
            RECT 138.160 140.560 352.720 140.880 ;
            RECT 360.160 140.560 360.320 140.880 ;
            RECT 0.000 140.880 360.320 141.240 ;
            RECT 0.000 141.240 2.880 141.560 ;
            RECT 138.160 141.240 352.720 141.560 ;
            RECT 357.440 141.240 360.320 141.560 ;
            RECT 0.000 141.560 360.320 141.920 ;
            RECT 0.000 141.920 0.160 142.240 ;
            RECT 138.160 141.920 352.720 142.240 ;
            RECT 360.160 141.920 360.320 142.240 ;
            RECT 0.000 142.240 360.320 142.600 ;
            RECT 0.000 142.600 2.880 142.920 ;
            RECT 23.240 142.600 29.720 142.920 ;
            RECT 71.520 142.600 352.720 142.920 ;
            RECT 357.440 142.600 360.320 142.920 ;
            RECT 0.000 142.920 360.320 142.995 ;
            RECT 0.000 142.995 72.470 143.280 ;
            RECT 74.390 142.995 78.435 143.280 ;
            RECT 80.355 142.995 82.275 143.280 ;
            RECT 84.195 142.995 86.115 143.280 ;
            RECT 88.035 142.995 92.590 143.280 ;
            RECT 94.510 142.995 96.430 143.280 ;
            RECT 98.350 142.995 100.270 143.280 ;
            RECT 102.190 142.995 106.555 143.280 ;
            RECT 108.475 142.995 110.395 143.280 ;
            RECT 112.315 142.995 114.235 143.280 ;
            RECT 116.155 142.995 118.075 143.280 ;
            RECT 119.995 142.995 121.915 143.280 ;
            RECT 123.835 142.995 125.755 143.280 ;
            RECT 127.675 142.995 129.595 143.280 ;
            RECT 131.515 142.995 133.435 143.280 ;
            RECT 135.355 142.995 360.320 143.280 ;
            RECT 0.000 143.280 0.160 143.600 ;
            RECT 23.240 143.280 29.720 143.600 ;
            RECT 32.080 143.280 40.600 143.600 ;
            RECT 71.520 143.280 72.470 143.600 ;
            RECT 74.390 143.280 78.435 143.600 ;
            RECT 80.355 143.280 82.275 143.600 ;
            RECT 84.195 143.280 86.115 143.600 ;
            RECT 88.035 143.280 92.590 143.600 ;
            RECT 94.510 143.280 96.430 143.600 ;
            RECT 98.350 143.280 100.270 143.600 ;
            RECT 102.190 143.280 106.555 143.600 ;
            RECT 108.475 143.280 110.395 143.600 ;
            RECT 112.315 143.280 114.235 143.600 ;
            RECT 116.155 143.280 118.075 143.600 ;
            RECT 119.995 143.280 121.915 143.600 ;
            RECT 123.835 143.280 125.755 143.600 ;
            RECT 127.675 143.280 129.595 143.600 ;
            RECT 131.515 143.280 133.435 143.600 ;
            RECT 135.355 143.280 352.720 143.600 ;
            RECT 360.160 143.280 360.320 143.600 ;
            RECT 0.000 143.600 72.470 143.960 ;
            RECT 74.390 143.600 78.435 143.960 ;
            RECT 80.355 143.600 82.275 143.960 ;
            RECT 84.195 143.600 86.115 143.960 ;
            RECT 88.035 143.600 92.590 143.960 ;
            RECT 94.510 143.600 96.430 143.960 ;
            RECT 98.350 143.600 100.270 143.960 ;
            RECT 102.190 143.600 106.555 143.960 ;
            RECT 108.475 143.600 110.395 143.960 ;
            RECT 112.315 143.600 114.235 143.960 ;
            RECT 116.155 143.600 118.075 143.960 ;
            RECT 119.995 143.600 121.915 143.960 ;
            RECT 123.835 143.600 125.755 143.960 ;
            RECT 127.675 143.600 129.595 143.960 ;
            RECT 131.515 143.600 133.435 143.960 ;
            RECT 135.355 143.600 360.320 143.960 ;
            RECT 0.000 143.960 2.880 144.060 ;
            RECT 21.200 143.960 39.920 144.060 ;
            RECT 71.520 143.960 72.470 144.060 ;
            RECT 74.390 143.960 78.435 144.060 ;
            RECT 80.355 143.960 82.275 144.060 ;
            RECT 84.195 143.960 86.115 144.060 ;
            RECT 88.035 143.960 92.590 144.060 ;
            RECT 94.510 143.960 96.430 144.060 ;
            RECT 98.350 143.960 100.270 144.060 ;
            RECT 102.190 143.960 106.555 144.060 ;
            RECT 108.475 143.960 110.395 144.060 ;
            RECT 112.315 143.960 114.235 144.060 ;
            RECT 116.155 143.960 118.075 144.060 ;
            RECT 119.995 143.960 121.915 144.060 ;
            RECT 123.835 143.960 125.755 144.060 ;
            RECT 127.675 143.960 129.595 144.060 ;
            RECT 131.515 143.960 133.435 144.060 ;
            RECT 135.355 143.960 352.720 144.060 ;
            RECT 357.440 143.960 360.320 144.060 ;
            RECT 0.000 144.060 2.880 144.280 ;
            RECT 21.200 144.060 21.950 144.280 ;
            RECT 31.110 144.060 39.920 144.280 ;
            RECT 71.520 144.060 72.470 144.280 ;
            RECT 74.390 144.060 78.435 144.280 ;
            RECT 80.355 144.060 82.275 144.280 ;
            RECT 84.195 144.060 86.115 144.280 ;
            RECT 88.035 144.060 92.590 144.280 ;
            RECT 94.510 144.060 96.430 144.280 ;
            RECT 98.350 144.060 100.270 144.280 ;
            RECT 102.190 144.060 106.555 144.280 ;
            RECT 108.475 144.060 110.395 144.280 ;
            RECT 112.315 144.060 114.235 144.280 ;
            RECT 116.155 144.060 118.075 144.280 ;
            RECT 119.995 144.060 121.915 144.280 ;
            RECT 123.835 144.060 125.755 144.280 ;
            RECT 127.675 144.060 129.595 144.280 ;
            RECT 131.515 144.060 133.435 144.280 ;
            RECT 135.355 144.060 352.720 144.280 ;
            RECT 357.440 144.060 360.320 144.280 ;
            RECT 0.000 144.280 21.950 144.430 ;
            RECT 31.110 144.280 72.470 144.430 ;
            RECT 74.390 144.280 78.435 144.430 ;
            RECT 80.355 144.280 82.275 144.430 ;
            RECT 84.195 144.280 86.115 144.430 ;
            RECT 88.035 144.280 92.590 144.430 ;
            RECT 94.510 144.280 96.430 144.430 ;
            RECT 98.350 144.280 100.270 144.430 ;
            RECT 102.190 144.280 106.555 144.430 ;
            RECT 108.475 144.280 110.395 144.430 ;
            RECT 112.315 144.280 114.235 144.430 ;
            RECT 116.155 144.280 118.075 144.430 ;
            RECT 119.995 144.280 121.915 144.430 ;
            RECT 123.835 144.280 125.755 144.430 ;
            RECT 127.675 144.280 129.595 144.430 ;
            RECT 131.515 144.280 133.435 144.430 ;
            RECT 135.355 144.280 360.320 144.430 ;
            RECT 0.000 144.430 72.470 144.640 ;
            RECT 74.390 144.430 78.435 144.640 ;
            RECT 80.355 144.430 82.275 144.640 ;
            RECT 84.195 144.430 86.115 144.640 ;
            RECT 88.035 144.430 92.590 144.640 ;
            RECT 94.510 144.430 96.430 144.640 ;
            RECT 98.350 144.430 100.270 144.640 ;
            RECT 102.190 144.430 106.555 144.640 ;
            RECT 108.475 144.430 110.395 144.640 ;
            RECT 112.315 144.430 114.235 144.640 ;
            RECT 116.155 144.430 118.075 144.640 ;
            RECT 119.995 144.430 121.915 144.640 ;
            RECT 123.835 144.430 125.755 144.640 ;
            RECT 127.675 144.430 129.595 144.640 ;
            RECT 131.515 144.430 133.435 144.640 ;
            RECT 135.355 144.430 360.320 144.640 ;
            RECT 0.000 144.640 0.160 144.960 ;
            RECT 21.200 144.640 31.760 144.960 ;
            RECT 33.440 144.640 39.920 144.960 ;
            RECT 51.120 144.640 52.160 144.960 ;
            RECT 71.520 144.640 72.470 144.960 ;
            RECT 74.390 144.640 78.435 144.960 ;
            RECT 80.355 144.640 82.275 144.960 ;
            RECT 84.195 144.640 86.115 144.960 ;
            RECT 88.035 144.640 92.590 144.960 ;
            RECT 94.510 144.640 96.430 144.960 ;
            RECT 98.350 144.640 100.270 144.960 ;
            RECT 102.190 144.640 106.555 144.960 ;
            RECT 108.475 144.640 110.395 144.960 ;
            RECT 112.315 144.640 114.235 144.960 ;
            RECT 116.155 144.640 118.075 144.960 ;
            RECT 119.995 144.640 121.915 144.960 ;
            RECT 123.835 144.640 125.755 144.960 ;
            RECT 127.675 144.640 129.595 144.960 ;
            RECT 131.515 144.640 133.435 144.960 ;
            RECT 135.355 144.640 352.720 144.960 ;
            RECT 360.160 144.640 360.320 144.960 ;
            RECT 0.000 144.960 72.470 145.265 ;
            RECT 74.390 144.960 78.435 145.265 ;
            RECT 80.355 144.960 82.275 145.265 ;
            RECT 84.195 144.960 86.115 145.265 ;
            RECT 88.035 144.960 92.590 145.265 ;
            RECT 94.510 144.960 96.430 145.265 ;
            RECT 98.350 144.960 100.270 145.265 ;
            RECT 102.190 144.960 106.555 145.265 ;
            RECT 108.475 144.960 110.395 145.265 ;
            RECT 112.315 144.960 114.235 145.265 ;
            RECT 116.155 144.960 118.075 145.265 ;
            RECT 119.995 144.960 121.915 145.265 ;
            RECT 123.835 144.960 125.755 145.265 ;
            RECT 127.675 144.960 129.595 145.265 ;
            RECT 131.515 144.960 133.435 145.265 ;
            RECT 135.355 144.960 360.320 145.265 ;
            RECT 0.000 145.265 21.950 145.320 ;
            RECT 31.110 145.265 72.470 145.320 ;
            RECT 74.390 145.265 78.435 145.320 ;
            RECT 80.355 145.265 82.275 145.320 ;
            RECT 84.195 145.265 86.115 145.320 ;
            RECT 88.035 145.265 92.590 145.320 ;
            RECT 94.510 145.265 96.430 145.320 ;
            RECT 98.350 145.265 100.270 145.320 ;
            RECT 102.190 145.265 106.555 145.320 ;
            RECT 108.475 145.265 110.395 145.320 ;
            RECT 112.315 145.265 114.235 145.320 ;
            RECT 116.155 145.265 118.075 145.320 ;
            RECT 119.995 145.265 121.915 145.320 ;
            RECT 123.835 145.265 125.755 145.320 ;
            RECT 127.675 145.265 129.595 145.320 ;
            RECT 131.515 145.265 133.435 145.320 ;
            RECT 135.355 145.265 360.320 145.320 ;
            RECT 0.000 145.320 2.880 145.640 ;
            RECT 21.200 145.320 21.950 145.640 ;
            RECT 31.110 145.320 39.240 145.640 ;
            RECT 51.120 145.320 52.160 145.640 ;
            RECT 71.520 145.320 72.470 145.640 ;
            RECT 74.390 145.320 78.435 145.640 ;
            RECT 80.355 145.320 82.275 145.640 ;
            RECT 84.195 145.320 86.115 145.640 ;
            RECT 88.035 145.320 92.590 145.640 ;
            RECT 94.510 145.320 96.430 145.640 ;
            RECT 98.350 145.320 100.270 145.640 ;
            RECT 102.190 145.320 106.555 145.640 ;
            RECT 108.475 145.320 110.395 145.640 ;
            RECT 112.315 145.320 114.235 145.640 ;
            RECT 116.155 145.320 118.075 145.640 ;
            RECT 119.995 145.320 121.915 145.640 ;
            RECT 123.835 145.320 125.755 145.640 ;
            RECT 127.675 145.320 129.595 145.640 ;
            RECT 131.515 145.320 133.435 145.640 ;
            RECT 135.355 145.320 352.720 145.640 ;
            RECT 357.440 145.320 360.320 145.640 ;
            RECT 0.000 145.640 21.950 146.000 ;
            RECT 31.110 145.640 72.470 146.000 ;
            RECT 74.390 145.640 78.435 146.000 ;
            RECT 80.355 145.640 82.275 146.000 ;
            RECT 84.195 145.640 86.115 146.000 ;
            RECT 88.035 145.640 92.590 146.000 ;
            RECT 94.510 145.640 96.430 146.000 ;
            RECT 98.350 145.640 100.270 146.000 ;
            RECT 102.190 145.640 106.555 146.000 ;
            RECT 108.475 145.640 110.395 146.000 ;
            RECT 112.315 145.640 114.235 146.000 ;
            RECT 116.155 145.640 118.075 146.000 ;
            RECT 119.995 145.640 121.915 146.000 ;
            RECT 123.835 145.640 125.755 146.000 ;
            RECT 127.675 145.640 129.595 146.000 ;
            RECT 131.515 145.640 133.435 146.000 ;
            RECT 135.355 145.640 360.320 146.000 ;
            RECT 0.000 146.000 0.160 146.015 ;
            RECT 21.200 146.000 21.950 146.015 ;
            RECT 31.110 146.000 31.760 146.015 ;
            RECT 51.120 146.000 54.880 146.015 ;
            RECT 71.520 146.000 72.470 146.015 ;
            RECT 74.390 146.000 78.435 146.015 ;
            RECT 80.355 146.000 82.275 146.015 ;
            RECT 84.195 146.000 86.115 146.015 ;
            RECT 88.035 146.000 92.590 146.015 ;
            RECT 94.510 146.000 96.430 146.015 ;
            RECT 98.350 146.000 100.270 146.015 ;
            RECT 102.190 146.000 106.555 146.015 ;
            RECT 108.475 146.000 110.395 146.015 ;
            RECT 112.315 146.000 114.235 146.015 ;
            RECT 116.155 146.000 118.075 146.015 ;
            RECT 119.995 146.000 121.915 146.015 ;
            RECT 123.835 146.000 125.755 146.015 ;
            RECT 127.675 146.000 129.595 146.015 ;
            RECT 131.515 146.000 133.435 146.015 ;
            RECT 135.355 146.000 352.720 146.015 ;
            RECT 360.160 146.000 360.320 146.015 ;
            RECT 0.000 146.015 0.160 146.320 ;
            RECT 21.200 146.015 31.760 146.320 ;
            RECT 51.120 146.015 54.880 146.320 ;
            RECT 71.520 146.015 72.470 146.320 ;
            RECT 74.390 146.015 78.435 146.320 ;
            RECT 80.355 146.015 82.275 146.320 ;
            RECT 84.195 146.015 86.115 146.320 ;
            RECT 88.035 146.015 92.590 146.320 ;
            RECT 94.510 146.015 96.430 146.320 ;
            RECT 98.350 146.015 100.270 146.320 ;
            RECT 102.190 146.015 106.555 146.320 ;
            RECT 108.475 146.015 110.395 146.320 ;
            RECT 112.315 146.015 114.235 146.320 ;
            RECT 116.155 146.015 118.075 146.320 ;
            RECT 119.995 146.015 121.915 146.320 ;
            RECT 123.835 146.015 125.755 146.320 ;
            RECT 127.675 146.015 129.595 146.320 ;
            RECT 131.515 146.015 133.435 146.320 ;
            RECT 135.355 146.015 352.720 146.320 ;
            RECT 360.160 146.015 360.320 146.320 ;
            RECT 0.000 146.320 72.470 146.680 ;
            RECT 74.390 146.320 78.435 146.680 ;
            RECT 80.355 146.320 82.275 146.680 ;
            RECT 84.195 146.320 86.115 146.680 ;
            RECT 88.035 146.320 92.590 146.680 ;
            RECT 94.510 146.320 96.430 146.680 ;
            RECT 98.350 146.320 100.270 146.680 ;
            RECT 102.190 146.320 106.555 146.680 ;
            RECT 108.475 146.320 110.395 146.680 ;
            RECT 112.315 146.320 114.235 146.680 ;
            RECT 116.155 146.320 118.075 146.680 ;
            RECT 119.995 146.320 121.915 146.680 ;
            RECT 123.835 146.320 125.755 146.680 ;
            RECT 127.675 146.320 129.595 146.680 ;
            RECT 131.515 146.320 133.435 146.680 ;
            RECT 135.355 146.320 360.320 146.680 ;
            RECT 0.000 146.680 2.880 147.000 ;
            RECT 51.120 146.680 52.160 147.000 ;
            RECT 71.520 146.680 72.470 147.000 ;
            RECT 74.390 146.680 78.435 147.000 ;
            RECT 80.355 146.680 82.275 147.000 ;
            RECT 84.195 146.680 86.115 147.000 ;
            RECT 88.035 146.680 92.590 147.000 ;
            RECT 94.510 146.680 96.430 147.000 ;
            RECT 98.350 146.680 100.270 147.000 ;
            RECT 102.190 146.680 106.555 147.000 ;
            RECT 108.475 146.680 110.395 147.000 ;
            RECT 112.315 146.680 114.235 147.000 ;
            RECT 116.155 146.680 118.075 147.000 ;
            RECT 119.995 146.680 121.915 147.000 ;
            RECT 123.835 146.680 125.755 147.000 ;
            RECT 127.675 146.680 129.595 147.000 ;
            RECT 131.515 146.680 133.435 147.000 ;
            RECT 135.355 146.680 352.720 147.000 ;
            RECT 357.440 146.680 360.320 147.000 ;
            RECT 0.000 147.000 72.470 147.360 ;
            RECT 74.390 147.000 78.435 147.360 ;
            RECT 80.355 147.000 82.275 147.360 ;
            RECT 84.195 147.000 86.115 147.360 ;
            RECT 88.035 147.000 92.590 147.360 ;
            RECT 94.510 147.000 96.430 147.360 ;
            RECT 98.350 147.000 100.270 147.360 ;
            RECT 102.190 147.000 106.555 147.360 ;
            RECT 108.475 147.000 110.395 147.360 ;
            RECT 112.315 147.000 114.235 147.360 ;
            RECT 116.155 147.000 118.075 147.360 ;
            RECT 119.995 147.000 121.915 147.360 ;
            RECT 123.835 147.000 125.755 147.360 ;
            RECT 127.675 147.000 129.595 147.360 ;
            RECT 131.515 147.000 133.435 147.360 ;
            RECT 135.355 147.000 360.320 147.360 ;
            RECT 0.000 147.360 0.160 147.395 ;
            RECT 21.200 147.360 31.760 147.395 ;
            RECT 51.120 147.360 55.560 147.395 ;
            RECT 71.520 147.360 72.470 147.395 ;
            RECT 74.390 147.360 78.435 147.395 ;
            RECT 80.355 147.360 82.275 147.395 ;
            RECT 84.195 147.360 86.115 147.395 ;
            RECT 88.035 147.360 92.590 147.395 ;
            RECT 94.510 147.360 96.430 147.395 ;
            RECT 98.350 147.360 100.270 147.395 ;
            RECT 102.190 147.360 106.555 147.395 ;
            RECT 108.475 147.360 110.395 147.395 ;
            RECT 112.315 147.360 114.235 147.395 ;
            RECT 116.155 147.360 118.075 147.395 ;
            RECT 119.995 147.360 121.915 147.395 ;
            RECT 123.835 147.360 125.755 147.395 ;
            RECT 127.675 147.360 129.595 147.395 ;
            RECT 131.515 147.360 133.435 147.395 ;
            RECT 135.355 147.360 352.720 147.395 ;
            RECT 360.160 147.360 360.320 147.395 ;
            RECT 0.000 147.395 0.160 147.680 ;
            RECT 21.200 147.395 21.950 147.680 ;
            RECT 31.110 147.395 31.760 147.680 ;
            RECT 51.120 147.395 55.560 147.680 ;
            RECT 71.520 147.395 72.470 147.680 ;
            RECT 74.390 147.395 78.435 147.680 ;
            RECT 80.355 147.395 82.275 147.680 ;
            RECT 84.195 147.395 86.115 147.680 ;
            RECT 88.035 147.395 92.590 147.680 ;
            RECT 94.510 147.395 96.430 147.680 ;
            RECT 98.350 147.395 100.270 147.680 ;
            RECT 102.190 147.395 106.555 147.680 ;
            RECT 108.475 147.395 110.395 147.680 ;
            RECT 112.315 147.395 114.235 147.680 ;
            RECT 116.155 147.395 118.075 147.680 ;
            RECT 119.995 147.395 121.915 147.680 ;
            RECT 123.835 147.395 125.755 147.680 ;
            RECT 127.675 147.395 129.595 147.680 ;
            RECT 131.515 147.395 133.435 147.680 ;
            RECT 135.355 147.395 352.720 147.680 ;
            RECT 360.160 147.395 360.320 147.680 ;
            RECT 0.000 147.680 21.950 148.040 ;
            RECT 31.110 147.680 72.470 148.040 ;
            RECT 74.390 147.680 78.435 148.040 ;
            RECT 80.355 147.680 82.275 148.040 ;
            RECT 84.195 147.680 86.115 148.040 ;
            RECT 88.035 147.680 92.590 148.040 ;
            RECT 94.510 147.680 96.430 148.040 ;
            RECT 98.350 147.680 100.270 148.040 ;
            RECT 102.190 147.680 106.555 148.040 ;
            RECT 108.475 147.680 110.395 148.040 ;
            RECT 112.315 147.680 114.235 148.040 ;
            RECT 116.155 147.680 118.075 148.040 ;
            RECT 119.995 147.680 121.915 148.040 ;
            RECT 123.835 147.680 125.755 148.040 ;
            RECT 127.675 147.680 129.595 148.040 ;
            RECT 131.515 147.680 133.435 148.040 ;
            RECT 135.355 147.680 360.320 148.040 ;
            RECT 0.000 148.040 2.880 148.285 ;
            RECT 21.200 148.040 21.950 148.285 ;
            RECT 31.110 148.040 31.760 148.285 ;
            RECT 51.120 148.040 55.560 148.285 ;
            RECT 71.520 148.040 72.470 148.285 ;
            RECT 74.390 148.040 78.435 148.285 ;
            RECT 80.355 148.040 82.275 148.285 ;
            RECT 84.195 148.040 86.115 148.285 ;
            RECT 88.035 148.040 92.590 148.285 ;
            RECT 94.510 148.040 96.430 148.285 ;
            RECT 98.350 148.040 100.270 148.285 ;
            RECT 102.190 148.040 106.555 148.285 ;
            RECT 108.475 148.040 110.395 148.285 ;
            RECT 112.315 148.040 114.235 148.285 ;
            RECT 116.155 148.040 118.075 148.285 ;
            RECT 119.995 148.040 121.915 148.285 ;
            RECT 123.835 148.040 125.755 148.285 ;
            RECT 127.675 148.040 129.595 148.285 ;
            RECT 131.515 148.040 133.435 148.285 ;
            RECT 135.355 148.040 352.720 148.285 ;
            RECT 357.440 148.040 360.320 148.285 ;
            RECT 0.000 148.285 2.880 148.360 ;
            RECT 21.200 148.285 31.760 148.360 ;
            RECT 51.120 148.285 55.560 148.360 ;
            RECT 71.520 148.285 72.470 148.360 ;
            RECT 74.390 148.285 78.435 148.360 ;
            RECT 80.355 148.285 82.275 148.360 ;
            RECT 84.195 148.285 86.115 148.360 ;
            RECT 88.035 148.285 92.590 148.360 ;
            RECT 94.510 148.285 96.430 148.360 ;
            RECT 98.350 148.285 100.270 148.360 ;
            RECT 102.190 148.285 106.555 148.360 ;
            RECT 108.475 148.285 110.395 148.360 ;
            RECT 112.315 148.285 114.235 148.360 ;
            RECT 116.155 148.285 118.075 148.360 ;
            RECT 119.995 148.285 121.915 148.360 ;
            RECT 123.835 148.285 125.755 148.360 ;
            RECT 127.675 148.285 129.595 148.360 ;
            RECT 131.515 148.285 133.435 148.360 ;
            RECT 135.355 148.285 352.720 148.360 ;
            RECT 357.440 148.285 360.320 148.360 ;
            RECT 0.000 148.360 72.470 148.720 ;
            RECT 74.390 148.360 78.435 148.720 ;
            RECT 80.355 148.360 82.275 148.720 ;
            RECT 84.195 148.360 86.115 148.720 ;
            RECT 88.035 148.360 92.590 148.720 ;
            RECT 94.510 148.360 96.430 148.720 ;
            RECT 98.350 148.360 100.270 148.720 ;
            RECT 102.190 148.360 106.555 148.720 ;
            RECT 108.475 148.360 110.395 148.720 ;
            RECT 112.315 148.360 114.235 148.720 ;
            RECT 116.155 148.360 118.075 148.720 ;
            RECT 119.995 148.360 121.915 148.720 ;
            RECT 123.835 148.360 125.755 148.720 ;
            RECT 127.675 148.360 129.595 148.720 ;
            RECT 131.515 148.360 133.435 148.720 ;
            RECT 135.355 148.360 360.320 148.720 ;
            RECT 0.000 148.720 0.160 149.040 ;
            RECT 51.120 148.720 55.560 149.040 ;
            RECT 71.520 148.720 72.470 149.040 ;
            RECT 74.390 148.720 78.435 149.040 ;
            RECT 80.355 148.720 82.275 149.040 ;
            RECT 84.195 148.720 86.115 149.040 ;
            RECT 88.035 148.720 92.590 149.040 ;
            RECT 94.510 148.720 96.430 149.040 ;
            RECT 98.350 148.720 100.270 149.040 ;
            RECT 102.190 148.720 106.555 149.040 ;
            RECT 108.475 148.720 110.395 149.040 ;
            RECT 112.315 148.720 114.235 149.040 ;
            RECT 116.155 148.720 118.075 149.040 ;
            RECT 119.995 148.720 121.915 149.040 ;
            RECT 123.835 148.720 125.755 149.040 ;
            RECT 127.675 148.720 129.595 149.040 ;
            RECT 131.515 148.720 133.435 149.040 ;
            RECT 135.355 148.720 352.720 149.040 ;
            RECT 360.160 148.720 360.320 149.040 ;
            RECT 0.000 149.040 72.470 149.400 ;
            RECT 74.390 149.040 78.435 149.400 ;
            RECT 80.355 149.040 82.275 149.400 ;
            RECT 84.195 149.040 86.115 149.400 ;
            RECT 88.035 149.040 92.590 149.400 ;
            RECT 94.510 149.040 96.430 149.400 ;
            RECT 98.350 149.040 100.270 149.400 ;
            RECT 102.190 149.040 106.555 149.400 ;
            RECT 108.475 149.040 110.395 149.400 ;
            RECT 112.315 149.040 114.235 149.400 ;
            RECT 116.155 149.040 118.075 149.400 ;
            RECT 119.995 149.040 121.915 149.400 ;
            RECT 123.835 149.040 125.755 149.400 ;
            RECT 127.675 149.040 129.595 149.400 ;
            RECT 131.515 149.040 133.435 149.400 ;
            RECT 135.355 149.040 360.320 149.400 ;
            RECT 0.000 149.400 2.880 149.720 ;
            RECT 21.200 149.400 31.760 149.720 ;
            RECT 51.120 149.400 55.560 149.720 ;
            RECT 71.520 149.400 72.470 149.720 ;
            RECT 74.390 149.400 78.435 149.720 ;
            RECT 80.355 149.400 82.275 149.720 ;
            RECT 84.195 149.400 86.115 149.720 ;
            RECT 88.035 149.400 92.590 149.720 ;
            RECT 94.510 149.400 96.430 149.720 ;
            RECT 98.350 149.400 100.270 149.720 ;
            RECT 102.190 149.400 106.555 149.720 ;
            RECT 108.475 149.400 110.395 149.720 ;
            RECT 112.315 149.400 114.235 149.720 ;
            RECT 116.155 149.400 118.075 149.720 ;
            RECT 119.995 149.400 121.915 149.720 ;
            RECT 123.835 149.400 125.755 149.720 ;
            RECT 127.675 149.400 129.595 149.720 ;
            RECT 131.515 149.400 133.435 149.720 ;
            RECT 135.355 149.400 352.720 149.720 ;
            RECT 357.440 149.400 360.320 149.720 ;
            RECT 0.000 149.720 72.470 149.890 ;
            RECT 74.390 149.720 78.435 149.890 ;
            RECT 80.355 149.720 82.275 149.890 ;
            RECT 84.195 149.720 86.115 149.890 ;
            RECT 88.035 149.720 92.590 149.890 ;
            RECT 94.510 149.720 96.430 149.890 ;
            RECT 98.350 149.720 100.270 149.890 ;
            RECT 102.190 149.720 106.555 149.890 ;
            RECT 108.475 149.720 110.395 149.890 ;
            RECT 112.315 149.720 114.235 149.890 ;
            RECT 116.155 149.720 118.075 149.890 ;
            RECT 119.995 149.720 121.915 149.890 ;
            RECT 123.835 149.720 125.755 149.890 ;
            RECT 127.675 149.720 129.595 149.890 ;
            RECT 131.515 149.720 133.435 149.890 ;
            RECT 135.355 149.720 360.320 149.890 ;
            RECT 0.000 149.890 21.950 150.080 ;
            RECT 31.110 149.890 72.470 150.080 ;
            RECT 74.390 149.890 78.435 150.080 ;
            RECT 80.355 149.890 82.275 150.080 ;
            RECT 84.195 149.890 86.115 150.080 ;
            RECT 88.035 149.890 92.590 150.080 ;
            RECT 94.510 149.890 96.430 150.080 ;
            RECT 98.350 149.890 100.270 150.080 ;
            RECT 102.190 149.890 106.555 150.080 ;
            RECT 108.475 149.890 110.395 150.080 ;
            RECT 112.315 149.890 114.235 150.080 ;
            RECT 116.155 149.890 118.075 150.080 ;
            RECT 119.995 149.890 121.915 150.080 ;
            RECT 123.835 149.890 125.755 150.080 ;
            RECT 127.675 149.890 129.595 150.080 ;
            RECT 131.515 149.890 133.435 150.080 ;
            RECT 135.355 149.890 360.320 150.080 ;
            RECT 0.000 150.080 0.160 150.400 ;
            RECT 21.200 150.080 21.950 150.400 ;
            RECT 31.110 150.080 31.760 150.400 ;
            RECT 51.120 150.080 52.160 150.400 ;
            RECT 71.520 150.080 72.470 150.400 ;
            RECT 74.390 150.080 78.435 150.400 ;
            RECT 80.355 150.080 82.275 150.400 ;
            RECT 84.195 150.080 86.115 150.400 ;
            RECT 88.035 150.080 92.590 150.400 ;
            RECT 94.510 150.080 96.430 150.400 ;
            RECT 98.350 150.080 100.270 150.400 ;
            RECT 102.190 150.080 106.555 150.400 ;
            RECT 108.475 150.080 110.395 150.400 ;
            RECT 112.315 150.080 114.235 150.400 ;
            RECT 116.155 150.080 118.075 150.400 ;
            RECT 119.995 150.080 121.915 150.400 ;
            RECT 123.835 150.080 125.755 150.400 ;
            RECT 127.675 150.080 129.595 150.400 ;
            RECT 131.515 150.080 133.435 150.400 ;
            RECT 135.355 150.080 352.720 150.400 ;
            RECT 360.160 150.080 360.320 150.400 ;
            RECT 0.000 150.400 21.950 150.760 ;
            RECT 31.110 150.400 72.470 150.760 ;
            RECT 74.390 150.400 78.435 150.760 ;
            RECT 80.355 150.400 82.275 150.760 ;
            RECT 84.195 150.400 86.115 150.760 ;
            RECT 88.035 150.400 92.590 150.760 ;
            RECT 94.510 150.400 96.430 150.760 ;
            RECT 98.350 150.400 100.270 150.760 ;
            RECT 102.190 150.400 106.555 150.760 ;
            RECT 108.475 150.400 110.395 150.760 ;
            RECT 112.315 150.400 114.235 150.760 ;
            RECT 116.155 150.400 118.075 150.760 ;
            RECT 119.995 150.400 121.915 150.760 ;
            RECT 123.835 150.400 125.755 150.760 ;
            RECT 127.675 150.400 129.595 150.760 ;
            RECT 131.515 150.400 133.435 150.760 ;
            RECT 135.355 150.400 360.320 150.760 ;
            RECT 0.000 150.760 2.880 151.080 ;
            RECT 21.200 150.760 21.950 151.080 ;
            RECT 31.110 150.760 31.760 151.080 ;
            RECT 51.120 150.760 56.240 151.080 ;
            RECT 71.520 150.760 72.470 151.080 ;
            RECT 74.390 150.760 78.435 151.080 ;
            RECT 80.355 150.760 82.275 151.080 ;
            RECT 84.195 150.760 86.115 151.080 ;
            RECT 88.035 150.760 92.590 151.080 ;
            RECT 94.510 150.760 96.430 151.080 ;
            RECT 98.350 150.760 100.270 151.080 ;
            RECT 102.190 150.760 106.555 151.080 ;
            RECT 108.475 150.760 110.395 151.080 ;
            RECT 112.315 150.760 114.235 151.080 ;
            RECT 116.155 150.760 118.075 151.080 ;
            RECT 119.995 150.760 121.915 151.080 ;
            RECT 123.835 150.760 125.755 151.080 ;
            RECT 127.675 150.760 129.595 151.080 ;
            RECT 131.515 150.760 133.435 151.080 ;
            RECT 135.355 150.760 352.720 151.080 ;
            RECT 357.440 150.760 360.320 151.080 ;
            RECT 0.000 151.080 21.950 151.440 ;
            RECT 31.110 151.080 72.470 151.440 ;
            RECT 74.390 151.080 78.435 151.440 ;
            RECT 80.355 151.080 82.275 151.440 ;
            RECT 84.195 151.080 86.115 151.440 ;
            RECT 88.035 151.080 92.590 151.440 ;
            RECT 94.510 151.080 96.430 151.440 ;
            RECT 98.350 151.080 100.270 151.440 ;
            RECT 102.190 151.080 106.555 151.440 ;
            RECT 108.475 151.080 110.395 151.440 ;
            RECT 112.315 151.080 114.235 151.440 ;
            RECT 116.155 151.080 118.075 151.440 ;
            RECT 119.995 151.080 121.915 151.440 ;
            RECT 123.835 151.080 125.755 151.440 ;
            RECT 127.675 151.080 129.595 151.440 ;
            RECT 131.515 151.080 133.435 151.440 ;
            RECT 135.355 151.080 360.320 151.440 ;
            RECT 0.000 151.440 0.160 151.640 ;
            RECT 21.200 151.440 21.950 151.640 ;
            RECT 31.110 151.440 31.760 151.640 ;
            RECT 71.520 151.440 72.470 151.640 ;
            RECT 74.390 151.440 78.435 151.640 ;
            RECT 80.355 151.440 82.275 151.640 ;
            RECT 84.195 151.440 86.115 151.640 ;
            RECT 88.035 151.440 92.590 151.640 ;
            RECT 94.510 151.440 96.430 151.640 ;
            RECT 98.350 151.440 100.270 151.640 ;
            RECT 102.190 151.440 106.555 151.640 ;
            RECT 108.475 151.440 110.395 151.640 ;
            RECT 112.315 151.440 114.235 151.640 ;
            RECT 116.155 151.440 118.075 151.640 ;
            RECT 119.995 151.440 121.915 151.640 ;
            RECT 123.835 151.440 125.755 151.640 ;
            RECT 127.675 151.440 129.595 151.640 ;
            RECT 131.515 151.440 133.435 151.640 ;
            RECT 135.355 151.440 352.720 151.640 ;
            RECT 360.160 151.440 360.320 151.640 ;
            RECT 0.000 151.640 0.160 151.760 ;
            RECT 21.200 151.640 31.760 151.760 ;
            RECT 71.520 151.640 72.470 151.760 ;
            RECT 74.390 151.640 78.435 151.760 ;
            RECT 80.355 151.640 82.275 151.760 ;
            RECT 84.195 151.640 86.115 151.760 ;
            RECT 88.035 151.640 92.590 151.760 ;
            RECT 94.510 151.640 96.430 151.760 ;
            RECT 98.350 151.640 100.270 151.760 ;
            RECT 102.190 151.640 106.555 151.760 ;
            RECT 108.475 151.640 110.395 151.760 ;
            RECT 112.315 151.640 114.235 151.760 ;
            RECT 116.155 151.640 118.075 151.760 ;
            RECT 119.995 151.640 121.915 151.760 ;
            RECT 123.835 151.640 125.755 151.760 ;
            RECT 127.675 151.640 129.595 151.760 ;
            RECT 131.515 151.640 133.435 151.760 ;
            RECT 135.355 151.640 352.720 151.760 ;
            RECT 360.160 151.640 360.320 151.760 ;
            RECT 0.000 151.760 72.470 152.120 ;
            RECT 74.390 151.760 78.435 152.120 ;
            RECT 80.355 151.760 82.275 152.120 ;
            RECT 84.195 151.760 86.115 152.120 ;
            RECT 88.035 151.760 92.590 152.120 ;
            RECT 94.510 151.760 96.430 152.120 ;
            RECT 98.350 151.760 100.270 152.120 ;
            RECT 102.190 151.760 106.555 152.120 ;
            RECT 108.475 151.760 110.395 152.120 ;
            RECT 112.315 151.760 114.235 152.120 ;
            RECT 116.155 151.760 118.075 152.120 ;
            RECT 119.995 151.760 121.915 152.120 ;
            RECT 123.835 151.760 125.755 152.120 ;
            RECT 127.675 151.760 129.595 152.120 ;
            RECT 131.515 151.760 133.435 152.120 ;
            RECT 135.355 151.760 360.320 152.120 ;
            RECT 0.000 152.120 2.880 152.440 ;
            RECT 71.520 152.120 72.470 152.440 ;
            RECT 74.390 152.120 78.435 152.440 ;
            RECT 80.355 152.120 82.275 152.440 ;
            RECT 84.195 152.120 86.115 152.440 ;
            RECT 88.035 152.120 92.590 152.440 ;
            RECT 94.510 152.120 96.430 152.440 ;
            RECT 98.350 152.120 100.270 152.440 ;
            RECT 102.190 152.120 106.555 152.440 ;
            RECT 108.475 152.120 110.395 152.440 ;
            RECT 112.315 152.120 114.235 152.440 ;
            RECT 116.155 152.120 118.075 152.440 ;
            RECT 119.995 152.120 121.915 152.440 ;
            RECT 123.835 152.120 125.755 152.440 ;
            RECT 127.675 152.120 129.595 152.440 ;
            RECT 131.515 152.120 133.435 152.440 ;
            RECT 135.355 152.120 352.720 152.440 ;
            RECT 357.440 152.120 360.320 152.440 ;
            RECT 0.000 152.440 72.470 152.800 ;
            RECT 74.390 152.440 78.435 152.800 ;
            RECT 80.355 152.440 82.275 152.800 ;
            RECT 84.195 152.440 86.115 152.800 ;
            RECT 88.035 152.440 92.590 152.800 ;
            RECT 94.510 152.440 96.430 152.800 ;
            RECT 98.350 152.440 100.270 152.800 ;
            RECT 102.190 152.440 106.555 152.800 ;
            RECT 108.475 152.440 110.395 152.800 ;
            RECT 112.315 152.440 114.235 152.800 ;
            RECT 116.155 152.440 118.075 152.800 ;
            RECT 119.995 152.440 121.915 152.800 ;
            RECT 123.835 152.440 125.755 152.800 ;
            RECT 127.675 152.440 129.595 152.800 ;
            RECT 131.515 152.440 133.435 152.800 ;
            RECT 135.355 152.440 360.320 152.800 ;
            RECT 0.000 152.800 0.160 153.120 ;
            RECT 71.520 152.800 72.470 153.120 ;
            RECT 74.390 152.800 78.435 153.120 ;
            RECT 80.355 152.800 82.275 153.120 ;
            RECT 84.195 152.800 86.115 153.120 ;
            RECT 88.035 152.800 92.590 153.120 ;
            RECT 94.510 152.800 96.430 153.120 ;
            RECT 98.350 152.800 100.270 153.120 ;
            RECT 102.190 152.800 106.555 153.120 ;
            RECT 108.475 152.800 110.395 153.120 ;
            RECT 112.315 152.800 114.235 153.120 ;
            RECT 116.155 152.800 118.075 153.120 ;
            RECT 119.995 152.800 121.915 153.120 ;
            RECT 123.835 152.800 125.755 153.120 ;
            RECT 127.675 152.800 129.595 153.120 ;
            RECT 131.515 152.800 133.435 153.120 ;
            RECT 135.355 152.800 352.720 153.120 ;
            RECT 360.160 152.800 360.320 153.120 ;
            RECT 0.000 153.120 72.470 153.480 ;
            RECT 74.390 153.120 78.435 153.480 ;
            RECT 80.355 153.120 82.275 153.480 ;
            RECT 84.195 153.120 86.115 153.480 ;
            RECT 88.035 153.120 92.590 153.480 ;
            RECT 94.510 153.120 96.430 153.480 ;
            RECT 98.350 153.120 100.270 153.480 ;
            RECT 102.190 153.120 106.555 153.480 ;
            RECT 108.475 153.120 110.395 153.480 ;
            RECT 112.315 153.120 114.235 153.480 ;
            RECT 116.155 153.120 118.075 153.480 ;
            RECT 119.995 153.120 121.915 153.480 ;
            RECT 123.835 153.120 125.755 153.480 ;
            RECT 127.675 153.120 129.595 153.480 ;
            RECT 131.515 153.120 133.435 153.480 ;
            RECT 135.355 153.120 360.320 153.480 ;
            RECT 0.000 153.480 2.880 153.800 ;
            RECT 71.520 153.480 72.470 153.800 ;
            RECT 74.390 153.480 78.435 153.800 ;
            RECT 80.355 153.480 82.275 153.800 ;
            RECT 84.195 153.480 86.115 153.800 ;
            RECT 88.035 153.480 92.590 153.800 ;
            RECT 94.510 153.480 96.430 153.800 ;
            RECT 98.350 153.480 100.270 153.800 ;
            RECT 102.190 153.480 106.555 153.800 ;
            RECT 108.475 153.480 110.395 153.800 ;
            RECT 112.315 153.480 114.235 153.800 ;
            RECT 116.155 153.480 118.075 153.800 ;
            RECT 119.995 153.480 121.915 153.800 ;
            RECT 123.835 153.480 125.755 153.800 ;
            RECT 127.675 153.480 129.595 153.800 ;
            RECT 131.515 153.480 133.435 153.800 ;
            RECT 135.355 153.480 352.720 153.800 ;
            RECT 357.440 153.480 360.320 153.800 ;
            RECT 0.000 153.800 72.470 154.160 ;
            RECT 74.390 153.800 78.435 154.160 ;
            RECT 80.355 153.800 82.275 154.160 ;
            RECT 84.195 153.800 86.115 154.160 ;
            RECT 88.035 153.800 92.590 154.160 ;
            RECT 94.510 153.800 96.430 154.160 ;
            RECT 98.350 153.800 100.270 154.160 ;
            RECT 102.190 153.800 106.555 154.160 ;
            RECT 108.475 153.800 110.395 154.160 ;
            RECT 112.315 153.800 114.235 154.160 ;
            RECT 116.155 153.800 118.075 154.160 ;
            RECT 119.995 153.800 121.915 154.160 ;
            RECT 123.835 153.800 125.755 154.160 ;
            RECT 127.675 153.800 129.595 154.160 ;
            RECT 131.515 153.800 133.435 154.160 ;
            RECT 135.355 153.800 360.320 154.160 ;
            RECT 0.000 154.160 0.160 154.480 ;
            RECT 71.520 154.160 72.470 154.480 ;
            RECT 74.390 154.160 78.435 154.480 ;
            RECT 80.355 154.160 82.275 154.480 ;
            RECT 84.195 154.160 86.115 154.480 ;
            RECT 88.035 154.160 92.590 154.480 ;
            RECT 94.510 154.160 96.430 154.480 ;
            RECT 98.350 154.160 100.270 154.480 ;
            RECT 102.190 154.160 106.555 154.480 ;
            RECT 108.475 154.160 110.395 154.480 ;
            RECT 112.315 154.160 114.235 154.480 ;
            RECT 116.155 154.160 118.075 154.480 ;
            RECT 119.995 154.160 121.915 154.480 ;
            RECT 123.835 154.160 125.755 154.480 ;
            RECT 127.675 154.160 129.595 154.480 ;
            RECT 131.515 154.160 133.435 154.480 ;
            RECT 135.355 154.160 352.720 154.480 ;
            RECT 360.160 154.160 360.320 154.480 ;
            RECT 0.000 154.480 72.470 154.840 ;
            RECT 74.390 154.480 78.435 154.840 ;
            RECT 80.355 154.480 82.275 154.840 ;
            RECT 84.195 154.480 86.115 154.840 ;
            RECT 88.035 154.480 92.590 154.840 ;
            RECT 94.510 154.480 96.430 154.840 ;
            RECT 98.350 154.480 100.270 154.840 ;
            RECT 102.190 154.480 106.555 154.840 ;
            RECT 108.475 154.480 110.395 154.840 ;
            RECT 112.315 154.480 114.235 154.840 ;
            RECT 116.155 154.480 118.075 154.840 ;
            RECT 119.995 154.480 121.915 154.840 ;
            RECT 123.835 154.480 125.755 154.840 ;
            RECT 127.675 154.480 129.595 154.840 ;
            RECT 131.515 154.480 133.435 154.840 ;
            RECT 135.355 154.480 360.320 154.840 ;
            RECT 0.000 154.840 2.880 155.160 ;
            RECT 71.520 154.840 72.470 155.160 ;
            RECT 74.390 154.840 78.435 155.160 ;
            RECT 80.355 154.840 82.275 155.160 ;
            RECT 84.195 154.840 86.115 155.160 ;
            RECT 88.035 154.840 92.590 155.160 ;
            RECT 94.510 154.840 96.430 155.160 ;
            RECT 98.350 154.840 100.270 155.160 ;
            RECT 102.190 154.840 106.555 155.160 ;
            RECT 108.475 154.840 110.395 155.160 ;
            RECT 112.315 154.840 114.235 155.160 ;
            RECT 116.155 154.840 118.075 155.160 ;
            RECT 119.995 154.840 121.915 155.160 ;
            RECT 123.835 154.840 125.755 155.160 ;
            RECT 127.675 154.840 129.595 155.160 ;
            RECT 131.515 154.840 133.435 155.160 ;
            RECT 135.355 154.840 352.720 155.160 ;
            RECT 357.440 154.840 360.320 155.160 ;
            RECT 0.000 155.160 72.470 155.520 ;
            RECT 74.390 155.160 78.435 155.520 ;
            RECT 80.355 155.160 82.275 155.520 ;
            RECT 84.195 155.160 86.115 155.520 ;
            RECT 88.035 155.160 92.590 155.520 ;
            RECT 94.510 155.160 96.430 155.520 ;
            RECT 98.350 155.160 100.270 155.520 ;
            RECT 102.190 155.160 106.555 155.520 ;
            RECT 108.475 155.160 110.395 155.520 ;
            RECT 112.315 155.160 114.235 155.520 ;
            RECT 116.155 155.160 118.075 155.520 ;
            RECT 119.995 155.160 121.915 155.520 ;
            RECT 123.835 155.160 125.755 155.520 ;
            RECT 127.675 155.160 129.595 155.520 ;
            RECT 131.515 155.160 133.435 155.520 ;
            RECT 135.355 155.160 360.320 155.520 ;
            RECT 0.000 155.520 0.160 155.840 ;
            RECT 14.400 155.520 16.800 155.840 ;
            RECT 71.520 155.520 72.470 155.840 ;
            RECT 74.390 155.520 78.435 155.840 ;
            RECT 80.355 155.520 82.275 155.840 ;
            RECT 84.195 155.520 86.115 155.840 ;
            RECT 88.035 155.520 92.590 155.840 ;
            RECT 94.510 155.520 96.430 155.840 ;
            RECT 98.350 155.520 100.270 155.840 ;
            RECT 102.190 155.520 106.555 155.840 ;
            RECT 108.475 155.520 110.395 155.840 ;
            RECT 112.315 155.520 114.235 155.840 ;
            RECT 116.155 155.520 118.075 155.840 ;
            RECT 119.995 155.520 121.915 155.840 ;
            RECT 123.835 155.520 125.755 155.840 ;
            RECT 127.675 155.520 129.595 155.840 ;
            RECT 131.515 155.520 133.435 155.840 ;
            RECT 135.355 155.520 352.720 155.840 ;
            RECT 360.160 155.520 360.320 155.840 ;
            RECT 0.000 155.840 72.470 156.200 ;
            RECT 74.390 155.840 78.435 156.200 ;
            RECT 80.355 155.840 82.275 156.200 ;
            RECT 84.195 155.840 86.115 156.200 ;
            RECT 88.035 155.840 92.590 156.200 ;
            RECT 94.510 155.840 96.430 156.200 ;
            RECT 98.350 155.840 100.270 156.200 ;
            RECT 102.190 155.840 106.555 156.200 ;
            RECT 108.475 155.840 110.395 156.200 ;
            RECT 112.315 155.840 114.235 156.200 ;
            RECT 116.155 155.840 118.075 156.200 ;
            RECT 119.995 155.840 121.915 156.200 ;
            RECT 123.835 155.840 125.755 156.200 ;
            RECT 127.675 155.840 129.595 156.200 ;
            RECT 131.515 155.840 133.435 156.200 ;
            RECT 135.355 155.840 360.320 156.200 ;
            RECT 0.000 156.200 2.880 156.520 ;
            RECT 14.400 156.200 16.800 156.520 ;
            RECT 30.040 156.200 33.120 156.520 ;
            RECT 71.520 156.200 72.470 156.520 ;
            RECT 74.390 156.200 78.435 156.520 ;
            RECT 80.355 156.200 82.275 156.520 ;
            RECT 84.195 156.200 86.115 156.520 ;
            RECT 88.035 156.200 92.590 156.520 ;
            RECT 94.510 156.200 96.430 156.520 ;
            RECT 98.350 156.200 100.270 156.520 ;
            RECT 102.190 156.200 106.555 156.520 ;
            RECT 108.475 156.200 110.395 156.520 ;
            RECT 112.315 156.200 114.235 156.520 ;
            RECT 116.155 156.200 118.075 156.520 ;
            RECT 119.995 156.200 121.915 156.520 ;
            RECT 123.835 156.200 125.755 156.520 ;
            RECT 127.675 156.200 129.595 156.520 ;
            RECT 131.515 156.200 133.435 156.520 ;
            RECT 135.355 156.200 352.720 156.520 ;
            RECT 357.440 156.200 360.320 156.520 ;
            RECT 0.000 156.520 72.470 156.880 ;
            RECT 74.390 156.520 78.435 156.880 ;
            RECT 80.355 156.520 82.275 156.880 ;
            RECT 84.195 156.520 86.115 156.880 ;
            RECT 88.035 156.520 92.590 156.880 ;
            RECT 94.510 156.520 96.430 156.880 ;
            RECT 98.350 156.520 100.270 156.880 ;
            RECT 102.190 156.520 106.555 156.880 ;
            RECT 108.475 156.520 110.395 156.880 ;
            RECT 112.315 156.520 114.235 156.880 ;
            RECT 116.155 156.520 118.075 156.880 ;
            RECT 119.995 156.520 121.915 156.880 ;
            RECT 123.835 156.520 125.755 156.880 ;
            RECT 127.675 156.520 129.595 156.880 ;
            RECT 131.515 156.520 133.435 156.880 ;
            RECT 135.355 156.520 360.320 156.880 ;
            RECT 0.000 156.880 0.160 157.200 ;
            RECT 71.520 156.880 72.470 157.200 ;
            RECT 74.390 156.880 78.435 157.200 ;
            RECT 80.355 156.880 82.275 157.200 ;
            RECT 84.195 156.880 86.115 157.200 ;
            RECT 88.035 156.880 92.590 157.200 ;
            RECT 94.510 156.880 96.430 157.200 ;
            RECT 98.350 156.880 100.270 157.200 ;
            RECT 102.190 156.880 106.555 157.200 ;
            RECT 108.475 156.880 110.395 157.200 ;
            RECT 112.315 156.880 114.235 157.200 ;
            RECT 116.155 156.880 118.075 157.200 ;
            RECT 119.995 156.880 121.915 157.200 ;
            RECT 123.835 156.880 125.755 157.200 ;
            RECT 127.675 156.880 129.595 157.200 ;
            RECT 131.515 156.880 133.435 157.200 ;
            RECT 135.355 156.880 352.720 157.200 ;
            RECT 360.160 156.880 360.320 157.200 ;
            RECT 0.000 157.200 72.470 157.560 ;
            RECT 74.390 157.200 78.435 157.560 ;
            RECT 80.355 157.200 82.275 157.560 ;
            RECT 84.195 157.200 86.115 157.560 ;
            RECT 88.035 157.200 92.590 157.560 ;
            RECT 94.510 157.200 96.430 157.560 ;
            RECT 98.350 157.200 100.270 157.560 ;
            RECT 102.190 157.200 106.555 157.560 ;
            RECT 108.475 157.200 110.395 157.560 ;
            RECT 112.315 157.200 114.235 157.560 ;
            RECT 116.155 157.200 118.075 157.560 ;
            RECT 119.995 157.200 121.915 157.560 ;
            RECT 123.835 157.200 125.755 157.560 ;
            RECT 127.675 157.200 129.595 157.560 ;
            RECT 131.515 157.200 133.435 157.560 ;
            RECT 135.355 157.200 360.320 157.560 ;
            RECT 0.000 157.560 2.880 157.880 ;
            RECT 13.720 157.560 16.800 157.880 ;
            RECT 71.520 157.560 72.470 157.880 ;
            RECT 74.390 157.560 78.435 157.880 ;
            RECT 80.355 157.560 82.275 157.880 ;
            RECT 84.195 157.560 86.115 157.880 ;
            RECT 88.035 157.560 92.590 157.880 ;
            RECT 94.510 157.560 96.430 157.880 ;
            RECT 98.350 157.560 100.270 157.880 ;
            RECT 102.190 157.560 106.555 157.880 ;
            RECT 108.475 157.560 110.395 157.880 ;
            RECT 112.315 157.560 114.235 157.880 ;
            RECT 116.155 157.560 118.075 157.880 ;
            RECT 119.995 157.560 121.915 157.880 ;
            RECT 123.835 157.560 125.755 157.880 ;
            RECT 127.675 157.560 129.595 157.880 ;
            RECT 131.515 157.560 133.435 157.880 ;
            RECT 135.355 157.560 352.720 157.880 ;
            RECT 357.440 157.560 360.320 157.880 ;
            RECT 0.000 157.880 72.470 158.240 ;
            RECT 74.390 157.880 78.435 158.240 ;
            RECT 80.355 157.880 82.275 158.240 ;
            RECT 84.195 157.880 86.115 158.240 ;
            RECT 88.035 157.880 92.590 158.240 ;
            RECT 94.510 157.880 96.430 158.240 ;
            RECT 98.350 157.880 100.270 158.240 ;
            RECT 102.190 157.880 106.555 158.240 ;
            RECT 108.475 157.880 110.395 158.240 ;
            RECT 112.315 157.880 114.235 158.240 ;
            RECT 116.155 157.880 118.075 158.240 ;
            RECT 119.995 157.880 121.915 158.240 ;
            RECT 123.835 157.880 125.755 158.240 ;
            RECT 127.675 157.880 129.595 158.240 ;
            RECT 131.515 157.880 133.435 158.240 ;
            RECT 135.355 157.880 360.320 158.240 ;
            RECT 0.000 158.240 0.160 158.560 ;
            RECT 13.720 158.240 16.800 158.560 ;
            RECT 30.040 158.240 33.800 158.560 ;
            RECT 71.520 158.240 72.470 158.560 ;
            RECT 74.390 158.240 78.435 158.560 ;
            RECT 80.355 158.240 82.275 158.560 ;
            RECT 84.195 158.240 86.115 158.560 ;
            RECT 88.035 158.240 92.590 158.560 ;
            RECT 94.510 158.240 96.430 158.560 ;
            RECT 98.350 158.240 100.270 158.560 ;
            RECT 102.190 158.240 106.555 158.560 ;
            RECT 108.475 158.240 110.395 158.560 ;
            RECT 112.315 158.240 114.235 158.560 ;
            RECT 116.155 158.240 118.075 158.560 ;
            RECT 119.995 158.240 121.915 158.560 ;
            RECT 123.835 158.240 125.755 158.560 ;
            RECT 127.675 158.240 129.595 158.560 ;
            RECT 131.515 158.240 133.435 158.560 ;
            RECT 135.355 158.240 352.720 158.560 ;
            RECT 360.160 158.240 360.320 158.560 ;
            RECT 0.000 158.560 72.470 158.920 ;
            RECT 74.390 158.560 78.435 158.920 ;
            RECT 80.355 158.560 82.275 158.920 ;
            RECT 84.195 158.560 86.115 158.920 ;
            RECT 88.035 158.560 92.590 158.920 ;
            RECT 94.510 158.560 96.430 158.920 ;
            RECT 98.350 158.560 100.270 158.920 ;
            RECT 102.190 158.560 106.555 158.920 ;
            RECT 108.475 158.560 110.395 158.920 ;
            RECT 112.315 158.560 114.235 158.920 ;
            RECT 116.155 158.560 118.075 158.920 ;
            RECT 119.995 158.560 121.915 158.920 ;
            RECT 123.835 158.560 125.755 158.920 ;
            RECT 127.675 158.560 129.595 158.920 ;
            RECT 131.515 158.560 133.435 158.920 ;
            RECT 135.355 158.560 360.320 158.920 ;
            RECT 0.000 158.920 2.880 159.240 ;
            RECT 13.040 158.920 16.800 159.240 ;
            RECT 34.800 158.920 40.600 159.240 ;
            RECT 71.520 158.920 72.470 159.240 ;
            RECT 74.390 158.920 78.435 159.240 ;
            RECT 80.355 158.920 82.275 159.240 ;
            RECT 84.195 158.920 86.115 159.240 ;
            RECT 88.035 158.920 92.590 159.240 ;
            RECT 94.510 158.920 96.430 159.240 ;
            RECT 98.350 158.920 100.270 159.240 ;
            RECT 102.190 158.920 106.555 159.240 ;
            RECT 108.475 158.920 110.395 159.240 ;
            RECT 112.315 158.920 114.235 159.240 ;
            RECT 116.155 158.920 118.075 159.240 ;
            RECT 119.995 158.920 121.915 159.240 ;
            RECT 123.835 158.920 125.755 159.240 ;
            RECT 127.675 158.920 129.595 159.240 ;
            RECT 131.515 158.920 133.435 159.240 ;
            RECT 135.355 158.920 352.720 159.240 ;
            RECT 357.440 158.920 360.320 159.240 ;
            RECT 0.000 159.240 72.470 159.600 ;
            RECT 74.390 159.240 78.435 159.600 ;
            RECT 80.355 159.240 82.275 159.600 ;
            RECT 84.195 159.240 86.115 159.600 ;
            RECT 88.035 159.240 92.590 159.600 ;
            RECT 94.510 159.240 96.430 159.600 ;
            RECT 98.350 159.240 100.270 159.600 ;
            RECT 102.190 159.240 106.555 159.600 ;
            RECT 108.475 159.240 110.395 159.600 ;
            RECT 112.315 159.240 114.235 159.600 ;
            RECT 116.155 159.240 118.075 159.600 ;
            RECT 119.995 159.240 121.915 159.600 ;
            RECT 123.835 159.240 125.755 159.600 ;
            RECT 127.675 159.240 129.595 159.600 ;
            RECT 131.515 159.240 133.435 159.600 ;
            RECT 135.355 159.240 360.320 159.600 ;
            RECT 0.000 159.600 0.160 159.920 ;
            RECT 13.040 159.600 16.800 159.920 ;
            RECT 30.040 159.600 39.920 159.920 ;
            RECT 71.520 159.600 72.470 159.920 ;
            RECT 74.390 159.600 78.435 159.920 ;
            RECT 80.355 159.600 82.275 159.920 ;
            RECT 84.195 159.600 86.115 159.920 ;
            RECT 88.035 159.600 92.590 159.920 ;
            RECT 94.510 159.600 96.430 159.920 ;
            RECT 98.350 159.600 100.270 159.920 ;
            RECT 102.190 159.600 106.555 159.920 ;
            RECT 108.475 159.600 110.395 159.920 ;
            RECT 112.315 159.600 114.235 159.920 ;
            RECT 116.155 159.600 118.075 159.920 ;
            RECT 119.995 159.600 121.915 159.920 ;
            RECT 123.835 159.600 125.755 159.920 ;
            RECT 127.675 159.600 129.595 159.920 ;
            RECT 131.515 159.600 133.435 159.920 ;
            RECT 135.355 159.600 352.720 159.920 ;
            RECT 360.160 159.600 360.320 159.920 ;
            RECT 0.000 159.920 72.470 160.280 ;
            RECT 74.390 159.920 78.435 160.280 ;
            RECT 80.355 159.920 82.275 160.280 ;
            RECT 84.195 159.920 86.115 160.280 ;
            RECT 88.035 159.920 92.590 160.280 ;
            RECT 94.510 159.920 96.430 160.280 ;
            RECT 98.350 159.920 100.270 160.280 ;
            RECT 102.190 159.920 106.555 160.280 ;
            RECT 108.475 159.920 110.395 160.280 ;
            RECT 112.315 159.920 114.235 160.280 ;
            RECT 116.155 159.920 118.075 160.280 ;
            RECT 119.995 159.920 121.915 160.280 ;
            RECT 123.835 159.920 125.755 160.280 ;
            RECT 127.675 159.920 129.595 160.280 ;
            RECT 131.515 159.920 133.435 160.280 ;
            RECT 135.355 159.920 360.320 160.280 ;
            RECT 0.000 160.280 2.880 160.600 ;
            RECT 12.360 160.280 16.800 160.600 ;
            RECT 36.160 160.280 39.920 160.600 ;
            RECT 71.520 160.280 72.470 160.600 ;
            RECT 74.390 160.280 78.435 160.600 ;
            RECT 80.355 160.280 82.275 160.600 ;
            RECT 84.195 160.280 86.115 160.600 ;
            RECT 88.035 160.280 92.590 160.600 ;
            RECT 94.510 160.280 96.430 160.600 ;
            RECT 98.350 160.280 100.270 160.600 ;
            RECT 102.190 160.280 106.555 160.600 ;
            RECT 108.475 160.280 110.395 160.600 ;
            RECT 112.315 160.280 114.235 160.600 ;
            RECT 116.155 160.280 118.075 160.600 ;
            RECT 119.995 160.280 121.915 160.600 ;
            RECT 123.835 160.280 125.755 160.600 ;
            RECT 127.675 160.280 129.595 160.600 ;
            RECT 131.515 160.280 133.435 160.600 ;
            RECT 135.355 160.280 352.720 160.600 ;
            RECT 357.440 160.280 360.320 160.600 ;
            RECT 0.000 160.600 72.470 160.960 ;
            RECT 74.390 160.600 78.435 160.960 ;
            RECT 80.355 160.600 82.275 160.960 ;
            RECT 84.195 160.600 86.115 160.960 ;
            RECT 88.035 160.600 92.590 160.960 ;
            RECT 94.510 160.600 96.430 160.960 ;
            RECT 98.350 160.600 100.270 160.960 ;
            RECT 102.190 160.600 106.555 160.960 ;
            RECT 108.475 160.600 110.395 160.960 ;
            RECT 112.315 160.600 114.235 160.960 ;
            RECT 116.155 160.600 118.075 160.960 ;
            RECT 119.995 160.600 121.915 160.960 ;
            RECT 123.835 160.600 125.755 160.960 ;
            RECT 127.675 160.600 129.595 160.960 ;
            RECT 131.515 160.600 133.435 160.960 ;
            RECT 135.355 160.600 360.320 160.960 ;
            RECT 0.000 160.960 0.160 161.280 ;
            RECT 12.360 160.960 16.800 161.280 ;
            RECT 30.040 160.960 39.240 161.280 ;
            RECT 51.120 160.960 52.160 161.280 ;
            RECT 71.520 160.960 72.470 161.280 ;
            RECT 74.390 160.960 78.435 161.280 ;
            RECT 80.355 160.960 82.275 161.280 ;
            RECT 84.195 160.960 86.115 161.280 ;
            RECT 88.035 160.960 92.590 161.280 ;
            RECT 94.510 160.960 96.430 161.280 ;
            RECT 98.350 160.960 100.270 161.280 ;
            RECT 102.190 160.960 106.555 161.280 ;
            RECT 108.475 160.960 110.395 161.280 ;
            RECT 112.315 160.960 114.235 161.280 ;
            RECT 116.155 160.960 118.075 161.280 ;
            RECT 119.995 160.960 121.915 161.280 ;
            RECT 123.835 160.960 125.755 161.280 ;
            RECT 127.675 160.960 129.595 161.280 ;
            RECT 131.515 160.960 133.435 161.280 ;
            RECT 135.355 160.960 352.720 161.280 ;
            RECT 360.160 160.960 360.320 161.280 ;
            RECT 0.000 161.280 72.470 161.640 ;
            RECT 74.390 161.280 78.435 161.640 ;
            RECT 80.355 161.280 82.275 161.640 ;
            RECT 84.195 161.280 86.115 161.640 ;
            RECT 88.035 161.280 92.590 161.640 ;
            RECT 94.510 161.280 96.430 161.640 ;
            RECT 98.350 161.280 100.270 161.640 ;
            RECT 102.190 161.280 106.555 161.640 ;
            RECT 108.475 161.280 110.395 161.640 ;
            RECT 112.315 161.280 114.235 161.640 ;
            RECT 116.155 161.280 118.075 161.640 ;
            RECT 119.995 161.280 121.915 161.640 ;
            RECT 123.835 161.280 125.755 161.640 ;
            RECT 127.675 161.280 129.595 161.640 ;
            RECT 131.515 161.280 133.435 161.640 ;
            RECT 135.355 161.280 360.320 161.640 ;
            RECT 0.000 161.640 2.880 161.960 ;
            RECT 51.120 161.640 52.840 161.960 ;
            RECT 71.520 161.640 72.470 161.960 ;
            RECT 74.390 161.640 78.435 161.960 ;
            RECT 80.355 161.640 82.275 161.960 ;
            RECT 84.195 161.640 86.115 161.960 ;
            RECT 88.035 161.640 92.590 161.960 ;
            RECT 94.510 161.640 96.430 161.960 ;
            RECT 98.350 161.640 100.270 161.960 ;
            RECT 102.190 161.640 106.555 161.960 ;
            RECT 108.475 161.640 110.395 161.960 ;
            RECT 112.315 161.640 114.235 161.960 ;
            RECT 116.155 161.640 118.075 161.960 ;
            RECT 119.995 161.640 121.915 161.960 ;
            RECT 123.835 161.640 125.755 161.960 ;
            RECT 127.675 161.640 129.595 161.960 ;
            RECT 131.515 161.640 133.435 161.960 ;
            RECT 135.355 161.640 352.720 161.960 ;
            RECT 357.440 161.640 360.320 161.960 ;
            RECT 0.000 161.960 72.470 162.320 ;
            RECT 74.390 161.960 78.435 162.320 ;
            RECT 80.355 161.960 82.275 162.320 ;
            RECT 84.195 161.960 86.115 162.320 ;
            RECT 88.035 161.960 92.590 162.320 ;
            RECT 94.510 161.960 96.430 162.320 ;
            RECT 98.350 161.960 100.270 162.320 ;
            RECT 102.190 161.960 106.555 162.320 ;
            RECT 108.475 161.960 110.395 162.320 ;
            RECT 112.315 161.960 114.235 162.320 ;
            RECT 116.155 161.960 118.075 162.320 ;
            RECT 119.995 161.960 121.915 162.320 ;
            RECT 123.835 161.960 125.755 162.320 ;
            RECT 127.675 161.960 129.595 162.320 ;
            RECT 131.515 161.960 133.435 162.320 ;
            RECT 135.355 161.960 360.320 162.320 ;
            RECT 0.000 162.320 0.160 162.640 ;
            RECT 51.120 162.320 52.840 162.640 ;
            RECT 71.520 162.320 72.470 162.640 ;
            RECT 74.390 162.320 78.435 162.640 ;
            RECT 80.355 162.320 82.275 162.640 ;
            RECT 84.195 162.320 86.115 162.640 ;
            RECT 88.035 162.320 92.590 162.640 ;
            RECT 94.510 162.320 96.430 162.640 ;
            RECT 98.350 162.320 100.270 162.640 ;
            RECT 102.190 162.320 106.555 162.640 ;
            RECT 108.475 162.320 110.395 162.640 ;
            RECT 112.315 162.320 114.235 162.640 ;
            RECT 116.155 162.320 118.075 162.640 ;
            RECT 119.995 162.320 121.915 162.640 ;
            RECT 123.835 162.320 125.755 162.640 ;
            RECT 127.675 162.320 129.595 162.640 ;
            RECT 131.515 162.320 133.435 162.640 ;
            RECT 135.355 162.320 352.720 162.640 ;
            RECT 360.160 162.320 360.320 162.640 ;
            RECT 0.000 162.640 72.470 163.000 ;
            RECT 74.390 162.640 78.435 163.000 ;
            RECT 80.355 162.640 82.275 163.000 ;
            RECT 84.195 162.640 86.115 163.000 ;
            RECT 88.035 162.640 92.590 163.000 ;
            RECT 94.510 162.640 96.430 163.000 ;
            RECT 98.350 162.640 100.270 163.000 ;
            RECT 102.190 162.640 106.555 163.000 ;
            RECT 108.475 162.640 110.395 163.000 ;
            RECT 112.315 162.640 114.235 163.000 ;
            RECT 116.155 162.640 118.075 163.000 ;
            RECT 119.995 162.640 121.915 163.000 ;
            RECT 123.835 162.640 125.755 163.000 ;
            RECT 127.675 162.640 129.595 163.000 ;
            RECT 131.515 162.640 133.435 163.000 ;
            RECT 135.355 162.640 360.320 163.000 ;
            RECT 0.000 163.000 2.880 163.320 ;
            RECT 11.680 163.000 16.800 163.320 ;
            RECT 51.120 163.000 53.520 163.320 ;
            RECT 71.520 163.000 72.470 163.320 ;
            RECT 74.390 163.000 78.435 163.320 ;
            RECT 80.355 163.000 82.275 163.320 ;
            RECT 84.195 163.000 86.115 163.320 ;
            RECT 88.035 163.000 92.590 163.320 ;
            RECT 94.510 163.000 96.430 163.320 ;
            RECT 98.350 163.000 100.270 163.320 ;
            RECT 102.190 163.000 106.555 163.320 ;
            RECT 108.475 163.000 110.395 163.320 ;
            RECT 112.315 163.000 114.235 163.320 ;
            RECT 116.155 163.000 118.075 163.320 ;
            RECT 119.995 163.000 121.915 163.320 ;
            RECT 123.835 163.000 125.755 163.320 ;
            RECT 127.675 163.000 129.595 163.320 ;
            RECT 131.515 163.000 133.435 163.320 ;
            RECT 135.355 163.000 352.720 163.320 ;
            RECT 357.440 163.000 360.320 163.320 ;
            RECT 0.000 163.320 72.470 163.680 ;
            RECT 74.390 163.320 78.435 163.680 ;
            RECT 80.355 163.320 82.275 163.680 ;
            RECT 84.195 163.320 86.115 163.680 ;
            RECT 88.035 163.320 92.590 163.680 ;
            RECT 94.510 163.320 96.430 163.680 ;
            RECT 98.350 163.320 100.270 163.680 ;
            RECT 102.190 163.320 106.555 163.680 ;
            RECT 108.475 163.320 110.395 163.680 ;
            RECT 112.315 163.320 114.235 163.680 ;
            RECT 116.155 163.320 118.075 163.680 ;
            RECT 119.995 163.320 121.915 163.680 ;
            RECT 123.835 163.320 125.755 163.680 ;
            RECT 127.675 163.320 129.595 163.680 ;
            RECT 131.515 163.320 133.435 163.680 ;
            RECT 135.355 163.320 360.320 163.680 ;
            RECT 0.000 163.680 0.160 164.000 ;
            RECT 11.680 163.680 16.800 164.000 ;
            RECT 30.040 163.680 35.840 164.000 ;
            RECT 51.120 163.680 53.520 164.000 ;
            RECT 71.520 163.680 72.470 164.000 ;
            RECT 74.390 163.680 78.435 164.000 ;
            RECT 80.355 163.680 82.275 164.000 ;
            RECT 84.195 163.680 86.115 164.000 ;
            RECT 88.035 163.680 92.590 164.000 ;
            RECT 94.510 163.680 96.430 164.000 ;
            RECT 98.350 163.680 100.270 164.000 ;
            RECT 102.190 163.680 106.555 164.000 ;
            RECT 108.475 163.680 110.395 164.000 ;
            RECT 112.315 163.680 114.235 164.000 ;
            RECT 116.155 163.680 118.075 164.000 ;
            RECT 119.995 163.680 121.915 164.000 ;
            RECT 123.835 163.680 125.755 164.000 ;
            RECT 127.675 163.680 129.595 164.000 ;
            RECT 131.515 163.680 133.435 164.000 ;
            RECT 135.355 163.680 352.720 164.000 ;
            RECT 360.160 163.680 360.320 164.000 ;
            RECT 0.000 164.000 72.470 164.360 ;
            RECT 74.390 164.000 78.435 164.360 ;
            RECT 80.355 164.000 82.275 164.360 ;
            RECT 84.195 164.000 86.115 164.360 ;
            RECT 88.035 164.000 92.590 164.360 ;
            RECT 94.510 164.000 96.430 164.360 ;
            RECT 98.350 164.000 100.270 164.360 ;
            RECT 102.190 164.000 106.555 164.360 ;
            RECT 108.475 164.000 110.395 164.360 ;
            RECT 112.315 164.000 114.235 164.360 ;
            RECT 116.155 164.000 118.075 164.360 ;
            RECT 119.995 164.000 121.915 164.360 ;
            RECT 123.835 164.000 125.755 164.360 ;
            RECT 127.675 164.000 129.595 164.360 ;
            RECT 131.515 164.000 133.435 164.360 ;
            RECT 135.355 164.000 360.320 164.360 ;
            RECT 0.000 164.360 2.880 164.680 ;
            RECT 51.120 164.360 54.200 164.680 ;
            RECT 71.520 164.360 72.470 164.680 ;
            RECT 74.390 164.360 78.435 164.680 ;
            RECT 80.355 164.360 82.275 164.680 ;
            RECT 84.195 164.360 86.115 164.680 ;
            RECT 88.035 164.360 92.590 164.680 ;
            RECT 94.510 164.360 96.430 164.680 ;
            RECT 98.350 164.360 100.270 164.680 ;
            RECT 102.190 164.360 106.555 164.680 ;
            RECT 108.475 164.360 110.395 164.680 ;
            RECT 112.315 164.360 114.235 164.680 ;
            RECT 116.155 164.360 118.075 164.680 ;
            RECT 119.995 164.360 121.915 164.680 ;
            RECT 123.835 164.360 125.755 164.680 ;
            RECT 127.675 164.360 129.595 164.680 ;
            RECT 131.515 164.360 133.435 164.680 ;
            RECT 135.355 164.360 352.720 164.680 ;
            RECT 357.440 164.360 360.320 164.680 ;
            RECT 0.000 164.680 72.470 165.040 ;
            RECT 74.390 164.680 78.435 165.040 ;
            RECT 80.355 164.680 82.275 165.040 ;
            RECT 84.195 164.680 86.115 165.040 ;
            RECT 88.035 164.680 92.590 165.040 ;
            RECT 94.510 164.680 96.430 165.040 ;
            RECT 98.350 164.680 100.270 165.040 ;
            RECT 102.190 164.680 106.555 165.040 ;
            RECT 108.475 164.680 110.395 165.040 ;
            RECT 112.315 164.680 114.235 165.040 ;
            RECT 116.155 164.680 118.075 165.040 ;
            RECT 119.995 164.680 121.915 165.040 ;
            RECT 123.835 164.680 125.755 165.040 ;
            RECT 127.675 164.680 129.595 165.040 ;
            RECT 131.515 164.680 133.435 165.040 ;
            RECT 135.355 164.680 360.320 165.040 ;
            RECT 0.000 165.040 0.160 165.360 ;
            RECT 11.000 165.040 16.800 165.360 ;
            RECT 51.120 165.040 54.200 165.360 ;
            RECT 71.520 165.040 72.470 165.360 ;
            RECT 74.390 165.040 78.435 165.360 ;
            RECT 80.355 165.040 82.275 165.360 ;
            RECT 84.195 165.040 86.115 165.360 ;
            RECT 88.035 165.040 92.590 165.360 ;
            RECT 94.510 165.040 96.430 165.360 ;
            RECT 98.350 165.040 100.270 165.360 ;
            RECT 102.190 165.040 106.555 165.360 ;
            RECT 108.475 165.040 110.395 165.360 ;
            RECT 112.315 165.040 114.235 165.360 ;
            RECT 116.155 165.040 118.075 165.360 ;
            RECT 119.995 165.040 121.915 165.360 ;
            RECT 123.835 165.040 125.755 165.360 ;
            RECT 127.675 165.040 129.595 165.360 ;
            RECT 131.515 165.040 133.435 165.360 ;
            RECT 135.355 165.040 352.720 165.360 ;
            RECT 360.160 165.040 360.320 165.360 ;
            RECT 0.000 165.360 72.470 165.720 ;
            RECT 74.390 165.360 78.435 165.720 ;
            RECT 80.355 165.360 82.275 165.720 ;
            RECT 84.195 165.360 86.115 165.720 ;
            RECT 88.035 165.360 92.590 165.720 ;
            RECT 94.510 165.360 96.430 165.720 ;
            RECT 98.350 165.360 100.270 165.720 ;
            RECT 102.190 165.360 106.555 165.720 ;
            RECT 108.475 165.360 110.395 165.720 ;
            RECT 112.315 165.360 114.235 165.720 ;
            RECT 116.155 165.360 118.075 165.720 ;
            RECT 119.995 165.360 121.915 165.720 ;
            RECT 123.835 165.360 125.755 165.720 ;
            RECT 127.675 165.360 129.595 165.720 ;
            RECT 131.515 165.360 133.435 165.720 ;
            RECT 135.355 165.360 360.320 165.720 ;
            RECT 0.000 165.720 2.880 166.040 ;
            RECT 11.000 165.720 16.800 166.040 ;
            RECT 30.040 165.720 36.520 166.040 ;
            RECT 51.120 165.720 52.160 166.040 ;
            RECT 71.520 165.720 72.470 166.040 ;
            RECT 74.390 165.720 78.435 166.040 ;
            RECT 80.355 165.720 82.275 166.040 ;
            RECT 84.195 165.720 86.115 166.040 ;
            RECT 88.035 165.720 92.590 166.040 ;
            RECT 94.510 165.720 96.430 166.040 ;
            RECT 98.350 165.720 100.270 166.040 ;
            RECT 102.190 165.720 106.555 166.040 ;
            RECT 108.475 165.720 110.395 166.040 ;
            RECT 112.315 165.720 114.235 166.040 ;
            RECT 116.155 165.720 118.075 166.040 ;
            RECT 119.995 165.720 121.915 166.040 ;
            RECT 123.835 165.720 125.755 166.040 ;
            RECT 127.675 165.720 129.595 166.040 ;
            RECT 131.515 165.720 133.435 166.040 ;
            RECT 135.355 165.720 352.720 166.040 ;
            RECT 357.440 165.720 360.320 166.040 ;
            RECT 0.000 166.040 72.470 166.400 ;
            RECT 74.390 166.040 78.435 166.400 ;
            RECT 80.355 166.040 82.275 166.400 ;
            RECT 84.195 166.040 86.115 166.400 ;
            RECT 88.035 166.040 92.590 166.400 ;
            RECT 94.510 166.040 96.430 166.400 ;
            RECT 98.350 166.040 100.270 166.400 ;
            RECT 102.190 166.040 106.555 166.400 ;
            RECT 108.475 166.040 110.395 166.400 ;
            RECT 112.315 166.040 114.235 166.400 ;
            RECT 116.155 166.040 118.075 166.400 ;
            RECT 119.995 166.040 121.915 166.400 ;
            RECT 123.835 166.040 125.755 166.400 ;
            RECT 127.675 166.040 129.595 166.400 ;
            RECT 131.515 166.040 133.435 166.400 ;
            RECT 135.355 166.040 360.320 166.400 ;
            RECT 0.000 166.400 0.160 166.720 ;
            RECT 10.320 166.400 16.800 166.720 ;
            RECT 51.120 166.400 54.200 166.720 ;
            RECT 71.520 166.400 72.470 166.720 ;
            RECT 74.390 166.400 78.435 166.720 ;
            RECT 80.355 166.400 82.275 166.720 ;
            RECT 84.195 166.400 86.115 166.720 ;
            RECT 88.035 166.400 92.590 166.720 ;
            RECT 94.510 166.400 96.430 166.720 ;
            RECT 98.350 166.400 100.270 166.720 ;
            RECT 102.190 166.400 106.555 166.720 ;
            RECT 108.475 166.400 110.395 166.720 ;
            RECT 112.315 166.400 114.235 166.720 ;
            RECT 116.155 166.400 118.075 166.720 ;
            RECT 119.995 166.400 121.915 166.720 ;
            RECT 123.835 166.400 125.755 166.720 ;
            RECT 127.675 166.400 129.595 166.720 ;
            RECT 131.515 166.400 133.435 166.720 ;
            RECT 135.355 166.400 352.720 166.720 ;
            RECT 360.160 166.400 360.320 166.720 ;
            RECT 0.000 166.720 72.470 167.080 ;
            RECT 74.390 166.720 78.435 167.080 ;
            RECT 80.355 166.720 82.275 167.080 ;
            RECT 84.195 166.720 86.115 167.080 ;
            RECT 88.035 166.720 92.590 167.080 ;
            RECT 94.510 166.720 96.430 167.080 ;
            RECT 98.350 166.720 100.270 167.080 ;
            RECT 102.190 166.720 106.555 167.080 ;
            RECT 108.475 166.720 110.395 167.080 ;
            RECT 112.315 166.720 114.235 167.080 ;
            RECT 116.155 166.720 118.075 167.080 ;
            RECT 119.995 166.720 121.915 167.080 ;
            RECT 123.835 166.720 125.755 167.080 ;
            RECT 127.675 166.720 129.595 167.080 ;
            RECT 131.515 166.720 133.435 167.080 ;
            RECT 135.355 166.720 360.320 167.080 ;
            RECT 0.000 167.080 2.880 167.400 ;
            RECT 10.320 167.080 16.800 167.400 ;
            RECT 30.040 167.080 37.200 167.400 ;
            RECT 51.120 167.080 54.200 167.400 ;
            RECT 71.520 167.080 72.470 167.400 ;
            RECT 74.390 167.080 78.435 167.400 ;
            RECT 80.355 167.080 82.275 167.400 ;
            RECT 84.195 167.080 86.115 167.400 ;
            RECT 88.035 167.080 92.590 167.400 ;
            RECT 94.510 167.080 96.430 167.400 ;
            RECT 98.350 167.080 100.270 167.400 ;
            RECT 102.190 167.080 106.555 167.400 ;
            RECT 108.475 167.080 110.395 167.400 ;
            RECT 112.315 167.080 114.235 167.400 ;
            RECT 116.155 167.080 118.075 167.400 ;
            RECT 119.995 167.080 121.915 167.400 ;
            RECT 123.835 167.080 125.755 167.400 ;
            RECT 127.675 167.080 129.595 167.400 ;
            RECT 131.515 167.080 133.435 167.400 ;
            RECT 135.355 167.080 352.720 167.400 ;
            RECT 357.440 167.080 360.320 167.400 ;
            RECT 0.000 167.400 72.470 167.760 ;
            RECT 74.390 167.400 78.435 167.760 ;
            RECT 80.355 167.400 82.275 167.760 ;
            RECT 84.195 167.400 86.115 167.760 ;
            RECT 88.035 167.400 92.590 167.760 ;
            RECT 94.510 167.400 96.430 167.760 ;
            RECT 98.350 167.400 100.270 167.760 ;
            RECT 102.190 167.400 106.555 167.760 ;
            RECT 108.475 167.400 110.395 167.760 ;
            RECT 112.315 167.400 114.235 167.760 ;
            RECT 116.155 167.400 118.075 167.760 ;
            RECT 119.995 167.400 121.915 167.760 ;
            RECT 123.835 167.400 125.755 167.760 ;
            RECT 127.675 167.400 129.595 167.760 ;
            RECT 131.515 167.400 133.435 167.760 ;
            RECT 135.355 167.400 360.320 167.760 ;
            RECT 0.000 167.760 0.160 168.080 ;
            RECT 9.640 167.760 16.800 168.080 ;
            RECT 71.520 167.760 72.470 168.080 ;
            RECT 74.390 167.760 78.435 168.080 ;
            RECT 80.355 167.760 82.275 168.080 ;
            RECT 84.195 167.760 86.115 168.080 ;
            RECT 88.035 167.760 92.590 168.080 ;
            RECT 94.510 167.760 96.430 168.080 ;
            RECT 98.350 167.760 100.270 168.080 ;
            RECT 102.190 167.760 106.555 168.080 ;
            RECT 108.475 167.760 110.395 168.080 ;
            RECT 112.315 167.760 114.235 168.080 ;
            RECT 116.155 167.760 118.075 168.080 ;
            RECT 119.995 167.760 121.915 168.080 ;
            RECT 123.835 167.760 125.755 168.080 ;
            RECT 127.675 167.760 129.595 168.080 ;
            RECT 131.515 167.760 133.435 168.080 ;
            RECT 135.355 167.760 352.720 168.080 ;
            RECT 360.160 167.760 360.320 168.080 ;
            RECT 0.000 168.080 72.470 168.440 ;
            RECT 74.390 168.080 78.435 168.440 ;
            RECT 80.355 168.080 82.275 168.440 ;
            RECT 84.195 168.080 86.115 168.440 ;
            RECT 88.035 168.080 92.590 168.440 ;
            RECT 94.510 168.080 96.430 168.440 ;
            RECT 98.350 168.080 100.270 168.440 ;
            RECT 102.190 168.080 106.555 168.440 ;
            RECT 108.475 168.080 110.395 168.440 ;
            RECT 112.315 168.080 114.235 168.440 ;
            RECT 116.155 168.080 118.075 168.440 ;
            RECT 119.995 168.080 121.915 168.440 ;
            RECT 123.835 168.080 125.755 168.440 ;
            RECT 127.675 168.080 129.595 168.440 ;
            RECT 131.515 168.080 133.435 168.440 ;
            RECT 135.355 168.080 360.320 168.440 ;
            RECT 0.000 168.440 2.880 168.760 ;
            RECT 9.640 168.440 16.800 168.760 ;
            RECT 30.040 168.440 37.880 168.760 ;
            RECT 71.520 168.440 72.470 168.760 ;
            RECT 74.390 168.440 78.435 168.760 ;
            RECT 80.355 168.440 82.275 168.760 ;
            RECT 84.195 168.440 86.115 168.760 ;
            RECT 88.035 168.440 92.590 168.760 ;
            RECT 94.510 168.440 96.430 168.760 ;
            RECT 98.350 168.440 100.270 168.760 ;
            RECT 102.190 168.440 106.555 168.760 ;
            RECT 108.475 168.440 110.395 168.760 ;
            RECT 112.315 168.440 114.235 168.760 ;
            RECT 116.155 168.440 118.075 168.760 ;
            RECT 119.995 168.440 121.915 168.760 ;
            RECT 123.835 168.440 125.755 168.760 ;
            RECT 127.675 168.440 129.595 168.760 ;
            RECT 131.515 168.440 133.435 168.760 ;
            RECT 135.355 168.440 352.720 168.760 ;
            RECT 357.440 168.440 360.320 168.760 ;
            RECT 0.000 168.760 72.470 169.120 ;
            RECT 74.390 168.760 78.435 169.120 ;
            RECT 80.355 168.760 82.275 169.120 ;
            RECT 84.195 168.760 86.115 169.120 ;
            RECT 88.035 168.760 92.590 169.120 ;
            RECT 94.510 168.760 96.430 169.120 ;
            RECT 98.350 168.760 100.270 169.120 ;
            RECT 102.190 168.760 106.555 169.120 ;
            RECT 108.475 168.760 110.395 169.120 ;
            RECT 112.315 168.760 114.235 169.120 ;
            RECT 116.155 168.760 118.075 169.120 ;
            RECT 119.995 168.760 121.915 169.120 ;
            RECT 123.835 168.760 125.755 169.120 ;
            RECT 127.675 168.760 129.595 169.120 ;
            RECT 131.515 168.760 133.435 169.120 ;
            RECT 135.355 168.760 360.320 169.120 ;
            RECT 0.000 169.120 0.160 169.440 ;
            RECT 71.520 169.120 72.470 169.440 ;
            RECT 74.390 169.120 78.435 169.440 ;
            RECT 80.355 169.120 82.275 169.440 ;
            RECT 84.195 169.120 86.115 169.440 ;
            RECT 88.035 169.120 92.590 169.440 ;
            RECT 94.510 169.120 96.430 169.440 ;
            RECT 98.350 169.120 100.270 169.440 ;
            RECT 102.190 169.120 106.555 169.440 ;
            RECT 108.475 169.120 110.395 169.440 ;
            RECT 112.315 169.120 114.235 169.440 ;
            RECT 116.155 169.120 118.075 169.440 ;
            RECT 119.995 169.120 121.915 169.440 ;
            RECT 123.835 169.120 125.755 169.440 ;
            RECT 127.675 169.120 129.595 169.440 ;
            RECT 131.515 169.120 133.435 169.440 ;
            RECT 135.355 169.120 352.720 169.440 ;
            RECT 360.160 169.120 360.320 169.440 ;
            RECT 0.000 169.440 72.470 169.800 ;
            RECT 74.390 169.440 78.435 169.800 ;
            RECT 80.355 169.440 82.275 169.800 ;
            RECT 84.195 169.440 86.115 169.800 ;
            RECT 88.035 169.440 92.590 169.800 ;
            RECT 94.510 169.440 96.430 169.800 ;
            RECT 98.350 169.440 100.270 169.800 ;
            RECT 102.190 169.440 106.555 169.800 ;
            RECT 108.475 169.440 110.395 169.800 ;
            RECT 112.315 169.440 114.235 169.800 ;
            RECT 116.155 169.440 118.075 169.800 ;
            RECT 119.995 169.440 121.915 169.800 ;
            RECT 123.835 169.440 125.755 169.800 ;
            RECT 127.675 169.440 129.595 169.800 ;
            RECT 131.515 169.440 133.435 169.800 ;
            RECT 135.355 169.440 360.320 169.800 ;
            RECT 0.000 169.800 2.880 170.120 ;
            RECT 71.520 169.800 72.470 170.120 ;
            RECT 74.390 169.800 78.435 170.120 ;
            RECT 80.355 169.800 82.275 170.120 ;
            RECT 84.195 169.800 86.115 170.120 ;
            RECT 88.035 169.800 92.590 170.120 ;
            RECT 94.510 169.800 96.430 170.120 ;
            RECT 98.350 169.800 100.270 170.120 ;
            RECT 102.190 169.800 106.555 170.120 ;
            RECT 108.475 169.800 110.395 170.120 ;
            RECT 112.315 169.800 114.235 170.120 ;
            RECT 116.155 169.800 118.075 170.120 ;
            RECT 119.995 169.800 121.915 170.120 ;
            RECT 123.835 169.800 125.755 170.120 ;
            RECT 127.675 169.800 129.595 170.120 ;
            RECT 131.515 169.800 133.435 170.120 ;
            RECT 135.355 169.800 352.720 170.120 ;
            RECT 357.440 169.800 360.320 170.120 ;
            RECT 0.000 170.120 72.470 170.480 ;
            RECT 74.390 170.120 78.435 170.480 ;
            RECT 80.355 170.120 82.275 170.480 ;
            RECT 84.195 170.120 86.115 170.480 ;
            RECT 88.035 170.120 92.590 170.480 ;
            RECT 94.510 170.120 96.430 170.480 ;
            RECT 98.350 170.120 100.270 170.480 ;
            RECT 102.190 170.120 106.555 170.480 ;
            RECT 108.475 170.120 110.395 170.480 ;
            RECT 112.315 170.120 114.235 170.480 ;
            RECT 116.155 170.120 118.075 170.480 ;
            RECT 119.995 170.120 121.915 170.480 ;
            RECT 123.835 170.120 125.755 170.480 ;
            RECT 127.675 170.120 129.595 170.480 ;
            RECT 131.515 170.120 133.435 170.480 ;
            RECT 135.355 170.120 360.320 170.480 ;
            RECT 0.000 170.480 0.160 170.800 ;
            RECT 71.520 170.480 72.470 170.800 ;
            RECT 74.390 170.480 78.435 170.800 ;
            RECT 80.355 170.480 82.275 170.800 ;
            RECT 84.195 170.480 86.115 170.800 ;
            RECT 88.035 170.480 92.590 170.800 ;
            RECT 94.510 170.480 96.430 170.800 ;
            RECT 98.350 170.480 100.270 170.800 ;
            RECT 102.190 170.480 106.555 170.800 ;
            RECT 108.475 170.480 110.395 170.800 ;
            RECT 112.315 170.480 114.235 170.800 ;
            RECT 116.155 170.480 118.075 170.800 ;
            RECT 119.995 170.480 121.915 170.800 ;
            RECT 123.835 170.480 125.755 170.800 ;
            RECT 127.675 170.480 129.595 170.800 ;
            RECT 131.515 170.480 133.435 170.800 ;
            RECT 135.355 170.480 352.720 170.800 ;
            RECT 360.160 170.480 360.320 170.800 ;
            RECT 0.000 170.800 72.470 171.160 ;
            RECT 74.390 170.800 78.435 171.160 ;
            RECT 80.355 170.800 82.275 171.160 ;
            RECT 84.195 170.800 86.115 171.160 ;
            RECT 88.035 170.800 92.590 171.160 ;
            RECT 94.510 170.800 96.430 171.160 ;
            RECT 98.350 170.800 100.270 171.160 ;
            RECT 102.190 170.800 106.555 171.160 ;
            RECT 108.475 170.800 110.395 171.160 ;
            RECT 112.315 170.800 114.235 171.160 ;
            RECT 116.155 170.800 118.075 171.160 ;
            RECT 119.995 170.800 121.915 171.160 ;
            RECT 123.835 170.800 125.755 171.160 ;
            RECT 127.675 170.800 129.595 171.160 ;
            RECT 131.515 170.800 133.435 171.160 ;
            RECT 135.355 170.800 360.320 171.160 ;
            RECT 0.000 171.160 2.880 171.480 ;
            RECT 71.520 171.160 72.470 171.480 ;
            RECT 74.390 171.160 78.435 171.480 ;
            RECT 80.355 171.160 82.275 171.480 ;
            RECT 84.195 171.160 86.115 171.480 ;
            RECT 88.035 171.160 92.590 171.480 ;
            RECT 94.510 171.160 96.430 171.480 ;
            RECT 98.350 171.160 100.270 171.480 ;
            RECT 102.190 171.160 106.555 171.480 ;
            RECT 108.475 171.160 110.395 171.480 ;
            RECT 112.315 171.160 114.235 171.480 ;
            RECT 116.155 171.160 118.075 171.480 ;
            RECT 119.995 171.160 121.915 171.480 ;
            RECT 123.835 171.160 125.755 171.480 ;
            RECT 127.675 171.160 129.595 171.480 ;
            RECT 131.515 171.160 133.435 171.480 ;
            RECT 135.355 171.160 352.720 171.480 ;
            RECT 357.440 171.160 360.320 171.480 ;
            RECT 0.000 171.480 72.470 171.840 ;
            RECT 74.390 171.480 78.435 171.840 ;
            RECT 80.355 171.480 82.275 171.840 ;
            RECT 84.195 171.480 86.115 171.840 ;
            RECT 88.035 171.480 92.590 171.840 ;
            RECT 94.510 171.480 96.430 171.840 ;
            RECT 98.350 171.480 100.270 171.840 ;
            RECT 102.190 171.480 106.555 171.840 ;
            RECT 108.475 171.480 110.395 171.840 ;
            RECT 112.315 171.480 114.235 171.840 ;
            RECT 116.155 171.480 118.075 171.840 ;
            RECT 119.995 171.480 121.915 171.840 ;
            RECT 123.835 171.480 125.755 171.840 ;
            RECT 127.675 171.480 129.595 171.840 ;
            RECT 131.515 171.480 133.435 171.840 ;
            RECT 135.355 171.480 360.320 171.840 ;
            RECT 0.000 171.840 0.160 172.160 ;
            RECT 71.520 171.840 72.470 172.160 ;
            RECT 74.390 171.840 78.435 172.160 ;
            RECT 80.355 171.840 82.275 172.160 ;
            RECT 84.195 171.840 86.115 172.160 ;
            RECT 88.035 171.840 92.590 172.160 ;
            RECT 94.510 171.840 96.430 172.160 ;
            RECT 98.350 171.840 100.270 172.160 ;
            RECT 102.190 171.840 106.555 172.160 ;
            RECT 108.475 171.840 110.395 172.160 ;
            RECT 112.315 171.840 114.235 172.160 ;
            RECT 116.155 171.840 118.075 172.160 ;
            RECT 119.995 171.840 121.915 172.160 ;
            RECT 123.835 171.840 125.755 172.160 ;
            RECT 127.675 171.840 129.595 172.160 ;
            RECT 131.515 171.840 133.435 172.160 ;
            RECT 135.355 171.840 352.720 172.160 ;
            RECT 360.160 171.840 360.320 172.160 ;
            RECT 0.000 172.160 72.470 172.520 ;
            RECT 74.390 172.160 78.435 172.520 ;
            RECT 80.355 172.160 82.275 172.520 ;
            RECT 84.195 172.160 86.115 172.520 ;
            RECT 88.035 172.160 92.590 172.520 ;
            RECT 94.510 172.160 96.430 172.520 ;
            RECT 98.350 172.160 100.270 172.520 ;
            RECT 102.190 172.160 106.555 172.520 ;
            RECT 108.475 172.160 110.395 172.520 ;
            RECT 112.315 172.160 114.235 172.520 ;
            RECT 116.155 172.160 118.075 172.520 ;
            RECT 119.995 172.160 121.915 172.520 ;
            RECT 123.835 172.160 125.755 172.520 ;
            RECT 127.675 172.160 129.595 172.520 ;
            RECT 131.515 172.160 133.435 172.520 ;
            RECT 135.355 172.160 360.320 172.520 ;
            RECT 0.000 172.520 2.880 172.840 ;
            RECT 71.520 172.520 72.470 172.840 ;
            RECT 74.390 172.520 78.435 172.840 ;
            RECT 80.355 172.520 82.275 172.840 ;
            RECT 84.195 172.520 86.115 172.840 ;
            RECT 88.035 172.520 92.590 172.840 ;
            RECT 94.510 172.520 96.430 172.840 ;
            RECT 98.350 172.520 100.270 172.840 ;
            RECT 102.190 172.520 106.555 172.840 ;
            RECT 108.475 172.520 110.395 172.840 ;
            RECT 112.315 172.520 114.235 172.840 ;
            RECT 116.155 172.520 118.075 172.840 ;
            RECT 119.995 172.520 121.915 172.840 ;
            RECT 123.835 172.520 125.755 172.840 ;
            RECT 127.675 172.520 129.595 172.840 ;
            RECT 131.515 172.520 133.435 172.840 ;
            RECT 135.355 172.520 352.720 172.840 ;
            RECT 357.440 172.520 360.320 172.840 ;
            RECT 0.000 172.840 72.470 173.200 ;
            RECT 74.390 172.840 78.435 173.200 ;
            RECT 80.355 172.840 82.275 173.200 ;
            RECT 84.195 172.840 86.115 173.200 ;
            RECT 88.035 172.840 92.590 173.200 ;
            RECT 94.510 172.840 96.430 173.200 ;
            RECT 98.350 172.840 100.270 173.200 ;
            RECT 102.190 172.840 106.555 173.200 ;
            RECT 108.475 172.840 110.395 173.200 ;
            RECT 112.315 172.840 114.235 173.200 ;
            RECT 116.155 172.840 118.075 173.200 ;
            RECT 119.995 172.840 121.915 173.200 ;
            RECT 123.835 172.840 125.755 173.200 ;
            RECT 127.675 172.840 129.595 173.200 ;
            RECT 131.515 172.840 133.435 173.200 ;
            RECT 135.355 172.840 360.320 173.200 ;
            RECT 0.000 173.200 0.160 173.520 ;
            RECT 71.520 173.200 72.470 173.520 ;
            RECT 74.390 173.200 78.435 173.520 ;
            RECT 80.355 173.200 82.275 173.520 ;
            RECT 84.195 173.200 86.115 173.520 ;
            RECT 88.035 173.200 92.590 173.520 ;
            RECT 94.510 173.200 96.430 173.520 ;
            RECT 98.350 173.200 100.270 173.520 ;
            RECT 102.190 173.200 106.555 173.520 ;
            RECT 108.475 173.200 110.395 173.520 ;
            RECT 112.315 173.200 114.235 173.520 ;
            RECT 116.155 173.200 118.075 173.520 ;
            RECT 119.995 173.200 121.915 173.520 ;
            RECT 123.835 173.200 125.755 173.520 ;
            RECT 127.675 173.200 129.595 173.520 ;
            RECT 131.515 173.200 133.435 173.520 ;
            RECT 135.355 173.200 352.720 173.520 ;
            RECT 360.160 173.200 360.320 173.520 ;
            RECT 0.000 173.520 72.470 173.880 ;
            RECT 74.390 173.520 78.435 173.880 ;
            RECT 80.355 173.520 82.275 173.880 ;
            RECT 84.195 173.520 86.115 173.880 ;
            RECT 88.035 173.520 92.590 173.880 ;
            RECT 94.510 173.520 96.430 173.880 ;
            RECT 98.350 173.520 100.270 173.880 ;
            RECT 102.190 173.520 106.555 173.880 ;
            RECT 108.475 173.520 110.395 173.880 ;
            RECT 112.315 173.520 114.235 173.880 ;
            RECT 116.155 173.520 118.075 173.880 ;
            RECT 119.995 173.520 121.915 173.880 ;
            RECT 123.835 173.520 125.755 173.880 ;
            RECT 127.675 173.520 129.595 173.880 ;
            RECT 131.515 173.520 133.435 173.880 ;
            RECT 135.355 173.520 360.320 173.880 ;
            RECT 0.000 173.880 2.880 174.200 ;
            RECT 71.520 173.880 72.470 174.200 ;
            RECT 74.390 173.880 78.435 174.200 ;
            RECT 80.355 173.880 82.275 174.200 ;
            RECT 84.195 173.880 86.115 174.200 ;
            RECT 88.035 173.880 92.590 174.200 ;
            RECT 94.510 173.880 96.430 174.200 ;
            RECT 98.350 173.880 100.270 174.200 ;
            RECT 102.190 173.880 106.555 174.200 ;
            RECT 108.475 173.880 110.395 174.200 ;
            RECT 112.315 173.880 114.235 174.200 ;
            RECT 116.155 173.880 118.075 174.200 ;
            RECT 119.995 173.880 121.915 174.200 ;
            RECT 123.835 173.880 125.755 174.200 ;
            RECT 127.675 173.880 129.595 174.200 ;
            RECT 131.515 173.880 133.435 174.200 ;
            RECT 135.355 173.880 352.720 174.200 ;
            RECT 357.440 173.880 360.320 174.200 ;
            RECT 0.000 174.200 72.470 174.560 ;
            RECT 74.390 174.200 78.435 174.560 ;
            RECT 80.355 174.200 82.275 174.560 ;
            RECT 84.195 174.200 86.115 174.560 ;
            RECT 88.035 174.200 92.590 174.560 ;
            RECT 94.510 174.200 96.430 174.560 ;
            RECT 98.350 174.200 100.270 174.560 ;
            RECT 102.190 174.200 106.555 174.560 ;
            RECT 108.475 174.200 110.395 174.560 ;
            RECT 112.315 174.200 114.235 174.560 ;
            RECT 116.155 174.200 118.075 174.560 ;
            RECT 119.995 174.200 121.915 174.560 ;
            RECT 123.835 174.200 125.755 174.560 ;
            RECT 127.675 174.200 129.595 174.560 ;
            RECT 131.515 174.200 133.435 174.560 ;
            RECT 135.355 174.200 360.320 174.560 ;
            RECT 0.000 174.560 0.160 174.880 ;
            RECT 71.520 174.560 72.470 174.880 ;
            RECT 74.390 174.560 78.435 174.880 ;
            RECT 80.355 174.560 82.275 174.880 ;
            RECT 84.195 174.560 86.115 174.880 ;
            RECT 88.035 174.560 92.590 174.880 ;
            RECT 94.510 174.560 96.430 174.880 ;
            RECT 98.350 174.560 100.270 174.880 ;
            RECT 102.190 174.560 106.555 174.880 ;
            RECT 108.475 174.560 110.395 174.880 ;
            RECT 112.315 174.560 114.235 174.880 ;
            RECT 116.155 174.560 118.075 174.880 ;
            RECT 119.995 174.560 121.915 174.880 ;
            RECT 123.835 174.560 125.755 174.880 ;
            RECT 127.675 174.560 129.595 174.880 ;
            RECT 131.515 174.560 133.435 174.880 ;
            RECT 135.355 174.560 352.720 174.880 ;
            RECT 360.160 174.560 360.320 174.880 ;
            RECT 0.000 174.880 72.470 175.240 ;
            RECT 74.390 174.880 78.435 175.240 ;
            RECT 80.355 174.880 82.275 175.240 ;
            RECT 84.195 174.880 86.115 175.240 ;
            RECT 88.035 174.880 92.590 175.240 ;
            RECT 94.510 174.880 96.430 175.240 ;
            RECT 98.350 174.880 100.270 175.240 ;
            RECT 102.190 174.880 106.555 175.240 ;
            RECT 108.475 174.880 110.395 175.240 ;
            RECT 112.315 174.880 114.235 175.240 ;
            RECT 116.155 174.880 118.075 175.240 ;
            RECT 119.995 174.880 121.915 175.240 ;
            RECT 123.835 174.880 125.755 175.240 ;
            RECT 127.675 174.880 129.595 175.240 ;
            RECT 131.515 174.880 133.435 175.240 ;
            RECT 135.355 174.880 360.320 175.240 ;
            RECT 0.000 175.240 2.880 175.560 ;
            RECT 71.520 175.240 72.470 175.560 ;
            RECT 74.390 175.240 78.435 175.560 ;
            RECT 80.355 175.240 82.275 175.560 ;
            RECT 84.195 175.240 86.115 175.560 ;
            RECT 88.035 175.240 92.590 175.560 ;
            RECT 94.510 175.240 96.430 175.560 ;
            RECT 98.350 175.240 100.270 175.560 ;
            RECT 102.190 175.240 106.555 175.560 ;
            RECT 108.475 175.240 110.395 175.560 ;
            RECT 112.315 175.240 114.235 175.560 ;
            RECT 116.155 175.240 118.075 175.560 ;
            RECT 119.995 175.240 121.915 175.560 ;
            RECT 123.835 175.240 125.755 175.560 ;
            RECT 127.675 175.240 129.595 175.560 ;
            RECT 131.515 175.240 133.435 175.560 ;
            RECT 135.355 175.240 352.720 175.560 ;
            RECT 357.440 175.240 360.320 175.560 ;
            RECT 0.000 175.560 72.470 175.920 ;
            RECT 74.390 175.560 78.435 175.920 ;
            RECT 80.355 175.560 82.275 175.920 ;
            RECT 84.195 175.560 86.115 175.920 ;
            RECT 88.035 175.560 92.590 175.920 ;
            RECT 94.510 175.560 96.430 175.920 ;
            RECT 98.350 175.560 100.270 175.920 ;
            RECT 102.190 175.560 106.555 175.920 ;
            RECT 108.475 175.560 110.395 175.920 ;
            RECT 112.315 175.560 114.235 175.920 ;
            RECT 116.155 175.560 118.075 175.920 ;
            RECT 119.995 175.560 121.915 175.920 ;
            RECT 123.835 175.560 125.755 175.920 ;
            RECT 127.675 175.560 129.595 175.920 ;
            RECT 131.515 175.560 133.435 175.920 ;
            RECT 135.355 175.560 360.320 175.920 ;
            RECT 0.000 175.920 0.160 176.175 ;
            RECT 71.520 175.920 72.470 176.175 ;
            RECT 74.390 175.920 78.435 176.175 ;
            RECT 80.355 175.920 82.275 176.175 ;
            RECT 84.195 175.920 86.115 176.175 ;
            RECT 88.035 175.920 92.590 176.175 ;
            RECT 94.510 175.920 96.430 176.175 ;
            RECT 98.350 175.920 100.270 176.175 ;
            RECT 102.190 175.920 106.555 176.175 ;
            RECT 108.475 175.920 110.395 176.175 ;
            RECT 112.315 175.920 114.235 176.175 ;
            RECT 116.155 175.920 118.075 176.175 ;
            RECT 119.995 175.920 121.915 176.175 ;
            RECT 123.835 175.920 125.755 176.175 ;
            RECT 127.675 175.920 129.595 176.175 ;
            RECT 131.515 175.920 133.435 176.175 ;
            RECT 135.355 175.920 352.720 176.175 ;
            RECT 360.160 175.920 360.320 176.175 ;
            RECT 0.000 176.175 0.160 176.240 ;
            RECT 71.520 176.175 352.720 176.240 ;
            RECT 360.160 176.175 360.320 176.240 ;
            RECT 0.000 176.240 360.320 176.600 ;
            RECT 0.000 176.600 2.880 176.920 ;
            RECT 138.160 176.600 352.720 176.920 ;
            RECT 357.440 176.600 360.320 176.920 ;
            RECT 0.000 176.920 360.320 177.280 ;
            RECT 0.000 177.280 0.160 177.600 ;
            RECT 138.160 177.280 352.720 177.600 ;
            RECT 360.160 177.280 360.320 177.600 ;
            RECT 0.000 177.600 360.320 177.960 ;
            RECT 0.000 177.960 2.880 178.280 ;
            RECT 138.160 177.960 352.720 178.280 ;
            RECT 357.440 177.960 360.320 178.280 ;
            RECT 0.000 178.280 360.320 178.640 ;
            RECT 0.000 178.640 0.160 178.960 ;
            RECT 138.160 178.640 352.720 178.960 ;
            RECT 360.160 178.640 360.320 178.960 ;
            RECT 0.000 178.960 360.320 179.320 ;
            RECT 0.000 179.320 2.880 179.640 ;
            RECT 138.160 179.320 352.720 179.640 ;
            RECT 357.440 179.320 360.320 179.640 ;
            RECT 0.000 179.640 360.320 180.000 ;
            RECT 0.000 180.000 0.160 180.320 ;
            RECT 138.160 180.000 352.720 180.320 ;
            RECT 360.160 180.000 360.320 180.320 ;
            RECT 0.000 180.320 360.320 180.680 ;
            RECT 0.000 180.680 2.880 181.000 ;
            RECT 357.440 180.680 360.320 181.000 ;
            RECT 0.000 181.000 360.320 181.360 ;
            RECT 0.000 181.360 0.160 181.680 ;
            RECT 360.160 181.360 360.320 181.680 ;
            RECT 0.000 181.680 360.320 182.040 ;
            RECT 0.000 182.040 2.880 182.360 ;
            RECT 357.440 182.040 360.320 182.360 ;
            RECT 0.000 182.360 360.320 182.720 ;
            RECT 0.000 182.720 0.160 183.040 ;
            RECT 360.160 182.720 360.320 183.040 ;
            RECT 0.000 183.040 360.320 183.400 ;
            RECT 0.000 183.400 2.880 183.720 ;
            RECT 357.440 183.400 360.320 183.720 ;
            RECT 0.000 183.720 360.320 184.080 ;
            RECT 0.000 184.080 0.160 184.400 ;
            RECT 360.160 184.080 360.320 184.400 ;
            RECT 0.000 184.400 360.320 184.760 ;
            RECT 0.000 184.760 2.880 185.080 ;
            RECT 357.440 184.760 360.320 185.080 ;
            RECT 0.000 185.080 360.320 185.440 ;
            RECT 0.000 185.440 0.160 185.760 ;
            RECT 360.160 185.440 360.320 185.760 ;
            RECT 0.000 185.760 360.320 186.760 ;
            RECT 0.000 186.760 2.880 188.120 ;
            RECT 357.440 186.760 360.320 188.120 ;
            RECT 0.000 188.120 360.320 189.480 ;
            RECT 0.000 189.480 0.160 190.840 ;
            RECT 360.160 189.480 360.320 190.840 ;
            RECT 0.000 190.840 360.320 191.000 ;
    END 
END sram22_64x32m4w8 
END LIBRARY 

